VERSION 5.7 ;
  NOWIREEXTENSIONATPIN ON ;
  DIVIDERCHAR "/" ;
  BUSBITCHARS "[]" ;
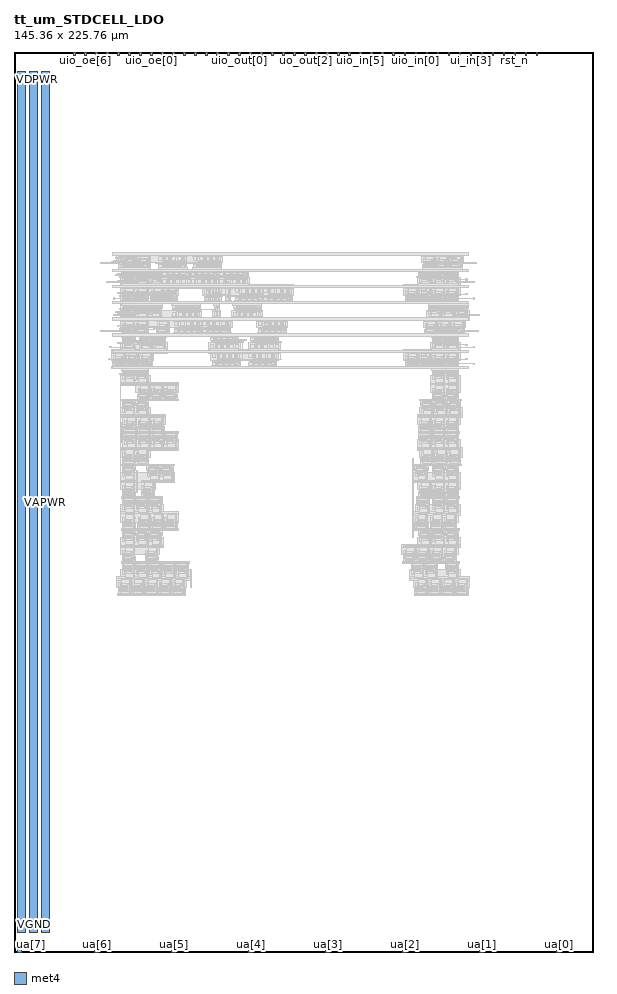
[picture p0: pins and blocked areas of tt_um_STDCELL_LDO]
MACRO tt_um_STDCELL_LDO
  CLASS BLOCK ;
  FOREIGN tt_um_STDCELL_LDO ;
  ORIGIN 0.000 0.000 ;
  SIZE 145.360 BY 225.760 ;
  PIN clk
    DIRECTION INPUT ;
    USE SIGNAL ;
    PORT
      LAYER met4 ;
        RECT 128.190 224.760 128.490 225.760 ;
    END
  END clk
  PIN ena
    DIRECTION INPUT ;
    USE SIGNAL ;
    PORT
      LAYER met4 ;
        RECT 130.950 224.760 131.250 225.760 ;
    END
  END ena
  PIN rst_n
    DIRECTION INPUT ;
    USE SIGNAL ;
    PORT
      LAYER met4 ;
        RECT 125.430 224.760 125.730 225.760 ;
    END
  END rst_n
  PIN ua[0]
    DIRECTION INOUT ;
    USE SIGNAL ;
    ANTENNAGATEAREA 9.000000 ;
    PORT
      LAYER met4 ;
        RECT 136.170 0.000 137.070 1.000 ;
    END
  END ua[0]
  PIN ua[1]
    DIRECTION INOUT ;
    USE SIGNAL ;
    ANTENNAGATEAREA 18.000000 ;
    ANTENNADIFFAREA 1.282500 ;
    PORT
      LAYER met4 ;
        RECT 116.850 0.000 117.750 1.000 ;
    END
  END ua[1]
  PIN ua[2]
    DIRECTION INOUT ;
    USE SIGNAL ;
    ANTENNAGATEAREA 1.125000 ;
    PORT
      LAYER met4 ;
        RECT 97.530 0.000 98.430 1.000 ;
    END
  END ua[2]
  PIN ua[3]
    DIRECTION INOUT ;
    USE SIGNAL ;
    ANTENNAGATEAREA 9.000000 ;
    ANTENNADIFFAREA 82.079994 ;
    PORT
      LAYER met4 ;
        RECT 78.210 0.000 79.110 1.000 ;
    END
  END ua[3]
  PIN ua[4]
    DIRECTION INOUT ;
    USE SIGNAL ;
    PORT
      LAYER met4 ;
        RECT 58.890 0.000 59.790 1.000 ;
    END
  END ua[4]
  PIN ua[5]
    DIRECTION INOUT ;
    USE SIGNAL ;
    PORT
      LAYER met4 ;
        RECT 39.570 0.000 40.470 1.000 ;
    END
  END ua[5]
  PIN ua[6]
    DIRECTION INOUT ;
    USE SIGNAL ;
    PORT
      LAYER met4 ;
        RECT 20.250 0.000 21.150 1.000 ;
    END
  END ua[6]
  PIN ua[7]
    DIRECTION INOUT ;
    USE SIGNAL ;
    PORT
      LAYER met4 ;
        RECT 0.930 0.000 1.830 1.000 ;
    END
  END ua[7]
  PIN ui_in[0]
    DIRECTION INPUT ;
    USE SIGNAL ;
    PORT
      LAYER met4 ;
        RECT 122.670 224.760 122.970 225.760 ;
    END
  END ui_in[0]
  PIN ui_in[1]
    DIRECTION INPUT ;
    USE SIGNAL ;
    PORT
      LAYER met4 ;
        RECT 119.910 224.760 120.210 225.760 ;
    END
  END ui_in[1]
  PIN ui_in[2]
    DIRECTION INPUT ;
    USE SIGNAL ;
    PORT
      LAYER met4 ;
        RECT 117.150 224.760 117.450 225.760 ;
    END
  END ui_in[2]
  PIN ui_in[3]
    DIRECTION INPUT ;
    USE SIGNAL ;
    PORT
      LAYER met4 ;
        RECT 114.390 224.760 114.690 225.760 ;
    END
  END ui_in[3]
  PIN ui_in[4]
    DIRECTION INPUT ;
    USE SIGNAL ;
    PORT
      LAYER met4 ;
        RECT 111.630 224.760 111.930 225.760 ;
    END
  END ui_in[4]
  PIN ui_in[5]
    DIRECTION INPUT ;
    USE SIGNAL ;
    PORT
      LAYER met4 ;
        RECT 108.870 224.760 109.170 225.760 ;
    END
  END ui_in[5]
  PIN ui_in[6]
    DIRECTION INPUT ;
    USE SIGNAL ;
    PORT
      LAYER met4 ;
        RECT 106.110 224.760 106.410 225.760 ;
    END
  END ui_in[6]
  PIN ui_in[7]
    DIRECTION INPUT ;
    USE SIGNAL ;
    PORT
      LAYER met4 ;
        RECT 103.350 224.760 103.650 225.760 ;
    END
  END ui_in[7]
  PIN uio_in[0]
    DIRECTION INPUT ;
    USE SIGNAL ;
    PORT
      LAYER met4 ;
        RECT 100.590 224.760 100.890 225.760 ;
    END
  END uio_in[0]
  PIN uio_in[1]
    DIRECTION INPUT ;
    USE SIGNAL ;
    PORT
      LAYER met4 ;
        RECT 97.830 224.760 98.130 225.760 ;
    END
  END uio_in[1]
  PIN uio_in[2]
    DIRECTION INPUT ;
    USE SIGNAL ;
    PORT
      LAYER met4 ;
        RECT 95.070 224.760 95.370 225.760 ;
    END
  END uio_in[2]
  PIN uio_in[3]
    DIRECTION INPUT ;
    USE SIGNAL ;
    PORT
      LAYER met4 ;
        RECT 92.310 224.760 92.610 225.760 ;
    END
  END uio_in[3]
  PIN uio_in[4]
    DIRECTION INPUT ;
    USE SIGNAL ;
    PORT
      LAYER met4 ;
        RECT 89.550 224.760 89.850 225.760 ;
    END
  END uio_in[4]
  PIN uio_in[5]
    DIRECTION INPUT ;
    USE SIGNAL ;
    PORT
      LAYER met4 ;
        RECT 86.790 224.760 87.090 225.760 ;
    END
  END uio_in[5]
  PIN uio_in[6]
    DIRECTION INPUT ;
    USE SIGNAL ;
    PORT
      LAYER met4 ;
        RECT 84.030 224.760 84.330 225.760 ;
    END
  END uio_in[6]
  PIN uio_in[7]
    DIRECTION INPUT ;
    USE SIGNAL ;
    PORT
      LAYER met4 ;
        RECT 81.270 224.760 81.570 225.760 ;
    END
  END uio_in[7]
  PIN uio_oe[0]
    DIRECTION OUTPUT ;
    USE SIGNAL ;
    PORT
      LAYER met4 ;
        RECT 34.350 224.760 34.650 225.760 ;
    END
  END uio_oe[0]
  PIN uio_oe[1]
    DIRECTION OUTPUT ;
    USE SIGNAL ;
    PORT
      LAYER met4 ;
        RECT 31.590 224.760 31.890 225.760 ;
    END
  END uio_oe[1]
  PIN uio_oe[2]
    DIRECTION OUTPUT ;
    USE SIGNAL ;
    PORT
      LAYER met4 ;
        RECT 28.830 224.760 29.130 225.760 ;
    END
  END uio_oe[2]
  PIN uio_oe[3]
    DIRECTION OUTPUT ;
    USE SIGNAL ;
    PORT
      LAYER met4 ;
        RECT 26.070 224.760 26.370 225.760 ;
    END
  END uio_oe[3]
  PIN uio_oe[4]
    DIRECTION OUTPUT ;
    USE SIGNAL ;
    PORT
      LAYER met4 ;
        RECT 23.310 224.760 23.610 225.760 ;
    END
  END uio_oe[4]
  PIN uio_oe[5]
    DIRECTION OUTPUT ;
    USE SIGNAL ;
    PORT
      LAYER met4 ;
        RECT 20.550 224.760 20.850 225.760 ;
    END
  END uio_oe[5]
  PIN uio_oe[6]
    DIRECTION OUTPUT ;
    USE SIGNAL ;
    PORT
      LAYER met4 ;
        RECT 17.790 224.760 18.090 225.760 ;
    END
  END uio_oe[6]
  PIN uio_oe[7]
    DIRECTION OUTPUT ;
    USE SIGNAL ;
    PORT
      LAYER met4 ;
        RECT 15.030 224.760 15.330 225.760 ;
    END
  END uio_oe[7]
  PIN uio_out[0]
    DIRECTION OUTPUT ;
    USE SIGNAL ;
    PORT
      LAYER met4 ;
        RECT 56.430 224.760 56.730 225.760 ;
    END
  END uio_out[0]
  PIN uio_out[1]
    DIRECTION OUTPUT ;
    USE SIGNAL ;
    PORT
      LAYER met4 ;
        RECT 53.670 224.760 53.970 225.760 ;
    END
  END uio_out[1]
  PIN uio_out[2]
    DIRECTION OUTPUT ;
    USE SIGNAL ;
    PORT
      LAYER met4 ;
        RECT 50.910 224.760 51.210 225.760 ;
    END
  END uio_out[2]
  PIN uio_out[3]
    DIRECTION OUTPUT ;
    USE SIGNAL ;
    PORT
      LAYER met4 ;
        RECT 48.150 224.760 48.450 225.760 ;
    END
  END uio_out[3]
  PIN uio_out[4]
    DIRECTION OUTPUT ;
    USE SIGNAL ;
    PORT
      LAYER met4 ;
        RECT 45.390 224.760 45.690 225.760 ;
    END
  END uio_out[4]
  PIN uio_out[5]
    DIRECTION OUTPUT ;
    USE SIGNAL ;
    PORT
      LAYER met4 ;
        RECT 42.630 224.760 42.930 225.760 ;
    END
  END uio_out[5]
  PIN uio_out[6]
    DIRECTION OUTPUT ;
    USE SIGNAL ;
    PORT
      LAYER met4 ;
        RECT 39.870 224.760 40.170 225.760 ;
    END
  END uio_out[6]
  PIN uio_out[7]
    DIRECTION OUTPUT ;
    USE SIGNAL ;
    PORT
      LAYER met4 ;
        RECT 37.110 224.760 37.410 225.760 ;
    END
  END uio_out[7]
  PIN uo_out[0]
    DIRECTION OUTPUT ;
    USE SIGNAL ;
    PORT
      LAYER met4 ;
        RECT 78.510 224.760 78.810 225.760 ;
    END
  END uo_out[0]
  PIN uo_out[1]
    DIRECTION OUTPUT ;
    USE SIGNAL ;
    PORT
      LAYER met4 ;
        RECT 75.750 224.760 76.050 225.760 ;
    END
  END uo_out[1]
  PIN uo_out[2]
    DIRECTION OUTPUT ;
    USE SIGNAL ;
    PORT
      LAYER met4 ;
        RECT 72.990 224.760 73.290 225.760 ;
    END
  END uo_out[2]
  PIN uo_out[3]
    DIRECTION OUTPUT ;
    USE SIGNAL ;
    PORT
      LAYER met4 ;
        RECT 70.230 224.760 70.530 225.760 ;
    END
  END uo_out[3]
  PIN uo_out[4]
    DIRECTION OUTPUT ;
    USE SIGNAL ;
    PORT
      LAYER met4 ;
        RECT 67.470 224.760 67.770 225.760 ;
    END
  END uo_out[4]
  PIN uo_out[5]
    DIRECTION OUTPUT ;
    USE SIGNAL ;
    PORT
      LAYER met4 ;
        RECT 64.710 224.760 65.010 225.760 ;
    END
  END uo_out[5]
  PIN uo_out[6]
    DIRECTION OUTPUT ;
    USE SIGNAL ;
    PORT
      LAYER met4 ;
        RECT 61.950 224.760 62.250 225.760 ;
    END
  END uo_out[6]
  PIN uo_out[7]
    DIRECTION OUTPUT ;
    USE SIGNAL ;
    PORT
      LAYER met4 ;
        RECT 59.190 224.760 59.490 225.760 ;
    END
  END uo_out[7]
  PIN VDPWR
    DIRECTION INOUT ;
    USE POWER ;
    PORT
      LAYER met4 ;
        RECT 1.000 5.000 3.000 220.760 ;
    END
  END VDPWR
  PIN VGND
    DIRECTION INOUT ;
    USE GROUND ;
    PORT
      LAYER met4 ;
        RECT 4.000 5.000 6.000 220.760 ;
    END
  END VGND
  PIN VAPWR
    DIRECTION INOUT ;
    USE POWER ;
    PORT
      LAYER met4 ;
        RECT 7.000 5.000 9.000 220.760 ;
    END
  END VAPWR
  OBS
      LAYER nwell ;
        RECT 25.800 172.905 52.380 175.505 ;
        RECT 102.120 172.905 112.860 175.505 ;
      LAYER pwell ;
        RECT 26.220 171.235 27.550 172.435 ;
        RECT 27.590 171.235 30.910 172.515 ;
        RECT 30.950 171.235 34.270 172.515 ;
        RECT 36.475 171.235 43.375 172.605 ;
        RECT 45.115 171.235 52.015 172.605 ;
        RECT 102.470 171.235 105.790 172.515 ;
        RECT 105.830 171.235 109.150 172.515 ;
        RECT 109.190 171.235 112.510 172.515 ;
        RECT 26.000 170.805 58.900 171.235 ;
        RECT 101.360 170.805 112.660 171.235 ;
        RECT 27.110 169.525 30.430 170.805 ;
        RECT 30.470 169.525 33.790 170.805 ;
        RECT 33.830 169.525 37.150 170.805 ;
        RECT 37.435 169.435 44.335 170.805 ;
        RECT 44.635 169.435 51.535 170.805 ;
        RECT 51.835 169.435 58.735 170.805 ;
        RECT 101.510 169.525 104.830 170.805 ;
        RECT 104.870 169.525 108.190 170.805 ;
        RECT 108.230 169.525 111.550 170.805 ;
      LAYER nwell ;
        RECT 26.760 167.365 59.100 169.135 ;
        RECT 101.160 167.365 111.900 169.135 ;
        RECT 26.760 166.535 70.140 167.365 ;
        RECT 26.760 164.765 41.340 166.535 ;
        RECT 47.400 164.765 70.140 166.535 ;
        RECT 97.800 164.765 111.900 167.365 ;
      LAYER pwell ;
        RECT 27.110 163.095 30.430 164.375 ;
        RECT 30.470 163.095 33.790 164.375 ;
        RECT 34.310 163.095 37.630 164.375 ;
        RECT 37.670 163.095 40.990 164.375 ;
        RECT 47.820 163.095 49.150 164.295 ;
        RECT 49.260 163.095 50.590 164.295 ;
        RECT 50.700 163.095 52.030 164.295 ;
        RECT 53.100 163.095 54.430 164.295 ;
        RECT 55.675 163.095 62.575 164.465 ;
        RECT 62.875 163.095 69.775 164.465 ;
        RECT 98.150 163.095 101.470 164.375 ;
        RECT 101.510 163.095 104.830 164.375 ;
        RECT 104.870 163.095 108.190 164.375 ;
        RECT 108.230 163.095 111.550 164.375 ;
        RECT 26.960 162.665 46.900 163.095 ;
        RECT 47.600 162.665 52.180 163.095 ;
        RECT 52.880 162.665 54.580 163.095 ;
        RECT 54.800 162.665 69.940 163.095 ;
        RECT 98.000 162.665 114.100 163.095 ;
        RECT 27.110 161.385 30.430 162.665 ;
        RECT 30.470 161.385 33.790 162.665 ;
        RECT 33.830 161.385 37.150 162.665 ;
        RECT 39.835 161.295 46.735 162.665 ;
        RECT 50.220 161.465 51.550 162.665 ;
        RECT 55.195 161.295 62.095 162.665 ;
        RECT 103.910 161.385 107.230 162.665 ;
        RECT 107.270 161.385 110.590 162.665 ;
        RECT 110.630 161.385 113.950 162.665 ;
      LAYER nwell ;
        RECT 26.760 159.225 47.100 160.995 ;
        RECT 49.800 159.225 51.900 160.995 ;
        RECT 54.600 159.225 62.460 160.995 ;
        RECT 103.560 159.225 114.300 160.995 ;
        RECT 26.760 158.395 68.700 159.225 ;
        RECT 26.760 156.625 54.780 158.395 ;
        RECT 60.840 156.625 68.700 158.395 ;
        RECT 102.600 158.395 114.300 159.225 ;
        RECT 102.600 156.625 113.340 158.395 ;
      LAYER pwell ;
        RECT 27.110 154.955 30.430 156.235 ;
        RECT 30.470 154.955 33.790 156.235 ;
        RECT 35.750 154.955 39.070 156.235 ;
        RECT 40.315 154.955 47.215 156.325 ;
        RECT 47.515 154.955 54.415 156.325 ;
        RECT 61.435 154.955 68.335 156.325 ;
        RECT 102.950 154.955 106.270 156.235 ;
        RECT 106.310 154.955 109.630 156.235 ;
        RECT 109.670 154.955 112.990 156.235 ;
        RECT 26.960 154.525 39.220 154.955 ;
        RECT 39.920 154.525 56.500 154.955 ;
        RECT 59.120 154.525 68.500 154.955 ;
        RECT 102.800 154.525 113.140 154.955 ;
        RECT 27.110 153.245 30.430 154.525 ;
        RECT 31.430 153.245 34.750 154.525 ;
        RECT 34.790 153.245 38.110 154.525 ;
        RECT 49.435 153.155 56.335 154.525 ;
        RECT 59.515 153.155 66.415 154.525 ;
        RECT 104.870 153.245 108.190 154.525 ;
        RECT 108.230 153.245 111.550 154.525 ;
      LAYER nwell ;
        RECT 26.760 151.085 38.460 152.855 ;
        RECT 24.360 150.255 38.460 151.085 ;
        RECT 48.840 151.085 56.700 152.855 ;
        RECT 58.920 151.085 66.780 152.855 ;
        RECT 104.520 151.085 111.900 152.855 ;
        RECT 48.840 150.255 66.780 151.085 ;
        RECT 24.360 148.485 35.100 150.255 ;
        RECT 49.320 148.485 66.300 150.255 ;
        RECT 97.800 148.485 111.900 151.085 ;
      LAYER pwell ;
        RECT 24.710 146.815 28.030 148.095 ;
        RECT 28.070 146.815 31.390 148.095 ;
        RECT 31.430 146.815 34.750 148.095 ;
        RECT 49.915 146.815 56.815 148.185 ;
        RECT 59.035 146.815 65.935 148.185 ;
        RECT 98.150 146.815 101.470 148.095 ;
        RECT 101.510 146.815 104.830 148.095 ;
        RECT 104.870 146.815 108.190 148.095 ;
        RECT 108.230 146.815 111.550 148.095 ;
        RECT 24.560 146.385 34.900 146.815 ;
        RECT 49.520 146.385 56.980 146.815 ;
        RECT 58.640 146.385 66.100 146.815 ;
        RECT 98.000 146.385 111.700 146.815 ;
        RECT 27.110 145.105 30.430 146.385 ;
        RECT 30.470 145.105 33.790 146.385 ;
        RECT 104.870 145.105 108.190 146.385 ;
        RECT 108.230 145.105 111.550 146.385 ;
      LAYER nwell ;
        RECT 26.760 142.945 34.140 144.715 ;
        RECT 26.760 142.115 41.340 142.945 ;
        RECT 30.600 140.345 41.340 142.115 ;
        RECT 104.520 140.345 111.900 144.715 ;
      LAYER pwell ;
        RECT 30.950 138.675 34.270 139.955 ;
        RECT 34.310 138.675 37.630 139.955 ;
        RECT 37.670 138.675 40.990 139.955 ;
        RECT 104.870 138.675 108.190 139.955 ;
        RECT 108.230 138.675 111.550 139.955 ;
        RECT 26.960 138.245 41.140 138.675 ;
        RECT 101.840 138.245 112.180 138.675 ;
        RECT 27.110 136.965 30.430 138.245 ;
        RECT 30.470 136.965 33.790 138.245 ;
        RECT 101.990 136.965 105.310 138.245 ;
        RECT 105.350 136.965 108.670 138.245 ;
        RECT 108.710 136.965 112.030 138.245 ;
      LAYER nwell ;
        RECT 26.760 134.805 34.140 136.575 ;
        RECT 101.640 134.805 112.380 136.575 ;
        RECT 26.760 133.975 37.980 134.805 ;
        RECT 27.240 132.205 37.980 133.975 ;
        RECT 101.160 133.975 112.380 134.805 ;
        RECT 101.160 132.205 111.900 133.975 ;
      LAYER pwell ;
        RECT 27.590 130.535 30.910 131.815 ;
        RECT 30.950 130.535 34.270 131.815 ;
        RECT 34.310 130.535 37.630 131.815 ;
        RECT 101.510 130.535 104.830 131.815 ;
        RECT 104.870 130.535 108.190 131.815 ;
        RECT 108.230 130.535 111.550 131.815 ;
        RECT 27.440 130.105 41.140 130.535 ;
        RECT 101.360 130.105 111.700 130.535 ;
        RECT 27.590 128.825 30.910 130.105 ;
        RECT 30.950 128.825 34.270 130.105 ;
        RECT 34.310 128.825 37.630 130.105 ;
        RECT 37.670 128.825 40.990 130.105 ;
        RECT 101.510 128.825 104.830 130.105 ;
        RECT 104.870 128.825 108.190 130.105 ;
        RECT 108.230 128.825 111.550 130.105 ;
      LAYER nwell ;
        RECT 27.240 126.665 41.340 128.435 ;
        RECT 26.760 125.835 41.340 126.665 ;
        RECT 101.160 126.665 111.900 128.435 ;
        RECT 101.160 125.835 112.380 126.665 ;
        RECT 26.760 124.065 34.140 125.835 ;
        RECT 101.640 124.065 112.380 125.835 ;
      LAYER pwell ;
        RECT 27.110 122.395 30.430 123.675 ;
        RECT 30.470 122.395 33.790 123.675 ;
        RECT 101.990 122.395 105.310 123.675 ;
        RECT 105.350 122.395 108.670 123.675 ;
        RECT 108.710 122.395 112.030 123.675 ;
        RECT 26.960 121.965 40.180 122.395 ;
        RECT 100.400 121.965 112.180 122.395 ;
        RECT 27.110 120.685 30.430 121.965 ;
        RECT 33.350 120.685 36.670 121.965 ;
        RECT 36.710 120.685 40.030 121.965 ;
        RECT 100.550 120.685 103.870 121.965 ;
        RECT 104.870 120.685 108.190 121.965 ;
        RECT 108.230 120.685 111.550 121.965 ;
      LAYER nwell ;
        RECT 26.760 117.695 40.380 120.295 ;
        RECT 100.200 117.695 111.900 120.295 ;
        RECT 26.760 115.925 35.580 117.695 ;
        RECT 101.160 115.925 111.900 117.695 ;
      LAYER pwell ;
        RECT 27.110 114.255 30.430 115.535 ;
        RECT 31.910 114.255 35.230 115.535 ;
        RECT 101.510 114.255 104.830 115.535 ;
        RECT 104.870 114.255 108.190 115.535 ;
        RECT 108.230 114.255 111.550 115.535 ;
        RECT 26.960 113.825 37.300 114.255 ;
        RECT 100.880 113.825 111.700 114.255 ;
        RECT 27.110 112.545 30.430 113.825 ;
        RECT 30.470 112.545 33.790 113.825 ;
        RECT 33.830 112.545 37.150 113.825 ;
        RECT 101.030 112.545 104.350 113.825 ;
        RECT 104.870 112.545 108.190 113.825 ;
        RECT 108.230 112.545 111.550 113.825 ;
      LAYER nwell ;
        RECT 26.760 110.385 37.500 112.155 ;
        RECT 100.680 110.385 111.900 112.155 ;
        RECT 26.760 107.785 41.340 110.385 ;
        RECT 100.200 109.555 111.900 110.385 ;
        RECT 100.200 107.785 111.420 109.555 ;
      LAYER pwell ;
        RECT 27.110 106.115 30.430 107.395 ;
        RECT 30.950 106.115 34.270 107.395 ;
        RECT 34.310 106.115 37.630 107.395 ;
        RECT 37.670 106.115 40.990 107.395 ;
        RECT 100.550 106.115 103.870 107.395 ;
        RECT 104.390 106.115 107.710 107.395 ;
        RECT 107.750 106.115 111.070 107.395 ;
        RECT 26.960 105.685 41.140 106.115 ;
        RECT 100.400 105.685 111.700 106.115 ;
        RECT 27.110 104.405 30.430 105.685 ;
        RECT 30.470 104.405 33.790 105.685 ;
        RECT 33.830 104.405 37.150 105.685 ;
        RECT 101.510 104.405 104.830 105.685 ;
        RECT 104.870 104.405 108.190 105.685 ;
        RECT 108.230 104.405 111.550 105.685 ;
      LAYER nwell ;
        RECT 26.760 101.415 37.500 104.015 ;
        RECT 101.160 102.245 111.900 104.015 ;
        RECT 97.320 101.415 111.900 102.245 ;
        RECT 26.760 99.645 36.540 101.415 ;
        RECT 97.320 99.645 111.420 101.415 ;
      LAYER pwell ;
        RECT 27.110 97.975 30.430 99.255 ;
        RECT 32.870 97.975 36.190 99.255 ;
        RECT 97.670 97.975 100.990 99.255 ;
        RECT 101.030 97.975 104.350 99.255 ;
        RECT 104.390 97.975 107.710 99.255 ;
        RECT 107.750 97.975 111.070 99.255 ;
        RECT 26.960 97.545 44.020 97.975 ;
        RECT 97.520 97.545 111.700 97.975 ;
        RECT 27.110 96.265 30.430 97.545 ;
        RECT 30.470 96.265 33.790 97.545 ;
        RECT 33.830 96.265 37.150 97.545 ;
        RECT 37.190 96.265 40.510 97.545 ;
        RECT 40.550 96.265 43.870 97.545 ;
        RECT 99.590 96.265 102.910 97.545 ;
        RECT 102.950 96.265 106.270 97.545 ;
        RECT 108.230 96.265 111.550 97.545 ;
      LAYER nwell ;
        RECT 26.760 94.105 44.220 95.875 ;
        RECT 25.800 93.275 44.220 94.105 ;
        RECT 99.240 94.105 111.900 95.875 ;
        RECT 99.240 93.275 114.300 94.105 ;
        RECT 25.800 91.505 43.260 93.275 ;
        RECT 100.200 91.505 114.300 93.275 ;
      LAYER pwell ;
        RECT 26.150 89.835 29.470 91.115 ;
        RECT 29.510 89.835 32.830 91.115 ;
        RECT 32.870 89.835 36.190 91.115 ;
        RECT 36.230 89.835 39.550 91.115 ;
        RECT 39.590 89.835 42.910 91.115 ;
        RECT 100.550 89.835 103.870 91.115 ;
        RECT 103.910 89.835 107.230 91.115 ;
        RECT 107.270 89.835 110.590 91.115 ;
        RECT 110.630 89.835 113.950 91.115 ;
        RECT 26.000 89.405 43.060 89.835 ;
        RECT 100.400 89.405 114.100 89.835 ;
      LAYER li1 ;
        RECT 26.130 175.005 34.290 175.175 ;
        RECT 36.210 175.005 43.410 175.175 ;
        RECT 44.850 175.005 52.050 175.175 ;
        RECT 102.450 175.005 112.530 175.175 ;
        RECT 26.220 173.195 26.810 174.775 ;
        RECT 27.090 174.215 27.475 174.775 ;
        RECT 27.090 174.045 27.485 174.215 ;
        RECT 27.090 173.195 27.475 174.045 ;
        RECT 26.255 172.570 26.965 172.955 ;
        RECT 26.220 171.385 26.810 172.345 ;
        RECT 27.145 171.515 27.475 173.195 ;
        RECT 27.745 173.120 28.220 174.025 ;
        RECT 28.400 173.730 30.370 174.775 ;
        RECT 30.550 174.215 30.805 174.775 ;
        RECT 30.550 174.045 30.885 174.215 ;
        RECT 28.400 173.300 29.845 173.730 ;
        RECT 27.745 172.950 29.635 173.120 ;
        RECT 30.015 172.975 30.380 173.560 ;
        RECT 30.550 173.145 30.805 174.045 ;
        RECT 27.745 172.355 27.915 172.950 ;
        RECT 28.085 172.525 28.875 172.770 ;
        RECT 29.045 172.745 29.635 172.950 ;
        RECT 29.845 172.645 30.435 172.975 ;
        RECT 27.745 171.925 27.950 172.355 ;
        RECT 28.120 172.010 29.845 172.355 ;
        RECT 30.015 172.180 30.380 172.645 ;
        RECT 30.605 172.475 30.805 173.145 ;
        RECT 28.120 171.755 30.370 172.010 ;
        RECT 28.040 171.385 30.370 171.755 ;
        RECT 30.550 171.595 30.805 172.475 ;
        RECT 31.105 173.120 31.580 174.025 ;
        RECT 31.760 173.730 33.730 174.775 ;
        RECT 31.760 173.300 33.205 173.730 ;
        RECT 31.105 172.950 32.995 173.120 ;
        RECT 33.375 172.975 33.740 173.560 ;
        RECT 33.910 173.145 34.165 174.775 ;
        RECT 36.305 174.645 43.235 174.815 ;
        RECT 36.305 173.465 37.195 174.645 ;
        RECT 31.105 172.355 31.275 172.950 ;
        RECT 31.445 172.525 32.235 172.770 ;
        RECT 32.405 172.745 32.995 172.950 ;
        RECT 33.205 172.645 33.795 172.975 ;
        RECT 31.105 171.925 31.310 172.355 ;
        RECT 31.480 172.010 33.205 172.355 ;
        RECT 33.375 172.180 33.740 172.645 ;
        RECT 33.965 172.475 34.165 173.145 ;
        RECT 37.485 173.225 37.815 174.465 ;
        RECT 37.985 173.405 38.875 174.645 ;
        RECT 39.045 173.225 39.375 174.465 ;
        RECT 39.545 173.405 40.435 174.645 ;
        RECT 40.605 173.225 40.935 174.465 ;
        RECT 41.105 173.405 41.995 174.645 ;
        RECT 42.165 173.225 42.495 174.465 ;
        RECT 42.665 173.405 43.235 174.645 ;
        RECT 44.945 174.645 51.875 174.815 ;
        RECT 44.945 173.465 45.835 174.645 ;
        RECT 46.125 173.225 46.455 174.465 ;
        RECT 46.625 173.405 47.515 174.645 ;
        RECT 47.685 173.225 48.015 174.465 ;
        RECT 48.185 173.405 49.075 174.645 ;
        RECT 49.245 173.225 49.575 174.465 ;
        RECT 49.745 173.405 50.635 174.645 ;
        RECT 50.805 173.225 51.135 174.465 ;
        RECT 51.305 173.405 51.875 174.645 ;
        RECT 37.485 173.055 43.320 173.225 ;
        RECT 46.125 173.055 51.960 173.225 ;
        RECT 38.875 173.025 39.045 173.055 ;
        RECT 36.495 172.835 36.665 172.855 ;
        RECT 36.495 172.685 42.970 172.835 ;
        RECT 36.520 172.600 42.970 172.685 ;
        RECT 31.480 171.755 33.730 172.010 ;
        RECT 31.400 171.385 33.730 171.755 ;
        RECT 33.910 171.595 34.165 172.475 ;
        RECT 37.405 172.415 42.435 172.420 ;
        RECT 43.150 172.415 43.320 173.055 ;
        RECT 45.335 172.835 45.505 172.855 ;
        RECT 45.160 172.600 51.610 172.835 ;
        RECT 36.305 171.570 37.195 172.405 ;
        RECT 37.405 172.250 43.320 172.415 ;
        RECT 46.045 172.415 51.075 172.420 ;
        RECT 51.790 172.415 51.960 173.055 ;
        RECT 37.405 171.750 37.615 172.250 ;
        RECT 37.785 171.570 38.795 172.065 ;
        RECT 38.965 171.750 39.175 172.250 ;
        RECT 39.345 171.570 40.355 172.065 ;
        RECT 40.525 171.750 40.735 172.250 ;
        RECT 42.125 172.245 43.320 172.250 ;
        RECT 40.905 171.570 41.955 172.065 ;
        RECT 42.125 171.750 42.775 172.245 ;
        RECT 42.945 171.570 43.315 172.065 ;
        RECT 36.305 171.400 43.315 171.570 ;
        RECT 44.945 171.570 45.835 172.405 ;
        RECT 46.045 172.250 51.960 172.415 ;
        RECT 46.045 171.750 46.255 172.250 ;
        RECT 46.425 171.570 47.435 172.065 ;
        RECT 47.605 171.750 47.815 172.250 ;
        RECT 47.985 171.570 48.995 172.065 ;
        RECT 49.165 171.750 49.375 172.250 ;
        RECT 50.765 172.245 51.960 172.250 ;
        RECT 102.625 173.120 103.100 174.025 ;
        RECT 103.280 173.730 105.250 174.775 ;
        RECT 103.280 173.300 104.725 173.730 ;
        RECT 102.625 172.950 104.515 173.120 ;
        RECT 104.895 172.975 105.260 173.560 ;
        RECT 105.430 173.145 105.685 174.775 ;
        RECT 102.625 172.355 102.795 172.950 ;
        RECT 102.965 172.525 103.755 172.770 ;
        RECT 103.925 172.745 104.515 172.950 ;
        RECT 104.725 172.645 105.315 172.975 ;
        RECT 49.545 171.570 50.595 172.065 ;
        RECT 50.765 171.750 51.415 172.245 ;
        RECT 51.585 171.570 51.955 172.065 ;
        RECT 102.625 171.925 102.830 172.355 ;
        RECT 103.000 172.010 104.725 172.355 ;
        RECT 104.895 172.180 105.260 172.645 ;
        RECT 105.485 172.475 105.685 173.145 ;
        RECT 103.000 171.755 105.250 172.010 ;
        RECT 44.945 171.400 51.955 171.570 ;
        RECT 102.920 171.385 105.250 171.755 ;
        RECT 105.430 171.595 105.685 172.475 ;
        RECT 105.985 173.120 106.460 174.025 ;
        RECT 106.640 173.730 108.610 174.775 ;
        RECT 108.790 174.215 109.045 174.775 ;
        RECT 108.790 174.045 109.085 174.215 ;
        RECT 106.640 173.300 108.085 173.730 ;
        RECT 105.985 172.950 107.875 173.120 ;
        RECT 108.255 172.975 108.620 173.560 ;
        RECT 108.790 173.145 109.045 174.045 ;
        RECT 105.985 172.355 106.155 172.950 ;
        RECT 106.325 172.525 107.115 172.770 ;
        RECT 107.285 172.745 107.875 172.950 ;
        RECT 108.085 172.645 108.675 172.975 ;
        RECT 105.985 171.925 106.190 172.355 ;
        RECT 106.360 172.010 108.085 172.355 ;
        RECT 108.255 172.180 108.620 172.645 ;
        RECT 108.845 172.475 109.045 173.145 ;
        RECT 106.360 171.755 108.610 172.010 ;
        RECT 106.280 171.385 108.610 171.755 ;
        RECT 108.790 171.595 109.045 172.475 ;
        RECT 109.345 173.120 109.820 174.025 ;
        RECT 110.000 173.730 111.970 174.775 ;
        RECT 110.000 173.300 111.445 173.730 ;
        RECT 109.345 172.950 111.235 173.120 ;
        RECT 111.615 172.975 111.980 173.560 ;
        RECT 112.150 173.145 112.405 174.775 ;
        RECT 109.345 172.355 109.515 172.950 ;
        RECT 109.685 172.525 110.475 172.770 ;
        RECT 110.645 172.745 111.235 172.950 ;
        RECT 111.445 172.645 112.035 172.975 ;
        RECT 112.205 172.855 112.405 173.145 ;
        RECT 112.205 172.685 112.485 172.855 ;
        RECT 109.345 171.925 109.550 172.355 ;
        RECT 109.720 172.010 111.445 172.355 ;
        RECT 111.615 172.180 111.980 172.645 ;
        RECT 112.205 172.475 112.405 172.685 ;
        RECT 109.720 171.755 111.970 172.010 ;
        RECT 109.640 171.385 111.970 171.755 ;
        RECT 112.150 171.595 112.405 172.475 ;
        RECT 26.130 170.935 58.770 171.105 ;
        RECT 101.490 170.935 112.530 171.105 ;
        RECT 27.560 170.285 29.890 170.655 ;
        RECT 27.265 169.685 27.470 170.115 ;
        RECT 27.640 170.030 29.890 170.285 ;
        RECT 27.640 169.685 29.365 170.030 ;
        RECT 26.635 156.280 26.805 169.455 ;
        RECT 27.265 169.090 27.435 169.685 ;
        RECT 27.605 169.270 28.395 169.515 ;
        RECT 29.535 169.395 29.900 169.860 ;
        RECT 30.070 169.565 30.325 170.445 ;
        RECT 30.920 170.285 33.250 170.655 ;
        RECT 28.565 169.090 29.155 169.295 ;
        RECT 27.265 168.920 29.155 169.090 ;
        RECT 29.365 169.065 29.955 169.395 ;
        RECT 27.265 168.015 27.740 168.920 ;
        RECT 27.920 168.310 29.365 168.740 ;
        RECT 29.535 168.480 29.900 169.065 ;
        RECT 30.125 168.895 30.325 169.565 ;
        RECT 27.920 167.265 29.890 168.310 ;
        RECT 30.070 168.095 30.325 168.895 ;
        RECT 30.625 169.685 30.830 170.115 ;
        RECT 31.000 170.030 33.250 170.285 ;
        RECT 31.000 169.685 32.725 170.030 ;
        RECT 30.625 169.090 30.795 169.685 ;
        RECT 30.965 169.270 31.755 169.515 ;
        RECT 32.895 169.395 33.260 169.860 ;
        RECT 33.430 169.565 33.685 170.445 ;
        RECT 34.280 170.285 36.610 170.655 ;
        RECT 37.265 170.470 44.275 170.640 ;
        RECT 31.925 169.090 32.515 169.295 ;
        RECT 30.625 168.920 32.515 169.090 ;
        RECT 32.725 169.065 33.315 169.395 ;
        RECT 32.895 168.945 33.265 169.065 ;
        RECT 30.070 167.925 30.375 168.095 ;
        RECT 30.625 168.015 31.100 168.920 ;
        RECT 31.280 168.310 32.725 168.740 ;
        RECT 32.895 168.480 33.260 168.945 ;
        RECT 33.485 168.895 33.685 169.565 ;
        RECT 30.070 167.265 30.325 167.925 ;
        RECT 31.280 167.265 33.250 168.310 ;
        RECT 33.430 167.265 33.685 168.895 ;
        RECT 33.985 169.685 34.190 170.115 ;
        RECT 34.360 170.030 36.610 170.285 ;
        RECT 34.360 169.685 36.085 170.030 ;
        RECT 33.985 169.090 34.155 169.685 ;
        RECT 34.325 169.270 35.115 169.515 ;
        RECT 36.255 169.455 36.620 169.860 ;
        RECT 36.790 169.565 37.045 170.445 ;
        RECT 37.265 169.635 38.155 170.470 ;
        RECT 38.365 169.790 38.575 170.290 ;
        RECT 38.745 169.975 39.755 170.470 ;
        RECT 38.875 169.790 39.045 169.795 ;
        RECT 39.925 169.790 40.135 170.290 ;
        RECT 40.305 169.975 41.315 170.470 ;
        RECT 41.485 169.790 41.695 170.290 ;
        RECT 41.865 169.975 42.915 170.470 ;
        RECT 43.085 169.795 43.735 170.290 ;
        RECT 43.905 169.975 44.275 170.470 ;
        RECT 44.465 170.470 51.475 170.640 ;
        RECT 43.085 169.790 44.280 169.795 ;
        RECT 38.365 169.625 44.280 169.790 ;
        RECT 44.465 169.635 45.355 170.470 ;
        RECT 45.565 169.790 45.775 170.290 ;
        RECT 45.945 169.975 46.955 170.470 ;
        RECT 47.125 169.790 47.335 170.290 ;
        RECT 47.505 169.975 48.515 170.470 ;
        RECT 48.685 169.790 48.895 170.290 ;
        RECT 49.065 169.975 50.115 170.470 ;
        RECT 50.285 169.795 50.935 170.290 ;
        RECT 51.105 169.975 51.475 170.470 ;
        RECT 51.665 170.470 58.675 170.640 ;
        RECT 50.285 169.790 51.480 169.795 ;
        RECT 38.365 169.620 43.395 169.625 ;
        RECT 36.155 169.395 36.620 169.455 ;
        RECT 35.285 169.090 35.875 169.295 ;
        RECT 33.985 168.920 35.875 169.090 ;
        RECT 36.085 169.065 36.675 169.395 ;
        RECT 33.985 168.015 34.460 168.920 ;
        RECT 34.640 168.310 36.085 168.740 ;
        RECT 36.255 168.480 36.620 169.065 ;
        RECT 36.845 168.895 37.045 169.565 ;
        RECT 37.515 169.440 37.685 169.455 ;
        RECT 37.480 169.205 43.930 169.440 ;
        RECT 44.110 168.985 44.280 169.625 ;
        RECT 45.565 169.625 51.480 169.790 ;
        RECT 51.665 169.635 52.555 170.470 ;
        RECT 52.765 169.790 52.975 170.290 ;
        RECT 53.145 169.975 54.155 170.470 ;
        RECT 54.325 169.790 54.535 170.290 ;
        RECT 54.705 169.975 55.715 170.470 ;
        RECT 55.885 169.790 56.095 170.290 ;
        RECT 56.265 169.975 57.315 170.470 ;
        RECT 57.485 169.795 58.135 170.290 ;
        RECT 58.305 169.975 58.675 170.470 ;
        RECT 101.960 170.285 104.290 170.655 ;
        RECT 57.485 169.790 58.680 169.795 ;
        RECT 45.565 169.620 50.595 169.625 ;
        RECT 44.655 169.440 44.825 169.455 ;
        RECT 44.655 169.285 51.130 169.440 ;
        RECT 44.680 169.205 51.130 169.285 ;
        RECT 51.310 168.985 51.480 169.625 ;
        RECT 52.765 169.625 58.680 169.790 ;
        RECT 52.765 169.620 57.795 169.625 ;
        RECT 51.795 169.440 51.965 169.455 ;
        RECT 51.795 169.285 58.330 169.440 ;
        RECT 51.880 169.205 58.330 169.285 ;
        RECT 58.510 168.985 58.680 169.625 ;
        RECT 34.640 167.265 36.610 168.310 ;
        RECT 36.790 167.265 37.045 168.895 ;
        RECT 38.445 168.815 44.280 168.985 ;
        RECT 45.645 168.815 51.480 168.985 ;
        RECT 52.845 168.815 58.680 168.985 ;
        RECT 101.665 169.685 101.870 170.115 ;
        RECT 102.040 170.030 104.290 170.285 ;
        RECT 102.040 169.685 103.765 170.030 ;
        RECT 101.665 169.090 101.835 169.685 ;
        RECT 102.005 169.270 102.795 169.515 ;
        RECT 103.935 169.455 104.300 169.860 ;
        RECT 104.470 169.565 104.725 170.445 ;
        RECT 105.320 170.285 107.650 170.655 ;
        RECT 103.815 169.395 104.300 169.455 ;
        RECT 102.965 169.090 103.555 169.295 ;
        RECT 101.665 168.920 103.555 169.090 ;
        RECT 103.765 169.065 104.355 169.395 ;
        RECT 37.265 167.395 38.155 168.575 ;
        RECT 38.445 167.575 38.775 168.815 ;
        RECT 38.945 167.395 39.835 168.635 ;
        RECT 40.005 167.575 40.335 168.815 ;
        RECT 40.505 167.395 41.395 168.635 ;
        RECT 41.565 167.575 41.895 168.815 ;
        RECT 42.065 167.395 42.955 168.635 ;
        RECT 43.125 167.575 43.455 168.815 ;
        RECT 43.625 167.395 44.195 168.635 ;
        RECT 37.265 167.225 44.195 167.395 ;
        RECT 44.465 167.395 45.355 168.575 ;
        RECT 45.645 167.575 45.975 168.815 ;
        RECT 46.145 167.395 47.035 168.635 ;
        RECT 47.205 167.575 47.535 168.815 ;
        RECT 47.705 167.395 48.595 168.635 ;
        RECT 48.765 167.575 49.095 168.815 ;
        RECT 49.265 167.395 50.155 168.635 ;
        RECT 50.325 167.575 50.655 168.815 ;
        RECT 50.825 167.395 51.395 168.635 ;
        RECT 44.465 167.225 51.395 167.395 ;
        RECT 51.665 167.395 52.555 168.575 ;
        RECT 52.845 168.095 53.175 168.815 ;
        RECT 52.815 167.925 53.175 168.095 ;
        RECT 52.845 167.575 53.175 167.925 ;
        RECT 53.345 167.395 54.235 168.635 ;
        RECT 54.405 167.575 54.735 168.815 ;
        RECT 54.905 167.395 55.795 168.635 ;
        RECT 55.965 167.575 56.295 168.815 ;
        RECT 56.465 167.395 57.355 168.635 ;
        RECT 57.525 167.575 57.855 168.815 ;
        RECT 58.025 167.395 58.595 168.635 ;
        RECT 101.665 168.015 102.140 168.920 ;
        RECT 102.320 168.310 103.765 168.740 ;
        RECT 103.935 168.480 104.300 169.065 ;
        RECT 104.525 168.895 104.725 169.565 ;
        RECT 51.665 167.225 58.595 167.395 ;
        RECT 102.320 167.265 104.290 168.310 ;
        RECT 104.470 167.265 104.725 168.895 ;
        RECT 105.025 169.685 105.230 170.115 ;
        RECT 105.400 170.030 107.650 170.285 ;
        RECT 105.400 169.685 107.125 170.030 ;
        RECT 105.025 169.090 105.195 169.685 ;
        RECT 105.365 169.270 106.155 169.515 ;
        RECT 107.295 169.395 107.660 169.860 ;
        RECT 107.830 169.565 108.085 170.445 ;
        RECT 108.680 170.285 111.010 170.655 ;
        RECT 106.325 169.090 106.915 169.295 ;
        RECT 105.025 168.920 106.915 169.090 ;
        RECT 107.125 169.065 107.715 169.395 ;
        RECT 107.215 168.945 107.660 169.065 ;
        RECT 105.025 168.015 105.500 168.920 ;
        RECT 105.680 168.310 107.125 168.740 ;
        RECT 107.295 168.480 107.660 168.945 ;
        RECT 107.885 168.895 108.085 169.565 ;
        RECT 105.680 167.265 107.650 168.310 ;
        RECT 107.830 167.265 108.085 168.895 ;
        RECT 108.385 169.685 108.590 170.115 ;
        RECT 108.760 170.030 111.010 170.285 ;
        RECT 108.760 169.685 110.485 170.030 ;
        RECT 108.385 169.090 108.555 169.685 ;
        RECT 108.725 169.270 109.515 169.515 ;
        RECT 110.655 169.395 111.020 169.860 ;
        RECT 111.190 169.565 111.445 170.445 ;
        RECT 109.685 169.090 110.275 169.295 ;
        RECT 108.385 168.920 110.275 169.090 ;
        RECT 110.485 169.065 111.075 169.395 ;
        RECT 110.615 168.945 111.020 169.065 ;
        RECT 108.385 168.015 108.860 168.920 ;
        RECT 109.040 168.310 110.485 168.740 ;
        RECT 110.655 168.480 111.020 168.945 ;
        RECT 111.245 168.895 111.445 169.565 ;
        RECT 109.040 167.265 111.010 168.310 ;
        RECT 111.190 168.095 111.445 168.895 ;
        RECT 111.190 167.925 111.465 168.095 ;
        RECT 111.190 167.265 111.445 167.925 ;
        RECT 27.090 166.865 69.810 167.035 ;
        RECT 98.130 166.865 111.570 167.035 ;
        RECT 27.265 164.980 27.740 165.885 ;
        RECT 27.920 165.590 29.890 166.635 ;
        RECT 27.920 165.160 29.365 165.590 ;
        RECT 27.265 164.810 29.155 164.980 ;
        RECT 29.535 164.835 29.900 165.420 ;
        RECT 30.070 165.005 30.325 166.635 ;
        RECT 27.265 164.215 27.435 164.810 ;
        RECT 27.605 164.385 28.395 164.630 ;
        RECT 28.565 164.605 29.155 164.810 ;
        RECT 29.365 164.505 29.955 164.835 ;
        RECT 27.265 163.785 27.470 164.215 ;
        RECT 27.640 163.870 29.365 164.215 ;
        RECT 29.535 164.040 29.900 164.505 ;
        RECT 30.125 164.335 30.325 165.005 ;
        RECT 30.070 164.015 30.325 164.335 ;
        RECT 30.625 164.980 31.100 165.885 ;
        RECT 31.280 165.590 33.250 166.635 ;
        RECT 31.280 165.160 32.725 165.590 ;
        RECT 30.625 164.810 32.515 164.980 ;
        RECT 32.895 164.835 33.260 165.420 ;
        RECT 33.430 165.005 33.685 166.635 ;
        RECT 30.625 164.215 30.795 164.810 ;
        RECT 30.965 164.385 31.755 164.630 ;
        RECT 31.925 164.605 32.515 164.810 ;
        RECT 32.725 164.505 33.315 164.835 ;
        RECT 27.640 163.615 29.890 163.870 ;
        RECT 27.560 163.245 29.890 163.615 ;
        RECT 30.070 163.845 30.375 164.015 ;
        RECT 30.070 163.455 30.325 163.845 ;
        RECT 30.625 163.785 30.830 164.215 ;
        RECT 31.000 163.870 32.725 164.215 ;
        RECT 32.895 164.040 33.260 164.505 ;
        RECT 33.485 164.335 33.685 165.005 ;
        RECT 31.000 163.615 33.250 163.870 ;
        RECT 30.920 163.245 33.250 163.615 ;
        RECT 33.430 163.455 33.685 164.335 ;
        RECT 34.465 164.980 34.940 165.885 ;
        RECT 35.120 165.590 37.090 166.635 ;
        RECT 35.120 165.160 36.565 165.590 ;
        RECT 34.465 164.810 36.355 164.980 ;
        RECT 36.735 164.835 37.100 165.420 ;
        RECT 37.270 165.005 37.525 166.635 ;
        RECT 34.465 164.215 34.635 164.810 ;
        RECT 34.805 164.385 35.595 164.630 ;
        RECT 35.765 164.605 36.355 164.810 ;
        RECT 36.565 164.505 37.155 164.835 ;
        RECT 34.465 163.785 34.670 164.215 ;
        RECT 34.840 163.870 36.565 164.215 ;
        RECT 36.735 164.040 37.100 164.505 ;
        RECT 37.325 164.335 37.525 165.005 ;
        RECT 34.840 163.615 37.090 163.870 ;
        RECT 34.760 163.245 37.090 163.615 ;
        RECT 37.270 163.455 37.525 164.335 ;
        RECT 37.825 164.980 38.300 165.885 ;
        RECT 38.480 165.590 40.450 166.635 ;
        RECT 40.630 166.055 40.885 166.635 ;
        RECT 40.630 165.885 40.915 166.055 ;
        RECT 38.480 165.160 39.925 165.590 ;
        RECT 37.825 164.810 39.715 164.980 ;
        RECT 40.095 164.835 40.460 165.420 ;
        RECT 40.630 165.005 40.885 165.885 ;
        RECT 47.820 165.055 48.410 166.635 ;
        RECT 48.690 165.055 49.075 166.635 ;
        RECT 49.260 165.055 49.850 166.635 ;
        RECT 50.130 165.375 50.515 166.635 ;
        RECT 50.095 165.205 50.515 165.375 ;
        RECT 50.130 165.055 50.515 165.205 ;
        RECT 50.700 165.055 51.290 166.635 ;
        RECT 51.570 165.375 51.955 166.635 ;
        RECT 51.570 165.205 51.965 165.375 ;
        RECT 51.570 165.055 51.955 165.205 ;
        RECT 53.100 165.055 53.690 166.635 ;
        RECT 53.970 165.055 54.355 166.635 ;
        RECT 55.505 166.505 62.435 166.675 ;
        RECT 55.505 165.325 56.395 166.505 ;
        RECT 37.825 164.215 37.995 164.810 ;
        RECT 38.165 164.385 38.955 164.630 ;
        RECT 39.125 164.605 39.715 164.810 ;
        RECT 39.925 164.505 40.515 164.835 ;
        RECT 37.825 163.785 38.030 164.215 ;
        RECT 38.200 163.870 39.925 164.215 ;
        RECT 40.095 164.040 40.460 164.505 ;
        RECT 40.685 164.335 40.885 165.005 ;
        RECT 47.855 164.430 48.565 164.815 ;
        RECT 38.200 163.615 40.450 163.870 ;
        RECT 38.120 163.245 40.450 163.615 ;
        RECT 40.630 163.455 40.885 164.335 ;
        RECT 47.820 163.245 48.410 164.205 ;
        RECT 48.745 163.375 49.075 165.055 ;
        RECT 49.295 164.430 50.005 164.815 ;
        RECT 49.260 163.245 49.850 164.205 ;
        RECT 50.185 163.375 50.515 165.055 ;
        RECT 50.735 164.430 51.445 164.815 ;
        RECT 50.700 163.245 51.290 164.205 ;
        RECT 51.625 163.375 51.955 165.055 ;
        RECT 53.135 164.430 53.845 164.815 ;
        RECT 53.100 163.245 53.690 164.205 ;
        RECT 54.025 163.375 54.355 165.055 ;
        RECT 56.685 165.085 57.015 166.325 ;
        RECT 57.185 165.265 58.075 166.505 ;
        RECT 58.245 165.085 58.575 166.325 ;
        RECT 58.745 165.265 59.635 166.505 ;
        RECT 59.805 165.085 60.135 166.325 ;
        RECT 60.305 165.265 61.195 166.505 ;
        RECT 61.365 165.085 61.695 166.325 ;
        RECT 61.865 165.265 62.435 166.505 ;
        RECT 62.705 166.505 69.635 166.675 ;
        RECT 62.705 165.325 63.595 166.505 ;
        RECT 63.885 165.085 64.215 166.325 ;
        RECT 64.385 165.265 65.275 166.505 ;
        RECT 65.445 165.085 65.775 166.325 ;
        RECT 65.945 165.265 66.835 166.505 ;
        RECT 67.005 165.085 67.335 166.325 ;
        RECT 67.505 165.265 68.395 166.505 ;
        RECT 68.565 165.085 68.895 166.325 ;
        RECT 69.065 165.265 69.635 166.505 ;
        RECT 56.685 164.915 62.520 165.085 ;
        RECT 63.885 164.915 69.720 165.085 ;
        RECT 55.720 164.460 62.170 164.695 ;
        RECT 62.350 164.355 62.520 164.915 ;
        RECT 62.920 164.460 69.370 164.695 ;
        RECT 56.605 164.275 61.635 164.280 ;
        RECT 62.335 164.275 62.520 164.355 ;
        RECT 55.505 163.430 56.395 164.265 ;
        RECT 56.605 164.110 62.520 164.275 ;
        RECT 63.805 164.275 68.835 164.280 ;
        RECT 69.550 164.275 69.720 164.915 ;
        RECT 56.605 163.610 56.815 164.110 ;
        RECT 56.985 163.430 57.995 163.925 ;
        RECT 58.165 163.610 58.375 164.110 ;
        RECT 58.545 163.430 59.555 163.925 ;
        RECT 59.725 163.610 59.935 164.110 ;
        RECT 61.325 164.105 62.520 164.110 ;
        RECT 60.105 163.430 61.155 163.925 ;
        RECT 61.325 163.610 61.975 164.105 ;
        RECT 62.145 163.430 62.515 163.925 ;
        RECT 55.505 163.260 62.515 163.430 ;
        RECT 62.705 163.430 63.595 164.265 ;
        RECT 63.805 164.110 69.720 164.275 ;
        RECT 63.805 163.610 64.015 164.110 ;
        RECT 64.185 163.430 65.195 163.925 ;
        RECT 65.365 163.610 65.575 164.110 ;
        RECT 65.745 163.430 66.755 163.925 ;
        RECT 66.925 163.610 67.135 164.110 ;
        RECT 68.525 164.105 69.720 164.110 ;
        RECT 98.305 164.980 98.780 165.885 ;
        RECT 98.960 165.590 100.930 166.635 ;
        RECT 101.110 166.055 101.365 166.635 ;
        RECT 101.110 165.885 101.435 166.055 ;
        RECT 98.960 165.160 100.405 165.590 ;
        RECT 98.305 164.810 100.195 164.980 ;
        RECT 100.575 164.835 100.940 165.420 ;
        RECT 101.110 165.005 101.365 165.885 ;
        RECT 98.305 164.215 98.475 164.810 ;
        RECT 98.645 164.385 99.435 164.630 ;
        RECT 99.605 164.605 100.195 164.810 ;
        RECT 100.405 164.505 100.995 164.835 ;
        RECT 67.305 163.430 68.355 163.925 ;
        RECT 68.525 163.610 69.175 164.105 ;
        RECT 69.345 163.430 69.715 163.925 ;
        RECT 98.305 163.785 98.510 164.215 ;
        RECT 98.680 163.870 100.405 164.215 ;
        RECT 100.575 164.040 100.940 164.505 ;
        RECT 101.165 164.335 101.365 165.005 ;
        RECT 98.680 163.615 100.930 163.870 ;
        RECT 62.705 163.260 69.715 163.430 ;
        RECT 98.600 163.245 100.930 163.615 ;
        RECT 101.110 163.455 101.365 164.335 ;
        RECT 101.665 164.980 102.140 165.885 ;
        RECT 102.320 165.590 104.290 166.635 ;
        RECT 102.320 165.160 103.765 165.590 ;
        RECT 101.665 164.810 103.555 164.980 ;
        RECT 103.935 164.835 104.300 165.420 ;
        RECT 104.470 165.005 104.725 166.635 ;
        RECT 101.665 164.215 101.835 164.810 ;
        RECT 102.005 164.385 102.795 164.630 ;
        RECT 102.965 164.605 103.555 164.810 ;
        RECT 103.765 164.505 104.355 164.835 ;
        RECT 101.665 163.785 101.870 164.215 ;
        RECT 102.040 163.870 103.765 164.215 ;
        RECT 103.935 164.040 104.300 164.505 ;
        RECT 104.525 164.335 104.725 165.005 ;
        RECT 102.040 163.615 104.290 163.870 ;
        RECT 101.960 163.245 104.290 163.615 ;
        RECT 104.470 163.455 104.725 164.335 ;
        RECT 105.025 164.980 105.500 165.885 ;
        RECT 105.680 165.590 107.650 166.635 ;
        RECT 105.680 165.160 107.125 165.590 ;
        RECT 105.025 164.810 106.915 164.980 ;
        RECT 107.295 164.835 107.660 165.420 ;
        RECT 107.830 165.005 108.085 166.635 ;
        RECT 105.025 164.215 105.195 164.810 ;
        RECT 105.365 164.385 106.155 164.630 ;
        RECT 106.325 164.605 106.915 164.810 ;
        RECT 107.125 164.505 107.715 164.835 ;
        RECT 105.025 163.785 105.230 164.215 ;
        RECT 105.400 163.870 107.125 164.215 ;
        RECT 107.295 164.040 107.660 164.505 ;
        RECT 107.885 164.335 108.085 165.005 ;
        RECT 105.400 163.615 107.650 163.870 ;
        RECT 105.320 163.245 107.650 163.615 ;
        RECT 107.830 163.455 108.085 164.335 ;
        RECT 108.385 164.980 108.860 165.885 ;
        RECT 109.040 165.590 111.010 166.635 ;
        RECT 109.040 165.160 110.485 165.590 ;
        RECT 108.385 164.810 110.275 164.980 ;
        RECT 110.655 164.835 111.020 165.420 ;
        RECT 111.190 165.005 111.445 166.635 ;
        RECT 108.385 164.215 108.555 164.810 ;
        RECT 108.725 164.385 109.515 164.630 ;
        RECT 109.685 164.605 110.275 164.810 ;
        RECT 110.485 164.505 111.075 164.835 ;
        RECT 108.385 163.785 108.590 164.215 ;
        RECT 108.760 163.870 110.485 164.215 ;
        RECT 110.655 164.040 111.020 164.505 ;
        RECT 111.245 164.335 111.445 165.005 ;
        RECT 111.190 164.015 111.445 164.335 ;
        RECT 108.760 163.615 111.010 163.870 ;
        RECT 108.680 163.245 111.010 163.615 ;
        RECT 111.190 163.845 111.465 164.015 ;
        RECT 111.190 163.455 111.445 163.845 ;
        RECT 27.090 162.795 46.770 162.965 ;
        RECT 47.730 162.795 52.050 162.965 ;
        RECT 53.010 162.795 54.450 162.965 ;
        RECT 54.930 162.795 69.810 162.965 ;
        RECT 98.130 162.795 113.970 162.965 ;
        RECT 27.560 162.145 29.890 162.515 ;
        RECT 27.265 161.545 27.470 161.975 ;
        RECT 27.640 161.890 29.890 162.145 ;
        RECT 27.640 161.545 29.365 161.890 ;
        RECT 27.265 160.950 27.435 161.545 ;
        RECT 27.605 161.130 28.395 161.375 ;
        RECT 29.535 161.255 29.900 161.720 ;
        RECT 30.070 161.425 30.325 162.305 ;
        RECT 30.920 162.145 33.250 162.515 ;
        RECT 27.655 161.125 27.825 161.130 ;
        RECT 28.565 160.950 29.155 161.155 ;
        RECT 27.265 160.780 29.155 160.950 ;
        RECT 29.365 160.925 29.955 161.255 ;
        RECT 27.265 159.875 27.740 160.780 ;
        RECT 27.920 160.170 29.365 160.600 ;
        RECT 29.535 160.340 29.900 160.925 ;
        RECT 30.125 160.755 30.325 161.425 ;
        RECT 27.920 159.125 29.890 160.170 ;
        RECT 30.070 159.935 30.325 160.755 ;
        RECT 30.625 161.545 30.830 161.975 ;
        RECT 31.000 161.890 33.250 162.145 ;
        RECT 31.000 161.545 32.725 161.890 ;
        RECT 30.625 160.950 30.795 161.545 ;
        RECT 30.965 161.130 31.755 161.375 ;
        RECT 32.895 161.295 33.260 161.720 ;
        RECT 33.430 161.425 33.685 162.305 ;
        RECT 34.280 162.145 36.610 162.515 ;
        RECT 39.665 162.330 46.675 162.500 ;
        RECT 32.895 161.255 33.265 161.295 ;
        RECT 31.055 161.125 31.225 161.130 ;
        RECT 31.925 160.950 32.515 161.155 ;
        RECT 30.625 160.780 32.515 160.950 ;
        RECT 32.725 160.925 33.315 161.255 ;
        RECT 30.070 159.765 30.375 159.935 ;
        RECT 30.625 159.875 31.100 160.780 ;
        RECT 31.280 160.170 32.725 160.600 ;
        RECT 32.895 160.340 33.260 160.925 ;
        RECT 33.485 160.755 33.685 161.425 ;
        RECT 30.070 159.125 30.325 159.765 ;
        RECT 31.280 159.125 33.250 160.170 ;
        RECT 33.430 159.125 33.685 160.755 ;
        RECT 33.985 161.545 34.190 161.975 ;
        RECT 34.360 161.890 36.610 162.145 ;
        RECT 34.360 161.545 36.085 161.890 ;
        RECT 33.985 160.950 34.155 161.545 ;
        RECT 34.325 161.130 35.115 161.375 ;
        RECT 36.255 161.295 36.620 161.720 ;
        RECT 36.790 161.425 37.045 162.305 ;
        RECT 39.665 161.495 40.555 162.330 ;
        RECT 40.765 161.650 40.975 162.150 ;
        RECT 41.145 161.835 42.155 162.330 ;
        RECT 42.325 161.650 42.535 162.150 ;
        RECT 42.705 161.835 43.715 162.330 ;
        RECT 43.885 161.650 44.095 162.150 ;
        RECT 44.265 161.835 45.315 162.330 ;
        RECT 45.485 161.655 46.135 162.150 ;
        RECT 46.305 161.835 46.675 162.330 ;
        RECT 45.485 161.650 46.680 161.655 ;
        RECT 40.765 161.485 46.680 161.650 ;
        RECT 50.220 161.555 50.810 162.515 ;
        RECT 51.145 161.975 51.475 162.385 ;
        RECT 51.115 161.805 51.475 161.975 ;
        RECT 40.765 161.480 45.795 161.485 ;
        RECT 36.155 161.255 36.620 161.295 ;
        RECT 34.455 161.125 34.625 161.130 ;
        RECT 35.285 160.950 35.875 161.155 ;
        RECT 33.985 160.780 35.875 160.950 ;
        RECT 36.085 160.925 36.675 161.255 ;
        RECT 33.985 159.875 34.460 160.780 ;
        RECT 34.640 160.170 36.085 160.600 ;
        RECT 36.255 160.340 36.620 160.925 ;
        RECT 36.845 160.755 37.045 161.425 ;
        RECT 39.880 161.065 46.330 161.300 ;
        RECT 46.510 160.845 46.680 161.485 ;
        RECT 50.255 160.945 50.965 161.330 ;
        RECT 34.640 159.125 36.610 160.170 ;
        RECT 36.790 159.125 37.045 160.755 ;
        RECT 40.845 160.675 46.680 160.845 ;
        RECT 51.145 160.705 51.475 161.805 ;
        RECT 55.025 162.330 62.035 162.500 ;
        RECT 55.025 161.495 55.915 162.330 ;
        RECT 56.125 161.650 56.335 162.150 ;
        RECT 56.505 161.835 57.515 162.330 ;
        RECT 57.685 161.650 57.895 162.150 ;
        RECT 58.065 161.835 59.075 162.330 ;
        RECT 59.245 161.650 59.455 162.150 ;
        RECT 59.625 161.835 60.675 162.330 ;
        RECT 60.845 161.655 61.495 162.150 ;
        RECT 61.665 161.835 62.035 162.330 ;
        RECT 104.360 162.145 106.690 162.515 ;
        RECT 60.845 161.650 62.040 161.655 ;
        RECT 56.125 161.485 62.040 161.650 ;
        RECT 56.125 161.480 61.155 161.485 ;
        RECT 55.240 161.065 61.690 161.300 ;
        RECT 61.870 160.845 62.040 161.485 ;
        RECT 39.665 159.255 40.555 160.435 ;
        RECT 40.845 159.435 41.175 160.675 ;
        RECT 41.345 159.255 42.235 160.495 ;
        RECT 42.405 159.435 42.735 160.675 ;
        RECT 42.905 159.255 43.795 160.495 ;
        RECT 43.965 159.435 44.295 160.675 ;
        RECT 44.465 159.255 45.355 160.495 ;
        RECT 45.525 159.435 45.855 160.675 ;
        RECT 46.025 159.255 46.595 160.495 ;
        RECT 39.665 159.085 46.595 159.255 ;
        RECT 50.220 159.125 50.810 160.705 ;
        RECT 51.090 159.125 51.475 160.705 ;
        RECT 56.205 160.675 62.040 160.845 ;
        RECT 104.065 161.545 104.270 161.975 ;
        RECT 104.440 161.890 106.690 162.145 ;
        RECT 104.440 161.545 106.165 161.890 ;
        RECT 104.065 160.950 104.235 161.545 ;
        RECT 104.405 161.130 105.195 161.375 ;
        RECT 106.335 161.295 106.700 161.720 ;
        RECT 106.870 161.425 107.125 162.305 ;
        RECT 107.720 162.145 110.050 162.515 ;
        RECT 106.335 161.255 106.705 161.295 ;
        RECT 104.835 161.125 105.005 161.130 ;
        RECT 105.365 160.950 105.955 161.155 ;
        RECT 104.065 160.780 105.955 160.950 ;
        RECT 106.165 160.925 106.755 161.255 ;
        RECT 55.025 159.255 55.915 160.435 ;
        RECT 56.205 159.435 56.535 160.675 ;
        RECT 56.705 159.255 57.595 160.495 ;
        RECT 57.765 159.435 58.095 160.675 ;
        RECT 58.265 159.255 59.155 160.495 ;
        RECT 59.325 159.435 59.655 160.675 ;
        RECT 59.825 159.255 60.715 160.495 ;
        RECT 60.885 159.435 61.215 160.675 ;
        RECT 61.385 159.255 61.955 160.495 ;
        RECT 104.065 159.875 104.540 160.780 ;
        RECT 104.720 160.170 106.165 160.600 ;
        RECT 106.335 160.340 106.700 160.925 ;
        RECT 106.925 160.755 107.125 161.425 ;
        RECT 55.025 159.085 61.955 159.255 ;
        RECT 104.720 159.125 106.690 160.170 ;
        RECT 106.870 159.125 107.125 160.755 ;
        RECT 107.425 161.545 107.630 161.975 ;
        RECT 107.800 161.890 110.050 162.145 ;
        RECT 107.800 161.545 109.525 161.890 ;
        RECT 107.425 160.950 107.595 161.545 ;
        RECT 107.765 161.130 108.555 161.375 ;
        RECT 109.695 161.295 110.060 161.720 ;
        RECT 110.230 161.425 110.485 162.305 ;
        RECT 111.080 162.145 113.410 162.515 ;
        RECT 109.595 161.255 110.060 161.295 ;
        RECT 107.895 161.125 108.065 161.130 ;
        RECT 108.725 160.950 109.315 161.155 ;
        RECT 107.425 160.780 109.315 160.950 ;
        RECT 109.525 160.925 110.115 161.255 ;
        RECT 107.425 159.875 107.900 160.780 ;
        RECT 108.080 160.170 109.525 160.600 ;
        RECT 109.695 160.340 110.060 160.925 ;
        RECT 110.285 160.755 110.485 161.425 ;
        RECT 108.080 159.125 110.050 160.170 ;
        RECT 110.230 159.125 110.485 160.755 ;
        RECT 110.785 161.545 110.990 161.975 ;
        RECT 111.160 161.890 113.410 162.145 ;
        RECT 111.160 161.545 112.885 161.890 ;
        RECT 110.785 160.950 110.955 161.545 ;
        RECT 111.125 161.130 111.915 161.375 ;
        RECT 113.055 161.255 113.420 161.720 ;
        RECT 113.590 161.425 113.845 162.305 ;
        RECT 111.295 161.125 111.465 161.130 ;
        RECT 112.085 160.950 112.675 161.155 ;
        RECT 110.785 160.780 112.675 160.950 ;
        RECT 112.885 160.925 113.475 161.255 ;
        RECT 112.995 160.785 113.420 160.925 ;
        RECT 110.785 159.875 111.260 160.780 ;
        RECT 111.440 160.170 112.885 160.600 ;
        RECT 113.055 160.340 113.420 160.785 ;
        RECT 113.645 160.755 113.845 161.425 ;
        RECT 111.440 159.125 113.410 160.170 ;
        RECT 113.590 159.125 113.845 160.755 ;
        RECT 27.090 158.725 39.090 158.895 ;
        RECT 39.570 158.725 54.450 158.895 ;
        RECT 54.930 158.725 68.370 158.895 ;
        RECT 102.930 158.725 113.970 158.895 ;
        RECT 27.265 156.840 27.740 157.745 ;
        RECT 27.920 157.450 29.890 158.495 ;
        RECT 27.920 157.020 29.365 157.450 ;
        RECT 27.265 156.670 29.155 156.840 ;
        RECT 29.535 156.695 29.900 157.280 ;
        RECT 30.070 156.865 30.325 158.495 ;
        RECT 27.265 156.075 27.435 156.670 ;
        RECT 27.605 156.245 28.395 156.490 ;
        RECT 28.565 156.465 29.155 156.670 ;
        RECT 29.365 156.365 29.955 156.695 ;
        RECT 27.265 155.645 27.470 156.075 ;
        RECT 27.640 155.730 29.365 156.075 ;
        RECT 29.535 155.900 29.900 156.365 ;
        RECT 30.125 156.195 30.325 156.865 ;
        RECT 30.070 155.855 30.325 156.195 ;
        RECT 30.625 156.840 31.100 157.745 ;
        RECT 31.280 157.450 33.250 158.495 ;
        RECT 31.280 157.020 32.725 157.450 ;
        RECT 30.625 156.670 32.515 156.840 ;
        RECT 32.895 156.695 33.260 157.280 ;
        RECT 33.430 156.865 33.685 158.495 ;
        RECT 30.625 156.075 30.795 156.670 ;
        RECT 30.965 156.245 31.755 156.490 ;
        RECT 31.925 156.465 32.515 156.670 ;
        RECT 32.725 156.365 33.315 156.695 ;
        RECT 27.640 155.475 29.890 155.730 ;
        RECT 27.560 155.105 29.890 155.475 ;
        RECT 30.070 155.685 30.375 155.855 ;
        RECT 30.070 155.315 30.325 155.685 ;
        RECT 30.625 155.645 30.830 156.075 ;
        RECT 31.000 155.730 32.725 156.075 ;
        RECT 32.895 155.900 33.260 156.365 ;
        RECT 33.485 156.195 33.685 156.865 ;
        RECT 31.000 155.475 33.250 155.730 ;
        RECT 30.920 155.105 33.250 155.475 ;
        RECT 33.430 155.315 33.685 156.195 ;
        RECT 35.905 156.840 36.380 157.745 ;
        RECT 36.560 157.450 38.530 158.495 ;
        RECT 36.560 157.020 38.005 157.450 ;
        RECT 35.905 156.670 37.795 156.840 ;
        RECT 38.175 156.695 38.540 157.280 ;
        RECT 38.710 156.865 38.965 158.495 ;
        RECT 40.145 158.365 47.075 158.535 ;
        RECT 40.145 157.185 41.035 158.365 ;
        RECT 35.905 156.075 36.075 156.670 ;
        RECT 36.245 156.245 37.035 156.490 ;
        RECT 37.205 156.465 37.795 156.670 ;
        RECT 38.005 156.365 38.595 156.695 ;
        RECT 38.765 156.535 38.965 156.865 ;
        RECT 41.325 156.945 41.655 158.185 ;
        RECT 41.825 157.125 42.715 158.365 ;
        RECT 42.885 156.945 43.215 158.185 ;
        RECT 43.385 157.125 44.275 158.365 ;
        RECT 44.445 156.945 44.775 158.185 ;
        RECT 44.945 157.125 45.835 158.365 ;
        RECT 46.005 156.945 46.335 158.185 ;
        RECT 46.505 157.125 47.075 158.365 ;
        RECT 47.345 158.365 54.275 158.535 ;
        RECT 47.345 157.185 48.235 158.365 ;
        RECT 48.525 156.945 48.855 158.185 ;
        RECT 49.025 157.125 49.915 158.365 ;
        RECT 50.085 156.945 50.415 158.185 ;
        RECT 50.585 157.125 51.475 158.365 ;
        RECT 51.645 156.945 51.975 158.185 ;
        RECT 52.145 157.125 53.035 158.365 ;
        RECT 53.205 156.945 53.535 158.185 ;
        RECT 53.705 157.125 54.275 158.365 ;
        RECT 61.265 158.365 68.195 158.535 ;
        RECT 61.265 157.185 62.155 158.365 ;
        RECT 62.445 156.945 62.775 158.185 ;
        RECT 62.945 157.125 63.835 158.365 ;
        RECT 64.005 156.945 64.335 158.185 ;
        RECT 64.505 157.125 65.395 158.365 ;
        RECT 65.565 156.945 65.895 158.185 ;
        RECT 66.065 157.125 66.955 158.365 ;
        RECT 67.125 156.945 67.455 158.185 ;
        RECT 67.625 157.125 68.195 158.365 ;
        RECT 41.325 156.775 47.160 156.945 ;
        RECT 48.525 156.775 54.360 156.945 ;
        RECT 62.445 156.775 68.280 156.945 ;
        RECT 38.765 156.365 39.045 156.535 ;
        RECT 35.905 155.645 36.110 156.075 ;
        RECT 36.280 155.730 38.005 156.075 ;
        RECT 38.175 155.900 38.540 156.365 ;
        RECT 38.765 156.195 38.965 156.365 ;
        RECT 40.360 156.320 46.810 156.555 ;
        RECT 46.990 156.535 47.160 156.775 ;
        RECT 46.990 156.365 47.205 156.535 ;
        RECT 36.280 155.475 38.530 155.730 ;
        RECT 36.200 155.105 38.530 155.475 ;
        RECT 38.710 155.315 38.965 156.195 ;
        RECT 41.245 156.135 46.275 156.140 ;
        RECT 46.990 156.135 47.160 156.365 ;
        RECT 47.560 156.320 54.010 156.555 ;
        RECT 40.145 155.290 41.035 156.125 ;
        RECT 41.245 155.970 47.160 156.135 ;
        RECT 48.445 156.135 53.475 156.140 ;
        RECT 54.190 156.135 54.360 156.775 ;
        RECT 61.480 156.320 67.930 156.555 ;
        RECT 41.245 155.470 41.455 155.970 ;
        RECT 41.625 155.290 42.635 155.785 ;
        RECT 42.805 155.470 43.015 155.970 ;
        RECT 43.185 155.290 44.195 155.785 ;
        RECT 44.365 155.470 44.575 155.970 ;
        RECT 45.965 155.965 47.160 155.970 ;
        RECT 44.745 155.290 45.795 155.785 ;
        RECT 45.965 155.470 46.615 155.965 ;
        RECT 46.785 155.290 47.155 155.785 ;
        RECT 40.145 155.120 47.155 155.290 ;
        RECT 47.345 155.290 48.235 156.125 ;
        RECT 48.445 155.970 54.360 156.135 ;
        RECT 62.365 156.135 67.395 156.140 ;
        RECT 68.110 156.135 68.280 156.775 ;
        RECT 48.445 155.470 48.655 155.970 ;
        RECT 48.825 155.290 49.835 155.785 ;
        RECT 50.005 155.470 50.215 155.970 ;
        RECT 50.385 155.290 51.395 155.785 ;
        RECT 51.565 155.470 51.775 155.970 ;
        RECT 53.165 155.965 54.360 155.970 ;
        RECT 51.945 155.290 52.995 155.785 ;
        RECT 53.165 155.470 53.815 155.965 ;
        RECT 53.985 155.290 54.355 155.785 ;
        RECT 47.345 155.120 54.355 155.290 ;
        RECT 61.265 155.290 62.155 156.125 ;
        RECT 62.365 155.970 68.280 156.135 ;
        RECT 62.365 155.470 62.575 155.970 ;
        RECT 62.745 155.290 63.755 155.785 ;
        RECT 63.925 155.470 64.135 155.970 ;
        RECT 64.305 155.290 65.315 155.785 ;
        RECT 65.485 155.470 65.695 155.970 ;
        RECT 67.085 155.965 68.280 155.970 ;
        RECT 103.105 156.840 103.580 157.745 ;
        RECT 103.760 157.450 105.730 158.495 ;
        RECT 103.760 157.020 105.205 157.450 ;
        RECT 103.105 156.670 104.995 156.840 ;
        RECT 105.375 156.695 105.740 157.280 ;
        RECT 105.910 156.875 106.165 158.495 ;
        RECT 105.910 156.865 106.195 156.875 ;
        RECT 105.965 156.705 106.195 156.865 ;
        RECT 106.465 156.840 106.940 157.745 ;
        RECT 107.120 157.450 109.090 158.495 ;
        RECT 107.120 157.020 108.565 157.450 ;
        RECT 103.105 156.075 103.275 156.670 ;
        RECT 103.445 156.245 104.235 156.490 ;
        RECT 104.405 156.465 104.995 156.670 ;
        RECT 105.205 156.365 105.795 156.695 ;
        RECT 65.865 155.290 66.915 155.785 ;
        RECT 67.085 155.470 67.735 155.965 ;
        RECT 67.905 155.290 68.275 155.785 ;
        RECT 103.105 155.645 103.310 156.075 ;
        RECT 103.480 155.730 105.205 156.075 ;
        RECT 105.375 155.900 105.740 156.365 ;
        RECT 105.965 156.195 106.165 156.705 ;
        RECT 103.480 155.475 105.730 155.730 ;
        RECT 61.265 155.120 68.275 155.290 ;
        RECT 103.400 155.105 105.730 155.475 ;
        RECT 105.910 155.315 106.165 156.195 ;
        RECT 106.465 156.670 108.355 156.840 ;
        RECT 108.735 156.695 109.100 157.280 ;
        RECT 109.270 156.865 109.525 158.495 ;
        RECT 106.465 156.075 106.635 156.670 ;
        RECT 106.805 156.245 107.595 156.490 ;
        RECT 107.765 156.465 108.355 156.670 ;
        RECT 108.565 156.365 109.155 156.695 ;
        RECT 106.465 155.645 106.670 156.075 ;
        RECT 106.840 155.730 108.565 156.075 ;
        RECT 108.735 155.900 109.100 156.365 ;
        RECT 109.325 156.195 109.525 156.865 ;
        RECT 109.270 155.855 109.525 156.195 ;
        RECT 109.825 156.840 110.300 157.745 ;
        RECT 110.480 157.450 112.450 158.495 ;
        RECT 110.480 157.020 111.925 157.450 ;
        RECT 109.825 156.670 111.715 156.840 ;
        RECT 112.095 156.695 112.460 157.280 ;
        RECT 112.630 156.865 112.885 158.495 ;
        RECT 109.825 156.075 109.995 156.670 ;
        RECT 110.165 156.245 110.955 156.490 ;
        RECT 111.125 156.465 111.715 156.670 ;
        RECT 111.925 156.365 112.515 156.695 ;
        RECT 106.840 155.475 109.090 155.730 ;
        RECT 106.760 155.105 109.090 155.475 ;
        RECT 109.270 155.685 109.595 155.855 ;
        RECT 109.270 155.315 109.525 155.685 ;
        RECT 109.825 155.645 110.030 156.075 ;
        RECT 110.200 155.730 111.925 156.075 ;
        RECT 112.095 155.900 112.460 156.365 ;
        RECT 112.685 156.195 112.885 156.865 ;
        RECT 110.200 155.475 112.450 155.730 ;
        RECT 110.120 155.105 112.450 155.475 ;
        RECT 112.630 155.315 112.885 156.195 ;
        RECT 27.090 154.655 39.090 154.825 ;
        RECT 40.050 154.655 56.370 154.825 ;
        RECT 59.250 154.655 68.370 154.825 ;
        RECT 102.930 154.655 113.010 154.825 ;
        RECT 27.560 154.005 29.890 154.375 ;
        RECT 27.265 153.405 27.470 153.835 ;
        RECT 27.640 153.750 29.890 154.005 ;
        RECT 27.640 153.405 29.365 153.750 ;
        RECT 27.265 152.810 27.435 153.405 ;
        RECT 27.605 152.990 28.395 153.235 ;
        RECT 29.535 153.115 29.900 153.580 ;
        RECT 30.070 153.285 30.325 154.165 ;
        RECT 31.880 154.005 34.210 154.375 ;
        RECT 28.565 152.810 29.155 153.015 ;
        RECT 27.265 152.640 29.155 152.810 ;
        RECT 29.365 152.785 29.955 153.115 ;
        RECT 27.265 151.735 27.740 152.640 ;
        RECT 27.920 152.030 29.365 152.460 ;
        RECT 29.535 152.200 29.900 152.785 ;
        RECT 30.125 152.615 30.325 153.285 ;
        RECT 31.055 152.625 31.225 153.475 ;
        RECT 31.585 153.405 31.790 153.835 ;
        RECT 31.960 153.750 34.210 154.005 ;
        RECT 31.960 153.405 33.685 153.750 ;
        RECT 31.585 152.810 31.755 153.405 ;
        RECT 31.925 152.990 32.715 153.235 ;
        RECT 33.855 153.115 34.220 153.580 ;
        RECT 34.390 153.285 34.645 154.165 ;
        RECT 35.240 154.005 37.570 154.375 ;
        RECT 49.265 154.190 56.275 154.360 ;
        RECT 32.885 152.810 33.475 153.015 ;
        RECT 31.585 152.640 33.475 152.810 ;
        RECT 33.685 152.785 34.275 153.115 ;
        RECT 27.920 150.985 29.890 152.030 ;
        RECT 30.070 151.775 30.325 152.615 ;
        RECT 30.070 151.605 30.375 151.775 ;
        RECT 31.585 151.735 32.060 152.640 ;
        RECT 33.775 152.625 34.220 152.785 ;
        RECT 32.240 152.030 33.685 152.460 ;
        RECT 33.855 152.200 34.220 152.625 ;
        RECT 34.445 152.615 34.645 153.285 ;
        RECT 30.070 150.985 30.325 151.605 ;
        RECT 32.240 150.985 34.210 152.030 ;
        RECT 34.390 150.985 34.645 152.615 ;
        RECT 34.945 153.405 35.150 153.835 ;
        RECT 35.320 153.750 37.570 154.005 ;
        RECT 35.320 153.405 37.045 153.750 ;
        RECT 34.945 152.810 35.115 153.405 ;
        RECT 35.285 152.990 36.075 153.235 ;
        RECT 37.215 153.115 37.580 153.580 ;
        RECT 37.750 153.285 38.005 154.165 ;
        RECT 49.265 153.355 50.155 154.190 ;
        RECT 50.365 153.510 50.575 154.010 ;
        RECT 50.745 153.695 51.755 154.190 ;
        RECT 51.925 153.510 52.135 154.010 ;
        RECT 52.305 153.695 53.315 154.190 ;
        RECT 53.485 153.510 53.695 154.010 ;
        RECT 53.865 153.695 54.915 154.190 ;
        RECT 55.085 153.515 55.735 154.010 ;
        RECT 55.905 153.695 56.275 154.190 ;
        RECT 59.345 154.190 66.355 154.360 ;
        RECT 55.085 153.510 56.280 153.515 ;
        RECT 50.365 153.345 56.280 153.510 ;
        RECT 59.345 153.355 60.235 154.190 ;
        RECT 60.445 153.510 60.655 154.010 ;
        RECT 60.825 153.695 61.835 154.190 ;
        RECT 62.005 153.510 62.215 154.010 ;
        RECT 62.385 153.695 63.395 154.190 ;
        RECT 63.565 153.510 63.775 154.010 ;
        RECT 63.945 153.695 64.995 154.190 ;
        RECT 65.165 153.515 65.815 154.010 ;
        RECT 65.985 153.695 66.355 154.190 ;
        RECT 105.320 154.005 107.650 154.375 ;
        RECT 65.165 153.510 66.360 153.515 ;
        RECT 50.365 153.340 55.395 153.345 ;
        RECT 36.245 152.810 36.835 153.015 ;
        RECT 34.945 152.640 36.835 152.810 ;
        RECT 37.045 152.785 37.635 153.115 ;
        RECT 34.945 151.735 35.420 152.640 ;
        RECT 37.175 152.625 37.580 152.785 ;
        RECT 35.600 152.030 37.045 152.460 ;
        RECT 37.215 152.200 37.580 152.625 ;
        RECT 37.805 152.615 38.005 153.285 ;
        RECT 49.480 152.925 55.930 153.160 ;
        RECT 56.110 152.705 56.280 153.345 ;
        RECT 60.445 153.345 66.360 153.510 ;
        RECT 60.445 153.340 65.475 153.345 ;
        RECT 37.750 152.455 38.005 152.615 ;
        RECT 50.445 152.535 56.280 152.705 ;
        RECT 37.750 152.285 38.025 152.455 ;
        RECT 35.600 150.985 37.570 152.030 ;
        RECT 37.750 150.985 38.005 152.285 ;
        RECT 49.265 151.115 50.155 152.295 ;
        RECT 50.445 151.295 50.775 152.535 ;
        RECT 50.945 151.115 51.835 152.355 ;
        RECT 52.005 151.295 52.335 152.535 ;
        RECT 52.505 151.115 53.395 152.355 ;
        RECT 53.565 151.295 53.895 152.535 ;
        RECT 54.065 151.115 54.955 152.355 ;
        RECT 55.125 151.295 55.455 152.535 ;
        RECT 55.625 151.115 56.195 152.355 ;
        RECT 49.265 150.945 56.195 151.115 ;
        RECT 24.690 150.585 38.130 150.755 ;
        RECT 49.170 150.585 56.850 150.755 ;
        RECT 24.865 148.700 25.340 149.605 ;
        RECT 25.520 149.310 27.490 150.355 ;
        RECT 25.520 148.880 26.965 149.310 ;
        RECT 24.865 148.530 26.755 148.700 ;
        RECT 27.135 148.555 27.500 149.140 ;
        RECT 27.670 148.725 27.925 150.355 ;
        RECT 27.725 148.715 27.925 148.725 ;
        RECT 24.865 147.935 25.035 148.530 ;
        RECT 25.205 148.105 25.995 148.350 ;
        RECT 26.165 148.325 26.755 148.530 ;
        RECT 26.965 148.225 27.555 148.555 ;
        RECT 27.725 148.545 27.995 148.715 ;
        RECT 28.225 148.700 28.700 149.605 ;
        RECT 28.880 149.310 30.850 150.355 ;
        RECT 28.880 148.880 30.325 149.310 ;
        RECT 24.865 147.505 25.070 147.935 ;
        RECT 25.240 147.590 26.965 147.935 ;
        RECT 27.135 147.760 27.500 148.225 ;
        RECT 27.725 148.055 27.925 148.545 ;
        RECT 25.240 147.335 27.490 147.590 ;
        RECT 25.160 146.965 27.490 147.335 ;
        RECT 27.670 147.175 27.925 148.055 ;
        RECT 28.225 148.530 30.115 148.700 ;
        RECT 30.495 148.555 30.860 149.140 ;
        RECT 31.030 148.725 31.285 150.355 ;
        RECT 28.225 147.935 28.395 148.530 ;
        RECT 28.565 148.105 29.355 148.350 ;
        RECT 29.525 148.325 30.115 148.530 ;
        RECT 30.325 148.225 30.915 148.555 ;
        RECT 30.375 148.205 30.860 148.225 ;
        RECT 28.225 147.505 28.430 147.935 ;
        RECT 28.600 147.590 30.325 147.935 ;
        RECT 30.495 147.760 30.860 148.205 ;
        RECT 31.085 148.055 31.285 148.725 ;
        RECT 28.600 147.335 30.850 147.590 ;
        RECT 28.520 146.965 30.850 147.335 ;
        RECT 31.030 147.175 31.285 148.055 ;
        RECT 31.585 148.700 32.060 149.605 ;
        RECT 32.240 149.310 34.210 150.355 ;
        RECT 32.240 148.880 33.685 149.310 ;
        RECT 33.855 148.715 34.220 149.140 ;
        RECT 34.390 148.725 34.645 150.355 ;
        RECT 49.745 150.225 56.675 150.395 ;
        RECT 49.745 149.045 50.635 150.225 ;
        RECT 31.585 148.530 33.475 148.700 ;
        RECT 33.775 148.555 34.220 148.715 ;
        RECT 31.585 147.935 31.755 148.530 ;
        RECT 31.925 148.105 32.715 148.350 ;
        RECT 32.885 148.325 33.475 148.530 ;
        RECT 33.685 148.225 34.275 148.555 ;
        RECT 31.585 147.505 31.790 147.935 ;
        RECT 31.960 147.590 33.685 147.935 ;
        RECT 33.855 147.760 34.220 148.225 ;
        RECT 34.445 148.055 34.645 148.725 ;
        RECT 50.925 148.805 51.255 150.045 ;
        RECT 51.425 148.985 52.315 150.225 ;
        RECT 52.485 148.805 52.815 150.045 ;
        RECT 52.985 148.985 53.875 150.225 ;
        RECT 54.045 148.805 54.375 150.045 ;
        RECT 54.545 148.985 55.435 150.225 ;
        RECT 55.605 148.805 55.935 150.045 ;
        RECT 56.105 148.985 56.675 150.225 ;
        RECT 50.925 148.635 56.760 148.805 ;
        RECT 56.555 148.545 56.760 148.635 ;
        RECT 57.235 148.545 57.405 153.135 ;
        RECT 59.560 152.925 66.010 153.160 ;
        RECT 66.190 152.705 66.360 153.345 ;
        RECT 105.025 153.405 105.230 153.835 ;
        RECT 105.400 153.750 107.650 154.005 ;
        RECT 105.400 153.405 107.125 153.750 ;
        RECT 60.525 152.535 66.360 152.705 ;
        RECT 59.345 151.115 60.235 152.295 ;
        RECT 60.525 151.295 60.855 152.535 ;
        RECT 61.025 151.115 61.915 152.355 ;
        RECT 62.085 151.295 62.415 152.535 ;
        RECT 62.585 151.115 63.475 152.355 ;
        RECT 63.645 151.295 63.975 152.535 ;
        RECT 64.145 151.115 65.035 152.355 ;
        RECT 65.205 151.295 65.535 152.535 ;
        RECT 65.705 151.115 66.275 152.355 ;
        RECT 59.345 150.945 66.275 151.115 ;
        RECT 58.770 150.585 66.450 150.755 ;
        RECT 58.865 150.225 65.795 150.395 ;
        RECT 58.865 149.045 59.755 150.225 ;
        RECT 60.045 148.805 60.375 150.045 ;
        RECT 60.545 148.985 61.435 150.225 ;
        RECT 61.605 148.805 61.935 150.045 ;
        RECT 62.105 148.985 62.995 150.225 ;
        RECT 63.165 148.805 63.495 150.045 ;
        RECT 63.665 148.985 64.555 150.225 ;
        RECT 64.725 148.805 65.055 150.045 ;
        RECT 65.225 148.985 65.795 150.225 ;
        RECT 60.045 148.715 65.880 148.805 ;
        RECT 60.045 148.635 65.905 148.715 ;
        RECT 65.710 148.545 65.905 148.635 ;
        RECT 66.755 148.545 66.925 153.135 ;
        RECT 105.025 152.810 105.195 153.405 ;
        RECT 105.365 152.990 106.155 153.235 ;
        RECT 107.295 153.115 107.660 153.580 ;
        RECT 107.830 153.285 108.085 154.165 ;
        RECT 108.680 154.005 111.010 154.375 ;
        RECT 106.325 152.810 106.915 153.015 ;
        RECT 105.025 152.640 106.915 152.810 ;
        RECT 107.125 152.785 107.715 153.115 ;
        RECT 105.025 151.735 105.500 152.640 ;
        RECT 107.215 152.625 107.660 152.785 ;
        RECT 105.680 152.030 107.125 152.460 ;
        RECT 107.295 152.200 107.660 152.625 ;
        RECT 107.885 152.615 108.085 153.285 ;
        RECT 105.680 150.985 107.650 152.030 ;
        RECT 107.830 150.985 108.085 152.615 ;
        RECT 108.385 153.405 108.590 153.835 ;
        RECT 108.760 153.750 111.010 154.005 ;
        RECT 108.760 153.405 110.485 153.750 ;
        RECT 108.385 152.810 108.555 153.405 ;
        RECT 108.725 152.990 109.515 153.235 ;
        RECT 110.655 153.115 111.020 153.580 ;
        RECT 111.190 153.285 111.445 154.165 ;
        RECT 109.685 152.810 110.275 153.015 ;
        RECT 108.385 152.640 110.275 152.810 ;
        RECT 110.485 152.785 111.075 153.115 ;
        RECT 108.385 151.735 108.860 152.640 ;
        RECT 110.615 152.625 111.020 152.785 ;
        RECT 109.040 152.030 110.485 152.460 ;
        RECT 110.655 152.200 111.020 152.625 ;
        RECT 111.245 152.615 111.445 153.285 ;
        RECT 109.040 150.985 111.010 152.030 ;
        RECT 111.190 151.775 111.445 152.615 ;
        RECT 111.190 151.605 111.465 151.775 ;
        RECT 111.190 150.985 111.445 151.605 ;
        RECT 98.130 150.585 111.570 150.755 ;
        RECT 98.305 148.700 98.780 149.605 ;
        RECT 98.960 149.310 100.930 150.355 ;
        RECT 101.110 149.735 101.365 150.355 ;
        RECT 101.110 149.565 101.435 149.735 ;
        RECT 98.960 148.880 100.405 149.310 ;
        RECT 49.960 148.180 56.410 148.415 ;
        RECT 31.960 147.335 34.210 147.590 ;
        RECT 31.880 146.965 34.210 147.335 ;
        RECT 34.390 147.175 34.645 148.055 ;
        RECT 50.845 147.995 55.875 148.000 ;
        RECT 56.590 147.995 56.760 148.545 ;
        RECT 59.080 148.180 65.530 148.415 ;
        RECT 49.745 147.150 50.635 147.985 ;
        RECT 50.845 147.830 56.760 147.995 ;
        RECT 59.965 147.995 64.995 148.000 ;
        RECT 65.710 147.995 65.880 148.545 ;
        RECT 50.845 147.330 51.055 147.830 ;
        RECT 51.225 147.150 52.235 147.645 ;
        RECT 52.405 147.330 52.615 147.830 ;
        RECT 52.785 147.150 53.795 147.645 ;
        RECT 53.965 147.330 54.175 147.830 ;
        RECT 55.565 147.825 56.760 147.830 ;
        RECT 54.345 147.150 55.395 147.645 ;
        RECT 55.565 147.330 56.215 147.825 ;
        RECT 56.385 147.150 56.755 147.645 ;
        RECT 49.745 146.980 56.755 147.150 ;
        RECT 58.865 147.150 59.755 147.985 ;
        RECT 59.965 147.830 65.880 147.995 ;
        RECT 59.965 147.330 60.175 147.830 ;
        RECT 60.345 147.150 61.355 147.645 ;
        RECT 61.525 147.330 61.735 147.830 ;
        RECT 61.905 147.150 62.915 147.645 ;
        RECT 63.085 147.330 63.295 147.830 ;
        RECT 64.685 147.825 65.880 147.830 ;
        RECT 98.305 148.530 100.195 148.700 ;
        RECT 100.575 148.555 100.940 149.140 ;
        RECT 101.110 148.725 101.365 149.565 ;
        RECT 98.305 147.935 98.475 148.530 ;
        RECT 98.645 148.105 99.435 148.350 ;
        RECT 99.605 148.325 100.195 148.530 ;
        RECT 100.405 148.225 100.995 148.555 ;
        RECT 63.465 147.150 64.515 147.645 ;
        RECT 64.685 147.330 65.335 147.825 ;
        RECT 65.505 147.150 65.875 147.645 ;
        RECT 98.305 147.505 98.510 147.935 ;
        RECT 98.680 147.590 100.405 147.935 ;
        RECT 100.575 147.760 100.940 148.225 ;
        RECT 101.165 148.055 101.365 148.725 ;
        RECT 98.680 147.335 100.930 147.590 ;
        RECT 58.865 146.980 65.875 147.150 ;
        RECT 98.600 146.965 100.930 147.335 ;
        RECT 101.110 147.175 101.365 148.055 ;
        RECT 101.665 148.700 102.140 149.605 ;
        RECT 102.320 149.310 104.290 150.355 ;
        RECT 102.320 148.880 103.765 149.310 ;
        RECT 101.665 148.530 103.555 148.700 ;
        RECT 103.935 148.555 104.300 149.140 ;
        RECT 104.470 148.725 104.725 150.355 ;
        RECT 101.665 147.935 101.835 148.530 ;
        RECT 102.005 148.105 102.795 148.350 ;
        RECT 102.965 148.325 103.555 148.530 ;
        RECT 103.765 148.225 104.355 148.555 ;
        RECT 103.815 148.205 104.300 148.225 ;
        RECT 101.665 147.505 101.870 147.935 ;
        RECT 102.040 147.590 103.765 147.935 ;
        RECT 103.935 147.760 104.300 148.205 ;
        RECT 104.525 148.055 104.725 148.725 ;
        RECT 102.040 147.335 104.290 147.590 ;
        RECT 101.960 146.965 104.290 147.335 ;
        RECT 104.470 147.175 104.725 148.055 ;
        RECT 105.025 148.700 105.500 149.605 ;
        RECT 105.680 149.310 107.650 150.355 ;
        RECT 105.680 148.880 107.125 149.310 ;
        RECT 107.295 148.715 107.660 149.140 ;
        RECT 107.830 148.725 108.085 150.355 ;
        RECT 105.025 148.530 106.915 148.700 ;
        RECT 107.215 148.555 107.660 148.715 ;
        RECT 105.025 147.935 105.195 148.530 ;
        RECT 105.365 148.105 106.155 148.350 ;
        RECT 106.325 148.325 106.915 148.530 ;
        RECT 107.125 148.225 107.715 148.555 ;
        RECT 105.025 147.505 105.230 147.935 ;
        RECT 105.400 147.590 107.125 147.935 ;
        RECT 107.295 147.760 107.660 148.225 ;
        RECT 107.885 148.055 108.085 148.725 ;
        RECT 105.400 147.335 107.650 147.590 ;
        RECT 105.320 146.965 107.650 147.335 ;
        RECT 107.830 147.175 108.085 148.055 ;
        RECT 108.385 148.700 108.860 149.605 ;
        RECT 109.040 149.310 111.010 150.355 ;
        RECT 109.040 148.880 110.485 149.310 ;
        RECT 108.385 148.530 110.275 148.700 ;
        RECT 110.655 148.555 111.020 149.140 ;
        RECT 111.190 148.725 111.445 150.355 ;
        RECT 108.385 147.935 108.555 148.530 ;
        RECT 108.725 148.105 109.515 148.350 ;
        RECT 109.685 148.325 110.275 148.530 ;
        RECT 110.485 148.225 111.075 148.555 ;
        RECT 110.615 148.205 111.020 148.225 ;
        RECT 108.385 147.505 108.590 147.935 ;
        RECT 108.760 147.590 110.485 147.935 ;
        RECT 110.655 147.760 111.020 148.205 ;
        RECT 111.245 148.055 111.445 148.725 ;
        RECT 111.190 147.695 111.445 148.055 ;
        RECT 108.760 147.335 111.010 147.590 ;
        RECT 108.680 146.965 111.010 147.335 ;
        RECT 111.190 147.525 111.465 147.695 ;
        RECT 111.190 147.175 111.445 147.525 ;
        RECT 24.690 146.515 34.770 146.685 ;
        RECT 49.650 146.515 56.850 146.685 ;
        RECT 58.770 146.515 65.970 146.685 ;
        RECT 98.130 146.515 111.570 146.685 ;
        RECT 27.560 145.865 29.890 146.235 ;
        RECT 27.265 145.265 27.470 145.695 ;
        RECT 27.640 145.610 29.890 145.865 ;
        RECT 27.640 145.265 29.365 145.610 ;
        RECT 26.635 120.495 26.805 145.055 ;
        RECT 27.265 144.670 27.435 145.265 ;
        RECT 27.605 144.850 28.395 145.095 ;
        RECT 29.535 144.975 29.900 145.440 ;
        RECT 30.070 145.145 30.325 146.025 ;
        RECT 30.920 145.865 33.250 146.235 ;
        RECT 28.565 144.670 29.155 144.875 ;
        RECT 27.265 144.500 29.155 144.670 ;
        RECT 29.365 144.645 29.955 144.975 ;
        RECT 27.265 143.595 27.740 144.500 ;
        RECT 27.920 143.890 29.365 144.320 ;
        RECT 29.535 144.060 29.900 144.645 ;
        RECT 30.125 144.475 30.325 145.145 ;
        RECT 27.920 142.845 29.890 143.890 ;
        RECT 30.070 143.615 30.325 144.475 ;
        RECT 30.625 145.265 30.830 145.695 ;
        RECT 31.000 145.610 33.250 145.865 ;
        RECT 31.000 145.265 32.725 145.610 ;
        RECT 30.625 144.670 30.795 145.265 ;
        RECT 30.965 144.850 31.755 145.095 ;
        RECT 32.895 144.975 33.260 145.440 ;
        RECT 33.430 145.145 33.685 146.025 ;
        RECT 105.320 145.865 107.650 146.235 ;
        RECT 31.925 144.670 32.515 144.875 ;
        RECT 30.625 144.500 32.515 144.670 ;
        RECT 32.725 144.645 33.315 144.975 ;
        RECT 30.070 143.445 30.375 143.615 ;
        RECT 30.625 143.595 31.100 144.500 ;
        RECT 31.280 143.890 32.725 144.320 ;
        RECT 32.895 144.060 33.260 144.645 ;
        RECT 33.485 144.475 33.685 145.145 ;
        RECT 30.070 142.845 30.325 143.445 ;
        RECT 31.280 142.845 33.250 143.890 ;
        RECT 33.430 142.845 33.685 144.475 ;
        RECT 105.025 145.265 105.230 145.695 ;
        RECT 105.400 145.610 107.650 145.865 ;
        RECT 105.400 145.265 107.125 145.610 ;
        RECT 105.025 144.670 105.195 145.265 ;
        RECT 105.365 144.850 106.155 145.095 ;
        RECT 107.295 144.975 107.660 145.440 ;
        RECT 107.830 145.145 108.085 146.025 ;
        RECT 108.680 145.865 111.010 146.235 ;
        RECT 106.325 144.670 106.915 144.875 ;
        RECT 105.025 144.500 106.915 144.670 ;
        RECT 107.125 144.645 107.715 144.975 ;
        RECT 105.025 143.595 105.500 144.500 ;
        RECT 105.680 143.890 107.125 144.320 ;
        RECT 107.295 144.060 107.660 144.645 ;
        RECT 107.885 144.475 108.085 145.145 ;
        RECT 105.680 142.845 107.650 143.890 ;
        RECT 107.830 142.845 108.085 144.475 ;
        RECT 108.385 145.265 108.590 145.695 ;
        RECT 108.760 145.610 111.010 145.865 ;
        RECT 108.760 145.265 110.485 145.610 ;
        RECT 108.385 144.670 108.555 145.265 ;
        RECT 108.725 144.850 109.515 145.095 ;
        RECT 110.655 144.975 111.020 145.440 ;
        RECT 111.190 145.145 111.445 146.025 ;
        RECT 109.685 144.670 110.275 144.875 ;
        RECT 108.385 144.500 110.275 144.670 ;
        RECT 110.485 144.645 111.075 144.975 ;
        RECT 108.385 143.595 108.860 144.500 ;
        RECT 109.040 143.890 110.485 144.320 ;
        RECT 110.655 144.060 111.020 144.645 ;
        RECT 111.245 144.475 111.445 145.145 ;
        RECT 109.040 142.845 111.010 143.890 ;
        RECT 111.190 143.615 111.445 144.475 ;
        RECT 111.190 143.445 111.465 143.615 ;
        RECT 111.190 142.845 111.445 143.445 ;
        RECT 27.090 142.445 41.010 142.615 ;
        RECT 104.850 142.445 111.570 142.615 ;
        RECT 31.105 140.560 31.580 141.465 ;
        RECT 31.760 141.170 33.730 142.215 ;
        RECT 31.760 140.740 33.205 141.170 ;
        RECT 31.105 140.390 32.995 140.560 ;
        RECT 33.375 140.415 33.740 141.000 ;
        RECT 33.910 140.585 34.165 142.215 ;
        RECT 31.105 139.795 31.275 140.390 ;
        RECT 31.735 140.210 31.905 140.215 ;
        RECT 31.445 139.965 32.235 140.210 ;
        RECT 32.405 140.185 32.995 140.390 ;
        RECT 33.205 140.085 33.795 140.415 ;
        RECT 31.105 139.365 31.310 139.795 ;
        RECT 31.480 139.450 33.205 139.795 ;
        RECT 33.375 139.620 33.740 140.085 ;
        RECT 33.965 139.915 34.165 140.585 ;
        RECT 31.480 139.195 33.730 139.450 ;
        RECT 31.400 138.825 33.730 139.195 ;
        RECT 33.910 139.035 34.165 139.915 ;
        RECT 34.465 140.560 34.940 141.465 ;
        RECT 35.120 141.170 37.090 142.215 ;
        RECT 35.120 140.740 36.565 141.170 ;
        RECT 34.465 140.390 36.355 140.560 ;
        RECT 36.735 140.415 37.100 141.000 ;
        RECT 37.270 140.585 37.525 142.215 ;
        RECT 34.465 139.795 34.635 140.390 ;
        RECT 35.135 140.210 35.305 140.215 ;
        RECT 34.805 139.965 35.595 140.210 ;
        RECT 35.765 140.185 36.355 140.390 ;
        RECT 36.565 140.085 37.155 140.415 ;
        RECT 34.465 139.365 34.670 139.795 ;
        RECT 34.840 139.450 36.565 139.795 ;
        RECT 36.735 139.620 37.100 140.085 ;
        RECT 37.325 139.915 37.525 140.585 ;
        RECT 34.840 139.195 37.090 139.450 ;
        RECT 34.760 138.825 37.090 139.195 ;
        RECT 37.270 139.035 37.525 139.915 ;
        RECT 37.825 140.560 38.300 141.465 ;
        RECT 38.480 141.170 40.450 142.215 ;
        RECT 38.480 140.740 39.925 141.170 ;
        RECT 37.825 140.390 39.715 140.560 ;
        RECT 40.095 140.415 40.460 141.000 ;
        RECT 40.630 140.585 40.885 142.215 ;
        RECT 40.685 140.555 40.885 140.585 ;
        RECT 105.025 140.560 105.500 141.465 ;
        RECT 105.680 141.170 107.650 142.215 ;
        RECT 105.680 140.740 107.125 141.170 ;
        RECT 37.825 139.795 37.995 140.390 ;
        RECT 38.195 140.210 38.365 140.215 ;
        RECT 38.165 139.965 38.955 140.210 ;
        RECT 39.125 140.185 39.715 140.390 ;
        RECT 39.925 140.085 40.515 140.415 ;
        RECT 40.685 140.385 40.915 140.555 ;
        RECT 105.025 140.390 106.915 140.560 ;
        RECT 107.295 140.415 107.660 141.000 ;
        RECT 107.830 140.585 108.085 142.215 ;
        RECT 37.825 139.365 38.030 139.795 ;
        RECT 38.200 139.450 39.925 139.795 ;
        RECT 40.095 139.620 40.460 140.085 ;
        RECT 40.685 139.915 40.885 140.385 ;
        RECT 38.200 139.195 40.450 139.450 ;
        RECT 38.120 138.825 40.450 139.195 ;
        RECT 40.630 139.035 40.885 139.915 ;
        RECT 105.025 139.795 105.195 140.390 ;
        RECT 105.515 140.210 105.685 140.215 ;
        RECT 105.365 139.965 106.155 140.210 ;
        RECT 106.325 140.185 106.915 140.390 ;
        RECT 107.125 140.085 107.715 140.415 ;
        RECT 107.215 140.045 107.660 140.085 ;
        RECT 105.025 139.365 105.230 139.795 ;
        RECT 105.400 139.450 107.125 139.795 ;
        RECT 107.295 139.620 107.660 140.045 ;
        RECT 107.885 139.915 108.085 140.585 ;
        RECT 105.400 139.195 107.650 139.450 ;
        RECT 105.320 138.825 107.650 139.195 ;
        RECT 107.830 139.035 108.085 139.915 ;
        RECT 108.385 140.560 108.860 141.465 ;
        RECT 109.040 141.170 111.010 142.215 ;
        RECT 111.190 141.575 111.445 142.215 ;
        RECT 111.190 141.405 111.465 141.575 ;
        RECT 109.040 140.740 110.485 141.170 ;
        RECT 108.385 140.390 110.275 140.560 ;
        RECT 110.655 140.415 111.020 141.000 ;
        RECT 111.190 140.585 111.445 141.405 ;
        RECT 108.385 139.795 108.555 140.390 ;
        RECT 108.915 140.210 109.085 140.215 ;
        RECT 108.725 139.965 109.515 140.210 ;
        RECT 109.685 140.185 110.275 140.390 ;
        RECT 110.485 140.085 111.075 140.415 ;
        RECT 110.615 140.045 111.020 140.085 ;
        RECT 108.385 139.365 108.590 139.795 ;
        RECT 108.760 139.450 110.485 139.795 ;
        RECT 110.655 139.620 111.020 140.045 ;
        RECT 111.245 139.915 111.445 140.585 ;
        RECT 108.760 139.195 111.010 139.450 ;
        RECT 108.680 138.825 111.010 139.195 ;
        RECT 111.190 139.035 111.445 139.915 ;
        RECT 27.090 138.375 41.010 138.545 ;
        RECT 101.970 138.375 112.050 138.545 ;
        RECT 27.560 137.725 29.890 138.095 ;
        RECT 27.265 137.125 27.470 137.555 ;
        RECT 27.640 137.470 29.890 137.725 ;
        RECT 30.070 137.495 30.325 137.885 ;
        RECT 30.920 137.725 33.250 138.095 ;
        RECT 27.640 137.125 29.365 137.470 ;
        RECT 30.070 137.325 30.375 137.495 ;
        RECT 27.265 136.530 27.435 137.125 ;
        RECT 27.605 136.710 28.395 136.955 ;
        RECT 29.535 136.835 29.900 137.300 ;
        RECT 30.070 137.005 30.325 137.325 ;
        RECT 28.565 136.530 29.155 136.735 ;
        RECT 27.265 136.360 29.155 136.530 ;
        RECT 29.365 136.505 29.955 136.835 ;
        RECT 27.265 135.455 27.740 136.360 ;
        RECT 27.920 135.750 29.365 136.180 ;
        RECT 29.535 135.920 29.900 136.505 ;
        RECT 30.125 136.335 30.325 137.005 ;
        RECT 27.920 134.705 29.890 135.750 ;
        RECT 30.070 134.705 30.325 136.335 ;
        RECT 30.625 137.125 30.830 137.555 ;
        RECT 31.000 137.470 33.250 137.725 ;
        RECT 31.000 137.125 32.725 137.470 ;
        RECT 30.625 136.530 30.795 137.125 ;
        RECT 30.965 136.710 31.755 136.955 ;
        RECT 32.895 136.835 33.260 137.300 ;
        RECT 33.430 137.005 33.685 137.885 ;
        RECT 102.440 137.725 104.770 138.095 ;
        RECT 31.925 136.530 32.515 136.735 ;
        RECT 30.625 136.360 32.515 136.530 ;
        RECT 32.725 136.505 33.315 136.835 ;
        RECT 30.625 135.455 31.100 136.360 ;
        RECT 31.280 135.750 32.725 136.180 ;
        RECT 32.895 135.920 33.260 136.505 ;
        RECT 33.485 136.335 33.685 137.005 ;
        RECT 31.280 134.705 33.250 135.750 ;
        RECT 33.430 134.705 33.685 136.335 ;
        RECT 102.145 137.125 102.350 137.555 ;
        RECT 102.520 137.470 104.770 137.725 ;
        RECT 102.520 137.125 104.245 137.470 ;
        RECT 102.145 136.530 102.315 137.125 ;
        RECT 102.485 136.710 103.275 136.955 ;
        RECT 104.415 136.835 104.780 137.300 ;
        RECT 104.950 137.005 105.205 137.885 ;
        RECT 105.800 137.725 108.130 138.095 ;
        RECT 103.445 136.530 104.035 136.735 ;
        RECT 102.145 136.360 104.035 136.530 ;
        RECT 104.245 136.505 104.835 136.835 ;
        RECT 102.145 135.455 102.620 136.360 ;
        RECT 102.800 135.750 104.245 136.180 ;
        RECT 104.415 135.920 104.780 136.505 ;
        RECT 105.005 136.335 105.205 137.005 ;
        RECT 102.800 134.705 104.770 135.750 ;
        RECT 104.950 134.705 105.205 136.335 ;
        RECT 105.505 137.125 105.710 137.555 ;
        RECT 105.880 137.470 108.130 137.725 ;
        RECT 105.880 137.125 107.605 137.470 ;
        RECT 105.505 136.530 105.675 137.125 ;
        RECT 105.845 136.710 106.635 136.955 ;
        RECT 107.775 136.835 108.140 137.300 ;
        RECT 108.310 137.005 108.565 137.885 ;
        RECT 109.160 137.725 111.490 138.095 ;
        RECT 106.805 136.530 107.395 136.735 ;
        RECT 105.505 136.360 107.395 136.530 ;
        RECT 107.605 136.505 108.195 136.835 ;
        RECT 105.505 135.455 105.980 136.360 ;
        RECT 106.160 135.750 107.605 136.180 ;
        RECT 107.775 135.920 108.140 136.505 ;
        RECT 108.365 136.335 108.565 137.005 ;
        RECT 106.160 134.705 108.130 135.750 ;
        RECT 108.310 135.455 108.565 136.335 ;
        RECT 108.865 137.125 109.070 137.555 ;
        RECT 109.240 137.470 111.490 137.725 ;
        RECT 111.670 137.495 111.925 137.885 ;
        RECT 109.240 137.125 110.965 137.470 ;
        RECT 111.670 137.325 111.975 137.495 ;
        RECT 108.865 136.530 109.035 137.125 ;
        RECT 109.205 136.710 109.995 136.955 ;
        RECT 111.135 136.835 111.500 137.300 ;
        RECT 111.670 137.005 111.925 137.325 ;
        RECT 110.165 136.530 110.755 136.735 ;
        RECT 108.865 136.360 110.755 136.530 ;
        RECT 110.965 136.505 111.555 136.835 ;
        RECT 108.865 135.455 109.340 136.360 ;
        RECT 109.520 135.750 110.965 136.180 ;
        RECT 111.135 135.920 111.500 136.505 ;
        RECT 111.725 136.335 111.925 137.005 ;
        RECT 108.310 135.285 108.575 135.455 ;
        RECT 108.310 134.705 108.565 135.285 ;
        RECT 109.520 134.705 111.490 135.750 ;
        RECT 111.670 134.705 111.925 136.335 ;
        RECT 27.090 134.305 37.650 134.475 ;
        RECT 101.490 134.305 112.050 134.475 ;
        RECT 26.975 127.805 27.145 132.735 ;
        RECT 27.745 132.420 28.220 133.325 ;
        RECT 28.400 133.030 30.370 134.075 ;
        RECT 28.400 132.600 29.845 133.030 ;
        RECT 27.745 132.250 29.635 132.420 ;
        RECT 30.015 132.275 30.380 132.860 ;
        RECT 30.550 132.445 30.805 134.075 ;
        RECT 27.745 131.655 27.915 132.250 ;
        RECT 28.085 131.825 28.875 132.070 ;
        RECT 29.045 132.045 29.635 132.250 ;
        RECT 29.845 131.945 30.435 132.275 ;
        RECT 27.745 131.225 27.950 131.655 ;
        RECT 28.120 131.310 29.845 131.655 ;
        RECT 30.015 131.480 30.380 131.945 ;
        RECT 30.605 131.775 30.805 132.445 ;
        RECT 30.550 131.375 30.805 131.775 ;
        RECT 31.105 132.420 31.580 133.325 ;
        RECT 31.760 133.030 33.730 134.075 ;
        RECT 31.760 132.600 33.205 133.030 ;
        RECT 31.105 132.250 32.995 132.420 ;
        RECT 33.375 132.275 33.740 132.860 ;
        RECT 33.910 132.445 34.165 134.075 ;
        RECT 31.105 131.655 31.275 132.250 ;
        RECT 31.445 131.825 32.235 132.070 ;
        RECT 32.405 132.045 32.995 132.250 ;
        RECT 33.205 131.945 33.795 132.275 ;
        RECT 28.120 131.055 30.370 131.310 ;
        RECT 28.040 130.685 30.370 131.055 ;
        RECT 30.550 131.205 30.885 131.375 ;
        RECT 31.105 131.225 31.310 131.655 ;
        RECT 31.480 131.310 33.205 131.655 ;
        RECT 33.375 131.480 33.740 131.945 ;
        RECT 33.965 131.775 34.165 132.445 ;
        RECT 30.550 130.895 30.805 131.205 ;
        RECT 31.480 131.055 33.730 131.310 ;
        RECT 31.400 130.685 33.730 131.055 ;
        RECT 33.910 130.895 34.165 131.775 ;
        RECT 34.465 132.420 34.940 133.325 ;
        RECT 35.120 133.030 37.090 134.075 ;
        RECT 35.120 132.600 36.565 133.030 ;
        RECT 34.465 132.250 36.355 132.420 ;
        RECT 36.735 132.275 37.100 132.860 ;
        RECT 37.270 132.445 37.525 134.075 ;
        RECT 34.465 131.655 34.635 132.250 ;
        RECT 34.805 131.825 35.595 132.070 ;
        RECT 35.765 132.045 36.355 132.250 ;
        RECT 36.565 131.945 37.155 132.275 ;
        RECT 34.465 131.225 34.670 131.655 ;
        RECT 34.840 131.310 36.565 131.655 ;
        RECT 36.735 131.480 37.100 131.945 ;
        RECT 37.325 131.775 37.525 132.445 ;
        RECT 34.840 131.055 37.090 131.310 ;
        RECT 34.760 130.685 37.090 131.055 ;
        RECT 37.270 130.895 37.525 131.775 ;
        RECT 101.665 132.420 102.140 133.325 ;
        RECT 102.320 133.030 104.290 134.075 ;
        RECT 102.320 132.600 103.765 133.030 ;
        RECT 101.665 132.250 103.555 132.420 ;
        RECT 103.935 132.275 104.300 132.860 ;
        RECT 104.470 132.445 104.725 134.075 ;
        RECT 101.665 131.655 101.835 132.250 ;
        RECT 102.005 131.825 102.795 132.070 ;
        RECT 102.965 132.045 103.555 132.250 ;
        RECT 103.765 131.945 104.355 132.275 ;
        RECT 103.815 131.885 104.300 131.945 ;
        RECT 101.665 131.225 101.870 131.655 ;
        RECT 102.040 131.310 103.765 131.655 ;
        RECT 103.935 131.480 104.300 131.885 ;
        RECT 104.525 131.775 104.725 132.445 ;
        RECT 102.040 131.055 104.290 131.310 ;
        RECT 101.960 130.685 104.290 131.055 ;
        RECT 104.470 130.895 104.725 131.775 ;
        RECT 105.025 132.420 105.500 133.325 ;
        RECT 105.680 133.030 107.650 134.075 ;
        RECT 105.680 132.600 107.125 133.030 ;
        RECT 105.025 132.250 106.915 132.420 ;
        RECT 107.295 132.275 107.660 132.860 ;
        RECT 107.830 132.445 108.085 134.075 ;
        RECT 105.025 131.655 105.195 132.250 ;
        RECT 105.365 131.825 106.155 132.070 ;
        RECT 106.325 132.045 106.915 132.250 ;
        RECT 107.125 131.945 107.715 132.275 ;
        RECT 105.025 131.225 105.230 131.655 ;
        RECT 105.400 131.310 107.125 131.655 ;
        RECT 107.295 131.480 107.660 131.945 ;
        RECT 107.885 131.775 108.085 132.445 ;
        RECT 105.400 131.055 107.650 131.310 ;
        RECT 105.320 130.685 107.650 131.055 ;
        RECT 107.830 130.895 108.085 131.775 ;
        RECT 108.385 132.420 108.860 133.325 ;
        RECT 109.040 133.030 111.010 134.075 ;
        RECT 109.040 132.600 110.485 133.030 ;
        RECT 108.385 132.250 110.275 132.420 ;
        RECT 110.655 132.275 111.020 132.860 ;
        RECT 111.190 132.445 111.445 134.075 ;
        RECT 108.385 131.655 108.555 132.250 ;
        RECT 108.725 131.825 109.515 132.070 ;
        RECT 109.685 132.045 110.275 132.250 ;
        RECT 110.485 131.945 111.075 132.275 ;
        RECT 110.615 131.885 111.020 131.945 ;
        RECT 108.385 131.225 108.590 131.655 ;
        RECT 108.760 131.310 110.485 131.655 ;
        RECT 110.655 131.480 111.020 131.885 ;
        RECT 111.245 131.775 111.445 132.445 ;
        RECT 111.190 131.375 111.445 131.775 ;
        RECT 108.760 131.055 111.010 131.310 ;
        RECT 108.680 130.685 111.010 131.055 ;
        RECT 111.190 131.205 111.465 131.375 ;
        RECT 111.190 130.895 111.445 131.205 ;
        RECT 27.570 130.235 41.010 130.405 ;
        RECT 101.490 130.235 111.570 130.405 ;
        RECT 28.040 129.585 30.370 129.955 ;
        RECT 27.745 128.985 27.950 129.415 ;
        RECT 28.120 129.330 30.370 129.585 ;
        RECT 30.550 129.335 30.805 129.745 ;
        RECT 31.400 129.585 33.730 129.955 ;
        RECT 28.120 128.985 29.845 129.330 ;
        RECT 30.550 129.165 30.885 129.335 ;
        RECT 27.745 128.390 27.915 128.985 ;
        RECT 28.085 128.570 28.875 128.815 ;
        RECT 30.015 128.695 30.380 129.160 ;
        RECT 30.550 128.865 30.805 129.165 ;
        RECT 29.045 128.390 29.635 128.595 ;
        RECT 27.745 128.220 29.635 128.390 ;
        RECT 29.845 128.365 30.435 128.695 ;
        RECT 27.745 127.315 28.220 128.220 ;
        RECT 28.400 127.610 29.845 128.040 ;
        RECT 30.015 127.780 30.380 128.365 ;
        RECT 30.605 128.195 30.805 128.865 ;
        RECT 28.400 126.565 30.370 127.610 ;
        RECT 30.550 126.565 30.805 128.195 ;
        RECT 31.105 128.985 31.310 129.415 ;
        RECT 31.480 129.330 33.730 129.585 ;
        RECT 31.480 128.985 33.205 129.330 ;
        RECT 31.105 128.390 31.275 128.985 ;
        RECT 31.445 128.570 32.235 128.815 ;
        RECT 33.375 128.695 33.740 129.160 ;
        RECT 33.910 128.865 34.165 129.745 ;
        RECT 34.760 129.585 37.090 129.955 ;
        RECT 32.405 128.390 32.995 128.595 ;
        RECT 31.105 128.220 32.995 128.390 ;
        RECT 33.205 128.365 33.795 128.695 ;
        RECT 31.105 127.315 31.580 128.220 ;
        RECT 31.760 127.610 33.205 128.040 ;
        RECT 33.375 127.780 33.740 128.365 ;
        RECT 33.965 128.195 34.165 128.865 ;
        RECT 31.760 126.565 33.730 127.610 ;
        RECT 33.910 126.565 34.165 128.195 ;
        RECT 34.465 128.985 34.670 129.415 ;
        RECT 34.840 129.330 37.090 129.585 ;
        RECT 34.840 128.985 36.565 129.330 ;
        RECT 34.465 128.390 34.635 128.985 ;
        RECT 34.805 128.570 35.595 128.815 ;
        RECT 36.735 128.695 37.100 129.160 ;
        RECT 37.270 128.865 37.525 129.745 ;
        RECT 38.120 129.585 40.450 129.955 ;
        RECT 35.765 128.390 36.355 128.595 ;
        RECT 34.465 128.220 36.355 128.390 ;
        RECT 36.565 128.365 37.155 128.695 ;
        RECT 34.465 127.315 34.940 128.220 ;
        RECT 35.120 127.610 36.565 128.040 ;
        RECT 36.735 127.780 37.100 128.365 ;
        RECT 37.325 128.195 37.525 128.865 ;
        RECT 35.120 126.565 37.090 127.610 ;
        RECT 37.270 126.565 37.525 128.195 ;
        RECT 37.825 128.985 38.030 129.415 ;
        RECT 38.200 129.330 40.450 129.585 ;
        RECT 38.200 128.985 39.925 129.330 ;
        RECT 37.825 128.390 37.995 128.985 ;
        RECT 38.165 128.570 38.955 128.815 ;
        RECT 40.095 128.695 40.460 129.160 ;
        RECT 40.630 128.865 40.885 129.745 ;
        RECT 101.960 129.585 104.290 129.955 ;
        RECT 39.125 128.390 39.715 128.595 ;
        RECT 37.825 128.220 39.715 128.390 ;
        RECT 39.925 128.365 40.515 128.695 ;
        RECT 37.825 127.315 38.300 128.220 ;
        RECT 38.480 127.610 39.925 128.040 ;
        RECT 40.095 127.780 40.460 128.365 ;
        RECT 40.685 128.315 40.885 128.865 ;
        RECT 101.665 128.985 101.870 129.415 ;
        RECT 102.040 129.330 104.290 129.585 ;
        RECT 102.040 128.985 103.765 129.330 ;
        RECT 101.665 128.390 101.835 128.985 ;
        RECT 102.005 128.570 102.795 128.815 ;
        RECT 103.935 128.695 104.300 129.160 ;
        RECT 104.470 128.865 104.725 129.745 ;
        RECT 105.320 129.585 107.650 129.955 ;
        RECT 102.965 128.390 103.555 128.595 ;
        RECT 40.685 128.195 40.915 128.315 ;
        RECT 40.630 128.145 40.915 128.195 ;
        RECT 101.665 128.220 103.555 128.390 ;
        RECT 103.765 128.365 104.355 128.695 ;
        RECT 38.480 126.565 40.450 127.610 ;
        RECT 40.630 126.565 40.885 128.145 ;
        RECT 101.665 127.315 102.140 128.220 ;
        RECT 102.320 127.610 103.765 128.040 ;
        RECT 103.935 127.780 104.300 128.365 ;
        RECT 104.525 128.195 104.725 128.865 ;
        RECT 102.320 126.565 104.290 127.610 ;
        RECT 104.470 126.565 104.725 128.195 ;
        RECT 105.025 128.985 105.230 129.415 ;
        RECT 105.400 129.330 107.650 129.585 ;
        RECT 105.400 128.985 107.125 129.330 ;
        RECT 105.025 128.390 105.195 128.985 ;
        RECT 105.365 128.570 106.155 128.815 ;
        RECT 107.295 128.695 107.660 129.160 ;
        RECT 107.830 128.865 108.085 129.745 ;
        RECT 108.680 129.585 111.010 129.955 ;
        RECT 106.325 128.390 106.915 128.595 ;
        RECT 105.025 128.220 106.915 128.390 ;
        RECT 107.125 128.365 107.715 128.695 ;
        RECT 105.025 127.315 105.500 128.220 ;
        RECT 105.680 127.610 107.125 128.040 ;
        RECT 107.295 127.780 107.660 128.365 ;
        RECT 107.885 128.195 108.085 128.865 ;
        RECT 105.680 126.565 107.650 127.610 ;
        RECT 107.830 126.565 108.085 128.195 ;
        RECT 108.385 128.985 108.590 129.415 ;
        RECT 108.760 129.330 111.010 129.585 ;
        RECT 111.190 129.335 111.445 129.745 ;
        RECT 108.760 128.985 110.485 129.330 ;
        RECT 111.190 129.165 111.465 129.335 ;
        RECT 108.385 128.390 108.555 128.985 ;
        RECT 108.725 128.570 109.515 128.815 ;
        RECT 110.655 128.695 111.020 129.160 ;
        RECT 111.190 128.865 111.445 129.165 ;
        RECT 109.685 128.390 110.275 128.595 ;
        RECT 108.385 128.220 110.275 128.390 ;
        RECT 110.485 128.365 111.075 128.695 ;
        RECT 108.385 127.315 108.860 128.220 ;
        RECT 109.040 127.610 110.485 128.040 ;
        RECT 110.655 127.780 111.020 128.365 ;
        RECT 111.245 128.195 111.445 128.865 ;
        RECT 109.040 126.565 111.010 127.610 ;
        RECT 111.190 126.565 111.445 128.195 ;
        RECT 27.090 126.165 41.010 126.335 ;
        RECT 101.490 126.165 112.050 126.335 ;
        RECT 27.265 124.280 27.740 125.185 ;
        RECT 27.920 124.890 29.890 125.935 ;
        RECT 27.920 124.460 29.365 124.890 ;
        RECT 27.265 124.110 29.155 124.280 ;
        RECT 29.535 124.135 29.900 124.720 ;
        RECT 30.070 124.575 30.325 125.935 ;
        RECT 30.070 124.405 30.375 124.575 ;
        RECT 30.070 124.305 30.325 124.405 ;
        RECT 27.265 123.515 27.435 124.110 ;
        RECT 27.605 123.685 28.395 123.930 ;
        RECT 28.565 123.905 29.155 124.110 ;
        RECT 29.365 123.805 29.955 124.135 ;
        RECT 27.265 123.085 27.470 123.515 ;
        RECT 27.640 123.170 29.365 123.515 ;
        RECT 29.535 123.340 29.900 123.805 ;
        RECT 30.125 123.635 30.325 124.305 ;
        RECT 27.640 122.915 29.890 123.170 ;
        RECT 27.560 122.545 29.890 122.915 ;
        RECT 30.070 122.755 30.325 123.635 ;
        RECT 30.625 124.280 31.100 125.185 ;
        RECT 31.280 124.890 33.250 125.935 ;
        RECT 31.280 124.460 32.725 124.890 ;
        RECT 30.625 124.110 32.515 124.280 ;
        RECT 32.895 124.235 33.260 124.720 ;
        RECT 33.430 124.305 33.685 125.935 ;
        RECT 32.895 124.135 33.265 124.235 ;
        RECT 30.625 123.515 30.795 124.110 ;
        RECT 30.965 123.685 31.755 123.930 ;
        RECT 31.925 123.905 32.515 124.110 ;
        RECT 32.725 123.805 33.315 124.135 ;
        RECT 30.625 123.085 30.830 123.515 ;
        RECT 31.000 123.170 32.725 123.515 ;
        RECT 32.895 123.340 33.260 123.805 ;
        RECT 33.485 123.635 33.685 124.305 ;
        RECT 102.145 124.280 102.620 125.185 ;
        RECT 102.800 124.890 104.770 125.935 ;
        RECT 102.800 124.460 104.245 124.890 ;
        RECT 102.145 124.110 104.035 124.280 ;
        RECT 104.415 124.135 104.780 124.720 ;
        RECT 104.950 124.305 105.205 125.935 ;
        RECT 31.000 122.915 33.250 123.170 ;
        RECT 30.920 122.545 33.250 122.915 ;
        RECT 33.430 122.755 33.685 123.635 ;
        RECT 27.090 122.095 40.050 122.265 ;
        RECT 27.560 121.445 29.890 121.815 ;
        RECT 27.265 120.845 27.470 121.275 ;
        RECT 27.640 121.190 29.890 121.445 ;
        RECT 27.640 120.845 29.365 121.190 ;
        RECT 30.070 121.175 30.325 121.605 ;
        RECT 33.800 121.445 36.130 121.815 ;
        RECT 27.265 120.250 27.435 120.845 ;
        RECT 27.605 120.430 28.395 120.675 ;
        RECT 29.535 120.555 29.900 121.020 ;
        RECT 30.070 121.005 30.375 121.175 ;
        RECT 30.070 120.725 30.325 121.005 ;
        RECT 33.505 120.845 33.710 121.275 ;
        RECT 33.880 121.190 36.130 121.445 ;
        RECT 33.880 120.845 35.605 121.190 ;
        RECT 28.565 120.250 29.155 120.455 ;
        RECT 27.265 120.080 29.155 120.250 ;
        RECT 29.365 120.225 29.955 120.555 ;
        RECT 27.265 119.175 27.740 120.080 ;
        RECT 27.920 119.470 29.365 119.900 ;
        RECT 29.535 119.640 29.900 120.225 ;
        RECT 30.125 120.055 30.325 120.725 ;
        RECT 27.920 118.425 29.890 119.470 ;
        RECT 30.070 118.425 30.325 120.055 ;
        RECT 27.090 118.025 30.450 118.195 ;
        RECT 27.265 116.140 27.740 117.045 ;
        RECT 27.920 116.750 29.890 117.795 ;
        RECT 30.070 117.095 30.325 117.795 ;
        RECT 30.070 116.925 30.375 117.095 ;
        RECT 27.920 116.320 29.365 116.750 ;
        RECT 27.265 115.970 29.155 116.140 ;
        RECT 29.535 115.995 29.900 116.580 ;
        RECT 30.070 116.165 30.325 116.925 ;
        RECT 27.265 115.375 27.435 115.970 ;
        RECT 27.605 115.545 28.395 115.790 ;
        RECT 28.565 115.765 29.155 115.970 ;
        RECT 29.365 115.665 29.955 115.995 ;
        RECT 27.265 114.945 27.470 115.375 ;
        RECT 27.640 115.030 29.365 115.375 ;
        RECT 29.535 115.200 29.900 115.665 ;
        RECT 30.125 115.495 30.325 116.165 ;
        RECT 27.640 114.775 29.890 115.030 ;
        RECT 27.560 114.405 29.890 114.775 ;
        RECT 30.070 114.615 30.325 115.495 ;
        RECT 30.715 115.225 30.885 120.835 ;
        RECT 33.505 120.250 33.675 120.845 ;
        RECT 33.845 120.430 34.635 120.675 ;
        RECT 35.775 120.555 36.140 121.020 ;
        RECT 36.310 120.725 36.565 121.605 ;
        RECT 37.160 121.445 39.490 121.815 ;
        RECT 34.805 120.250 35.395 120.455 ;
        RECT 33.505 120.080 35.395 120.250 ;
        RECT 35.605 120.225 36.195 120.555 ;
        RECT 33.505 119.175 33.980 120.080 ;
        RECT 34.160 119.470 35.605 119.900 ;
        RECT 35.775 119.640 36.140 120.225 ;
        RECT 36.365 120.055 36.565 120.725 ;
        RECT 34.160 118.425 36.130 119.470 ;
        RECT 36.310 118.425 36.565 120.055 ;
        RECT 36.865 120.845 37.070 121.275 ;
        RECT 37.240 121.190 39.490 121.445 ;
        RECT 37.240 120.845 38.965 121.190 ;
        RECT 36.865 120.250 37.035 120.845 ;
        RECT 37.205 120.430 37.995 120.675 ;
        RECT 39.135 120.555 39.500 121.020 ;
        RECT 39.670 120.725 39.925 121.605 ;
        RECT 38.165 120.250 38.755 120.455 ;
        RECT 36.865 120.080 38.755 120.250 ;
        RECT 38.965 120.225 39.555 120.555 ;
        RECT 36.865 119.175 37.340 120.080 ;
        RECT 37.520 119.470 38.965 119.900 ;
        RECT 39.135 119.640 39.500 120.225 ;
        RECT 39.725 120.055 39.925 120.725 ;
        RECT 37.520 118.425 39.490 119.470 ;
        RECT 39.670 118.425 39.925 120.055 ;
        RECT 31.890 118.025 40.050 118.195 ;
        RECT 32.065 116.140 32.540 117.045 ;
        RECT 32.720 116.750 34.690 117.795 ;
        RECT 32.720 116.320 34.165 116.750 ;
        RECT 32.065 115.970 33.955 116.140 ;
        RECT 34.335 115.995 34.700 116.580 ;
        RECT 34.870 116.165 35.125 117.795 ;
        RECT 34.925 116.075 35.125 116.165 ;
        RECT 32.065 115.375 32.235 115.970 ;
        RECT 32.405 115.545 33.195 115.790 ;
        RECT 33.365 115.765 33.955 115.970 ;
        RECT 34.165 115.665 34.755 115.995 ;
        RECT 34.925 115.905 35.135 116.075 ;
        RECT 32.065 114.945 32.270 115.375 ;
        RECT 32.440 115.030 34.165 115.375 ;
        RECT 34.335 115.200 34.700 115.665 ;
        RECT 34.925 115.495 35.125 115.905 ;
        RECT 32.440 114.775 34.690 115.030 ;
        RECT 32.360 114.405 34.690 114.775 ;
        RECT 34.870 114.615 35.125 115.495 ;
        RECT 27.090 113.955 37.170 114.125 ;
        RECT 27.560 113.305 29.890 113.675 ;
        RECT 27.265 112.705 27.470 113.135 ;
        RECT 27.640 113.050 29.890 113.305 ;
        RECT 27.640 112.705 29.365 113.050 ;
        RECT 30.070 113.015 30.325 113.465 ;
        RECT 30.920 113.305 33.250 113.675 ;
        RECT 27.265 112.110 27.435 112.705 ;
        RECT 27.605 112.290 28.395 112.535 ;
        RECT 29.535 112.415 29.900 112.880 ;
        RECT 30.070 112.845 30.375 113.015 ;
        RECT 30.070 112.585 30.325 112.845 ;
        RECT 28.565 112.110 29.155 112.315 ;
        RECT 27.265 111.940 29.155 112.110 ;
        RECT 29.365 112.085 29.955 112.415 ;
        RECT 27.265 111.035 27.740 111.940 ;
        RECT 27.920 111.330 29.365 111.760 ;
        RECT 29.535 111.500 29.900 112.085 ;
        RECT 30.125 111.915 30.325 112.585 ;
        RECT 27.920 110.285 29.890 111.330 ;
        RECT 30.070 110.285 30.325 111.915 ;
        RECT 30.625 112.705 30.830 113.135 ;
        RECT 31.000 113.050 33.250 113.305 ;
        RECT 31.000 112.705 32.725 113.050 ;
        RECT 30.625 112.110 30.795 112.705 ;
        RECT 30.965 112.290 31.755 112.535 ;
        RECT 32.895 112.415 33.260 112.880 ;
        RECT 33.430 112.585 33.685 113.465 ;
        RECT 34.280 113.305 36.610 113.675 ;
        RECT 31.925 112.110 32.515 112.315 ;
        RECT 30.625 111.940 32.515 112.110 ;
        RECT 32.725 112.085 33.315 112.415 ;
        RECT 30.625 111.035 31.100 111.940 ;
        RECT 31.280 111.330 32.725 111.760 ;
        RECT 32.895 111.500 33.260 112.085 ;
        RECT 33.485 111.915 33.685 112.585 ;
        RECT 31.280 110.285 33.250 111.330 ;
        RECT 33.430 110.285 33.685 111.915 ;
        RECT 33.985 112.705 34.190 113.135 ;
        RECT 34.360 113.050 36.610 113.305 ;
        RECT 34.360 112.705 36.085 113.050 ;
        RECT 33.985 112.110 34.155 112.705 ;
        RECT 34.325 112.290 35.115 112.535 ;
        RECT 36.255 112.415 36.620 112.880 ;
        RECT 36.790 112.585 37.045 113.465 ;
        RECT 35.285 112.110 35.875 112.315 ;
        RECT 33.985 111.940 35.875 112.110 ;
        RECT 36.085 112.085 36.675 112.415 ;
        RECT 33.985 111.035 34.460 111.940 ;
        RECT 34.640 111.330 36.085 111.760 ;
        RECT 36.255 111.500 36.620 112.085 ;
        RECT 36.845 111.915 37.045 112.585 ;
        RECT 34.640 110.285 36.610 111.330 ;
        RECT 36.790 110.285 37.045 111.915 ;
        RECT 27.090 109.885 41.010 110.055 ;
        RECT 27.265 108.000 27.740 108.905 ;
        RECT 27.920 108.610 29.890 109.655 ;
        RECT 30.070 108.935 30.325 109.655 ;
        RECT 30.070 108.765 30.375 108.935 ;
        RECT 27.920 108.180 29.365 108.610 ;
        RECT 27.265 107.830 29.155 108.000 ;
        RECT 29.535 107.855 29.900 108.440 ;
        RECT 30.070 108.025 30.325 108.765 ;
        RECT 27.265 107.235 27.435 107.830 ;
        RECT 27.605 107.405 28.395 107.650 ;
        RECT 28.565 107.625 29.155 107.830 ;
        RECT 29.365 107.525 29.955 107.855 ;
        RECT 27.265 106.805 27.470 107.235 ;
        RECT 27.640 106.890 29.365 107.235 ;
        RECT 29.535 107.060 29.900 107.525 ;
        RECT 30.125 107.355 30.325 108.025 ;
        RECT 27.640 106.635 29.890 106.890 ;
        RECT 27.560 106.265 29.890 106.635 ;
        RECT 30.070 106.475 30.325 107.355 ;
        RECT 31.105 108.000 31.580 108.905 ;
        RECT 31.760 108.610 33.730 109.655 ;
        RECT 31.760 108.180 33.205 108.610 ;
        RECT 31.105 107.830 32.995 108.000 ;
        RECT 33.375 107.855 33.740 108.440 ;
        RECT 33.910 108.025 34.165 109.655 ;
        RECT 31.105 107.235 31.275 107.830 ;
        RECT 31.445 107.405 32.235 107.650 ;
        RECT 32.405 107.625 32.995 107.830 ;
        RECT 33.205 107.525 33.795 107.855 ;
        RECT 31.105 106.805 31.310 107.235 ;
        RECT 31.480 106.890 33.205 107.235 ;
        RECT 33.375 107.060 33.740 107.525 ;
        RECT 33.965 107.355 34.165 108.025 ;
        RECT 31.480 106.635 33.730 106.890 ;
        RECT 31.400 106.265 33.730 106.635 ;
        RECT 33.910 106.475 34.165 107.355 ;
        RECT 34.465 108.000 34.940 108.905 ;
        RECT 35.120 108.610 37.090 109.655 ;
        RECT 35.120 108.180 36.565 108.610 ;
        RECT 34.465 107.830 36.355 108.000 ;
        RECT 36.735 107.855 37.100 108.440 ;
        RECT 37.270 108.025 37.525 109.655 ;
        RECT 34.465 107.235 34.635 107.830 ;
        RECT 34.805 107.405 35.595 107.650 ;
        RECT 35.765 107.625 36.355 107.830 ;
        RECT 36.565 107.525 37.155 107.855 ;
        RECT 34.465 106.805 34.670 107.235 ;
        RECT 34.840 106.890 36.565 107.235 ;
        RECT 36.735 107.060 37.100 107.525 ;
        RECT 37.325 107.355 37.525 108.025 ;
        RECT 34.840 106.635 37.090 106.890 ;
        RECT 34.760 106.265 37.090 106.635 ;
        RECT 37.270 106.475 37.525 107.355 ;
        RECT 37.825 108.000 38.300 108.905 ;
        RECT 38.480 108.610 40.450 109.655 ;
        RECT 38.480 108.180 39.925 108.610 ;
        RECT 37.825 107.830 39.715 108.000 ;
        RECT 40.095 107.855 40.460 108.440 ;
        RECT 40.630 108.025 40.885 109.655 ;
        RECT 40.685 107.915 40.885 108.025 ;
        RECT 37.825 107.235 37.995 107.830 ;
        RECT 38.165 107.405 38.955 107.650 ;
        RECT 39.125 107.625 39.715 107.830 ;
        RECT 39.925 107.525 40.515 107.855 ;
        RECT 40.685 107.745 40.915 107.915 ;
        RECT 37.825 106.805 38.030 107.235 ;
        RECT 38.200 106.890 39.925 107.235 ;
        RECT 40.095 107.060 40.460 107.525 ;
        RECT 40.685 107.355 40.885 107.745 ;
        RECT 38.200 106.635 40.450 106.890 ;
        RECT 38.120 106.265 40.450 106.635 ;
        RECT 40.630 106.475 40.885 107.355 ;
        RECT 27.090 105.815 41.010 105.985 ;
        RECT 27.560 105.165 29.890 105.535 ;
        RECT 27.265 104.565 27.470 104.995 ;
        RECT 27.640 104.910 29.890 105.165 ;
        RECT 27.640 104.565 29.365 104.910 ;
        RECT 27.265 103.970 27.435 104.565 ;
        RECT 27.605 104.150 28.395 104.395 ;
        RECT 29.535 104.275 29.900 104.740 ;
        RECT 30.070 104.445 30.325 105.325 ;
        RECT 30.920 105.165 33.250 105.535 ;
        RECT 28.565 103.970 29.155 104.175 ;
        RECT 27.265 103.800 29.155 103.970 ;
        RECT 29.365 103.945 29.955 104.275 ;
        RECT 27.265 102.895 27.740 103.800 ;
        RECT 27.920 103.190 29.365 103.620 ;
        RECT 29.535 103.360 29.900 103.945 ;
        RECT 30.125 103.775 30.325 104.445 ;
        RECT 27.920 102.145 29.890 103.190 ;
        RECT 30.070 102.815 30.325 103.775 ;
        RECT 30.625 104.565 30.830 104.995 ;
        RECT 31.000 104.910 33.250 105.165 ;
        RECT 31.000 104.565 32.725 104.910 ;
        RECT 30.625 103.970 30.795 104.565 ;
        RECT 30.965 104.150 31.755 104.395 ;
        RECT 32.895 104.275 33.260 104.740 ;
        RECT 33.430 104.445 33.685 105.325 ;
        RECT 34.280 105.165 36.610 105.535 ;
        RECT 31.925 103.970 32.515 104.175 ;
        RECT 30.625 103.800 32.515 103.970 ;
        RECT 32.725 103.945 33.315 104.275 ;
        RECT 30.625 102.895 31.100 103.800 ;
        RECT 31.280 103.190 32.725 103.620 ;
        RECT 32.895 103.360 33.260 103.945 ;
        RECT 33.485 103.775 33.685 104.445 ;
        RECT 30.070 102.645 30.375 102.815 ;
        RECT 30.070 102.145 30.325 102.645 ;
        RECT 31.280 102.145 33.250 103.190 ;
        RECT 33.430 102.145 33.685 103.775 ;
        RECT 33.985 104.565 34.190 104.995 ;
        RECT 34.360 104.910 36.610 105.165 ;
        RECT 34.360 104.565 36.085 104.910 ;
        RECT 33.985 103.970 34.155 104.565 ;
        RECT 34.325 104.150 35.115 104.395 ;
        RECT 36.255 104.275 36.620 104.740 ;
        RECT 36.790 104.445 37.045 105.325 ;
        RECT 35.285 103.970 35.875 104.175 ;
        RECT 33.985 103.800 35.875 103.970 ;
        RECT 36.085 103.945 36.675 104.275 ;
        RECT 33.985 102.895 34.460 103.800 ;
        RECT 34.640 103.190 36.085 103.620 ;
        RECT 36.255 103.360 36.620 103.945 ;
        RECT 36.845 103.775 37.045 104.445 ;
        RECT 100.075 104.005 100.245 123.895 ;
        RECT 102.145 123.515 102.315 124.110 ;
        RECT 102.485 123.685 103.275 123.930 ;
        RECT 103.445 123.905 104.035 124.110 ;
        RECT 104.245 123.805 104.835 124.135 ;
        RECT 102.145 123.085 102.350 123.515 ;
        RECT 102.520 123.170 104.245 123.515 ;
        RECT 104.415 123.340 104.780 123.805 ;
        RECT 105.005 123.635 105.205 124.305 ;
        RECT 102.520 122.915 104.770 123.170 ;
        RECT 102.440 122.545 104.770 122.915 ;
        RECT 104.950 122.755 105.205 123.635 ;
        RECT 105.505 124.280 105.980 125.185 ;
        RECT 106.160 124.890 108.130 125.935 ;
        RECT 106.160 124.460 107.605 124.890 ;
        RECT 105.505 124.110 107.395 124.280 ;
        RECT 107.775 124.135 108.140 124.720 ;
        RECT 108.310 124.305 108.565 125.935 ;
        RECT 105.505 123.515 105.675 124.110 ;
        RECT 105.845 123.685 106.635 123.930 ;
        RECT 106.805 123.905 107.395 124.110 ;
        RECT 107.605 123.805 108.195 124.135 ;
        RECT 105.505 123.085 105.710 123.515 ;
        RECT 105.880 123.170 107.605 123.515 ;
        RECT 107.775 123.340 108.140 123.805 ;
        RECT 108.365 123.635 108.565 124.305 ;
        RECT 108.310 123.215 108.565 123.635 ;
        RECT 108.865 124.280 109.340 125.185 ;
        RECT 109.520 124.890 111.490 125.935 ;
        RECT 109.520 124.460 110.965 124.890 ;
        RECT 108.865 124.110 110.755 124.280 ;
        RECT 111.135 124.135 111.500 124.720 ;
        RECT 111.670 124.575 111.925 125.935 ;
        RECT 111.670 124.405 111.975 124.575 ;
        RECT 111.670 124.305 111.925 124.405 ;
        RECT 108.865 123.515 109.035 124.110 ;
        RECT 109.205 123.685 109.995 123.930 ;
        RECT 110.165 123.905 110.755 124.110 ;
        RECT 110.965 123.805 111.555 124.135 ;
        RECT 105.880 122.915 108.130 123.170 ;
        RECT 105.800 122.545 108.130 122.915 ;
        RECT 108.310 123.045 108.575 123.215 ;
        RECT 108.865 123.085 109.070 123.515 ;
        RECT 109.240 123.170 110.965 123.515 ;
        RECT 111.135 123.340 111.500 123.805 ;
        RECT 111.725 123.635 111.925 124.305 ;
        RECT 108.310 122.755 108.565 123.045 ;
        RECT 109.240 122.915 111.490 123.170 ;
        RECT 109.160 122.545 111.490 122.915 ;
        RECT 111.670 122.755 111.925 123.635 ;
        RECT 100.530 122.095 112.050 122.265 ;
        RECT 101.000 121.445 103.330 121.815 ;
        RECT 100.705 120.845 100.910 121.275 ;
        RECT 101.080 121.190 103.330 121.445 ;
        RECT 101.080 120.845 102.805 121.190 ;
        RECT 103.510 121.175 103.765 121.605 ;
        RECT 105.320 121.445 107.650 121.815 ;
        RECT 100.705 120.250 100.875 120.845 ;
        RECT 101.045 120.430 101.835 120.675 ;
        RECT 102.975 120.555 103.340 121.020 ;
        RECT 103.510 121.005 103.815 121.175 ;
        RECT 103.510 120.725 103.765 121.005 ;
        RECT 102.005 120.250 102.595 120.455 ;
        RECT 100.705 120.080 102.595 120.250 ;
        RECT 102.805 120.225 103.395 120.555 ;
        RECT 100.705 119.175 101.180 120.080 ;
        RECT 101.360 119.470 102.805 119.900 ;
        RECT 102.975 119.640 103.340 120.225 ;
        RECT 103.565 120.055 103.765 120.725 ;
        RECT 101.360 118.425 103.330 119.470 ;
        RECT 103.510 118.425 103.765 120.055 ;
        RECT 105.025 120.845 105.230 121.275 ;
        RECT 105.400 121.190 107.650 121.445 ;
        RECT 105.400 120.845 107.125 121.190 ;
        RECT 105.025 120.250 105.195 120.845 ;
        RECT 105.365 120.430 106.155 120.675 ;
        RECT 107.295 120.555 107.660 121.020 ;
        RECT 107.830 120.725 108.085 121.605 ;
        RECT 108.680 121.445 111.010 121.815 ;
        RECT 106.325 120.250 106.915 120.455 ;
        RECT 105.025 120.080 106.915 120.250 ;
        RECT 107.125 120.225 107.715 120.555 ;
        RECT 105.025 119.175 105.500 120.080 ;
        RECT 105.680 119.470 107.125 119.900 ;
        RECT 107.295 119.640 107.660 120.225 ;
        RECT 107.885 120.055 108.085 120.725 ;
        RECT 105.680 118.425 107.650 119.470 ;
        RECT 107.830 118.425 108.085 120.055 ;
        RECT 108.385 120.845 108.590 121.275 ;
        RECT 108.760 121.190 111.010 121.445 ;
        RECT 108.760 120.845 110.485 121.190 ;
        RECT 111.190 121.175 111.445 121.605 ;
        RECT 108.385 120.250 108.555 120.845 ;
        RECT 108.725 120.430 109.515 120.675 ;
        RECT 110.655 120.555 111.020 121.020 ;
        RECT 111.190 121.005 111.465 121.175 ;
        RECT 111.190 120.725 111.445 121.005 ;
        RECT 109.685 120.250 110.275 120.455 ;
        RECT 108.385 120.080 110.275 120.250 ;
        RECT 110.485 120.225 111.075 120.555 ;
        RECT 108.385 119.175 108.860 120.080 ;
        RECT 109.040 119.470 110.485 119.900 ;
        RECT 110.655 119.640 111.020 120.225 ;
        RECT 111.245 120.055 111.445 120.725 ;
        RECT 109.040 118.425 111.010 119.470 ;
        RECT 111.190 118.425 111.445 120.055 ;
        RECT 100.530 118.025 111.570 118.195 ;
        RECT 101.665 116.140 102.140 117.045 ;
        RECT 102.320 116.750 104.290 117.795 ;
        RECT 102.320 116.320 103.765 116.750 ;
        RECT 101.665 115.970 103.555 116.140 ;
        RECT 103.935 116.075 104.300 116.580 ;
        RECT 104.470 116.165 104.725 117.795 ;
        RECT 103.815 115.995 104.300 116.075 ;
        RECT 101.665 115.375 101.835 115.970 ;
        RECT 102.005 115.545 102.795 115.790 ;
        RECT 102.965 115.765 103.555 115.970 ;
        RECT 103.765 115.665 104.355 115.995 ;
        RECT 101.665 114.945 101.870 115.375 ;
        RECT 102.040 115.030 103.765 115.375 ;
        RECT 103.935 115.200 104.300 115.665 ;
        RECT 104.525 115.495 104.725 116.165 ;
        RECT 102.040 114.775 104.290 115.030 ;
        RECT 101.960 114.405 104.290 114.775 ;
        RECT 104.470 114.615 104.725 115.495 ;
        RECT 105.025 116.140 105.500 117.045 ;
        RECT 105.680 116.750 107.650 117.795 ;
        RECT 105.680 116.320 107.125 116.750 ;
        RECT 105.025 115.970 106.915 116.140 ;
        RECT 107.295 116.075 107.660 116.580 ;
        RECT 107.830 116.165 108.085 117.795 ;
        RECT 107.215 115.995 107.660 116.075 ;
        RECT 105.025 115.375 105.195 115.970 ;
        RECT 105.365 115.545 106.155 115.790 ;
        RECT 106.325 115.765 106.915 115.970 ;
        RECT 107.125 115.665 107.715 115.995 ;
        RECT 105.025 114.945 105.230 115.375 ;
        RECT 105.400 115.030 107.125 115.375 ;
        RECT 107.295 115.200 107.660 115.665 ;
        RECT 107.885 115.495 108.085 116.165 ;
        RECT 105.400 114.775 107.650 115.030 ;
        RECT 105.320 114.405 107.650 114.775 ;
        RECT 107.830 114.615 108.085 115.495 ;
        RECT 108.385 116.140 108.860 117.045 ;
        RECT 109.040 116.750 111.010 117.795 ;
        RECT 111.190 117.095 111.445 117.795 ;
        RECT 111.190 116.925 111.465 117.095 ;
        RECT 109.040 116.320 110.485 116.750 ;
        RECT 108.385 115.970 110.275 116.140 ;
        RECT 110.655 116.075 111.020 116.580 ;
        RECT 111.190 116.165 111.445 116.925 ;
        RECT 110.615 115.995 111.020 116.075 ;
        RECT 108.385 115.375 108.555 115.970 ;
        RECT 108.725 115.545 109.515 115.790 ;
        RECT 109.685 115.765 110.275 115.970 ;
        RECT 110.485 115.665 111.075 115.995 ;
        RECT 108.385 114.945 108.590 115.375 ;
        RECT 108.760 115.030 110.485 115.375 ;
        RECT 110.655 115.200 111.020 115.665 ;
        RECT 111.245 115.495 111.445 116.165 ;
        RECT 108.760 114.775 111.010 115.030 ;
        RECT 108.680 114.405 111.010 114.775 ;
        RECT 111.190 114.615 111.445 115.495 ;
        RECT 101.010 113.955 111.570 114.125 ;
        RECT 101.480 113.305 103.810 113.675 ;
        RECT 101.185 112.705 101.390 113.135 ;
        RECT 101.560 113.050 103.810 113.305 ;
        RECT 101.560 112.705 103.285 113.050 ;
        RECT 101.185 112.110 101.355 112.705 ;
        RECT 101.525 112.290 102.315 112.535 ;
        RECT 103.455 112.415 103.820 112.880 ;
        RECT 103.990 112.585 104.245 113.465 ;
        RECT 105.320 113.305 107.650 113.675 ;
        RECT 102.485 112.110 103.075 112.315 ;
        RECT 101.185 111.940 103.075 112.110 ;
        RECT 103.285 112.085 103.875 112.415 ;
        RECT 101.185 111.035 101.660 111.940 ;
        RECT 101.840 111.330 103.285 111.760 ;
        RECT 103.455 111.500 103.820 112.085 ;
        RECT 104.045 111.915 104.245 112.585 ;
        RECT 101.840 110.285 103.810 111.330 ;
        RECT 103.990 110.975 104.245 111.915 ;
        RECT 105.025 112.705 105.230 113.135 ;
        RECT 105.400 113.050 107.650 113.305 ;
        RECT 105.400 112.705 107.125 113.050 ;
        RECT 105.025 112.110 105.195 112.705 ;
        RECT 105.365 112.290 106.155 112.535 ;
        RECT 107.295 112.415 107.660 112.880 ;
        RECT 107.830 112.585 108.085 113.465 ;
        RECT 108.680 113.305 111.010 113.675 ;
        RECT 106.325 112.110 106.915 112.315 ;
        RECT 105.025 111.940 106.915 112.110 ;
        RECT 107.125 112.085 107.715 112.415 ;
        RECT 105.025 111.035 105.500 111.940 ;
        RECT 105.680 111.330 107.125 111.760 ;
        RECT 107.295 111.500 107.660 112.085 ;
        RECT 107.885 111.915 108.085 112.585 ;
        RECT 103.990 110.805 104.325 110.975 ;
        RECT 103.990 110.285 104.245 110.805 ;
        RECT 105.680 110.285 107.650 111.330 ;
        RECT 107.830 110.285 108.085 111.915 ;
        RECT 108.385 112.705 108.590 113.135 ;
        RECT 108.760 113.050 111.010 113.305 ;
        RECT 108.760 112.705 110.485 113.050 ;
        RECT 111.190 113.015 111.445 113.465 ;
        RECT 108.385 112.110 108.555 112.705 ;
        RECT 108.725 112.290 109.515 112.535 ;
        RECT 110.655 112.415 111.020 112.880 ;
        RECT 111.190 112.845 111.465 113.015 ;
        RECT 111.190 112.585 111.445 112.845 ;
        RECT 109.685 112.110 110.275 112.315 ;
        RECT 108.385 111.940 110.275 112.110 ;
        RECT 110.485 112.085 111.075 112.415 ;
        RECT 108.385 111.035 108.860 111.940 ;
        RECT 109.040 111.330 110.485 111.760 ;
        RECT 110.655 111.500 111.020 112.085 ;
        RECT 111.245 111.915 111.445 112.585 ;
        RECT 109.040 110.285 111.010 111.330 ;
        RECT 111.190 110.285 111.445 111.915 ;
        RECT 100.530 109.885 111.570 110.055 ;
        RECT 100.705 108.000 101.180 108.905 ;
        RECT 101.360 108.610 103.330 109.655 ;
        RECT 103.510 108.935 103.765 109.655 ;
        RECT 103.510 108.765 103.815 108.935 ;
        RECT 101.360 108.180 102.805 108.610 ;
        RECT 100.705 107.830 102.595 108.000 ;
        RECT 102.975 107.855 103.340 108.440 ;
        RECT 103.510 108.025 103.765 108.765 ;
        RECT 100.705 107.235 100.875 107.830 ;
        RECT 101.045 107.405 101.835 107.650 ;
        RECT 102.005 107.625 102.595 107.830 ;
        RECT 102.805 107.525 103.395 107.855 ;
        RECT 100.705 106.805 100.910 107.235 ;
        RECT 101.080 106.890 102.805 107.235 ;
        RECT 102.975 107.060 103.340 107.525 ;
        RECT 103.565 107.355 103.765 108.025 ;
        RECT 101.080 106.635 103.330 106.890 ;
        RECT 101.000 106.265 103.330 106.635 ;
        RECT 103.510 106.475 103.765 107.355 ;
        RECT 104.545 108.000 105.020 108.905 ;
        RECT 105.200 108.610 107.170 109.655 ;
        RECT 105.200 108.180 106.645 108.610 ;
        RECT 104.545 107.830 106.435 108.000 ;
        RECT 106.815 107.855 107.180 108.440 ;
        RECT 107.350 108.025 107.605 109.655 ;
        RECT 104.545 107.235 104.715 107.830 ;
        RECT 104.885 107.405 105.675 107.650 ;
        RECT 105.845 107.625 106.435 107.830 ;
        RECT 106.645 107.525 107.235 107.855 ;
        RECT 104.545 106.805 104.750 107.235 ;
        RECT 104.920 106.890 106.645 107.235 ;
        RECT 106.815 107.060 107.180 107.525 ;
        RECT 107.405 107.355 107.605 108.025 ;
        RECT 104.920 106.635 107.170 106.890 ;
        RECT 104.840 106.265 107.170 106.635 ;
        RECT 107.350 106.475 107.605 107.355 ;
        RECT 107.905 108.000 108.380 108.905 ;
        RECT 108.560 108.610 110.530 109.655 ;
        RECT 108.560 108.180 110.005 108.610 ;
        RECT 107.905 107.830 109.795 108.000 ;
        RECT 110.175 107.855 110.540 108.440 ;
        RECT 110.710 108.025 110.965 109.655 ;
        RECT 107.905 107.235 108.075 107.830 ;
        RECT 108.245 107.405 109.035 107.650 ;
        RECT 109.205 107.625 109.795 107.830 ;
        RECT 110.005 107.525 110.595 107.855 ;
        RECT 107.905 106.805 108.110 107.235 ;
        RECT 108.280 106.890 110.005 107.235 ;
        RECT 110.175 107.060 110.540 107.525 ;
        RECT 110.765 107.355 110.965 108.025 ;
        RECT 108.280 106.635 110.530 106.890 ;
        RECT 108.200 106.265 110.530 106.635 ;
        RECT 110.710 106.475 110.965 107.355 ;
        RECT 100.530 105.815 111.570 105.985 ;
        RECT 101.960 105.165 104.290 105.535 ;
        RECT 101.665 104.565 101.870 104.995 ;
        RECT 102.040 104.910 104.290 105.165 ;
        RECT 102.040 104.565 103.765 104.910 ;
        RECT 34.640 102.145 36.610 103.190 ;
        RECT 36.790 102.145 37.045 103.775 ;
        RECT 101.665 103.970 101.835 104.565 ;
        RECT 102.005 104.150 102.795 104.395 ;
        RECT 103.935 104.275 104.300 104.740 ;
        RECT 104.470 104.445 104.725 105.325 ;
        RECT 105.320 105.165 107.650 105.535 ;
        RECT 102.965 103.970 103.555 104.175 ;
        RECT 101.665 103.800 103.555 103.970 ;
        RECT 103.765 103.945 104.355 104.275 ;
        RECT 101.665 102.895 102.140 103.800 ;
        RECT 102.320 103.190 103.765 103.620 ;
        RECT 103.935 103.360 104.300 103.945 ;
        RECT 104.525 103.775 104.725 104.445 ;
        RECT 102.320 102.145 104.290 103.190 ;
        RECT 104.470 102.145 104.725 103.775 ;
        RECT 105.025 104.565 105.230 104.995 ;
        RECT 105.400 104.910 107.650 105.165 ;
        RECT 105.400 104.565 107.125 104.910 ;
        RECT 105.025 103.970 105.195 104.565 ;
        RECT 105.365 104.150 106.155 104.395 ;
        RECT 107.295 104.275 107.660 104.740 ;
        RECT 107.830 104.445 108.085 105.325 ;
        RECT 108.680 105.165 111.010 105.535 ;
        RECT 106.325 103.970 106.915 104.175 ;
        RECT 105.025 103.800 106.915 103.970 ;
        RECT 107.125 103.945 107.715 104.275 ;
        RECT 105.025 102.895 105.500 103.800 ;
        RECT 105.680 103.190 107.125 103.620 ;
        RECT 107.295 103.360 107.660 103.945 ;
        RECT 107.885 103.775 108.085 104.445 ;
        RECT 105.680 102.145 107.650 103.190 ;
        RECT 107.830 102.145 108.085 103.775 ;
        RECT 108.385 104.565 108.590 104.995 ;
        RECT 108.760 104.910 111.010 105.165 ;
        RECT 108.760 104.565 110.485 104.910 ;
        RECT 108.385 103.970 108.555 104.565 ;
        RECT 108.725 104.150 109.515 104.395 ;
        RECT 110.655 104.275 111.020 104.740 ;
        RECT 111.190 104.445 111.445 105.325 ;
        RECT 109.685 103.970 110.275 104.175 ;
        RECT 108.385 103.800 110.275 103.970 ;
        RECT 110.485 103.945 111.075 104.275 ;
        RECT 108.385 102.895 108.860 103.800 ;
        RECT 109.040 103.190 110.485 103.620 ;
        RECT 110.655 103.360 111.020 103.945 ;
        RECT 111.245 103.775 111.445 104.445 ;
        RECT 109.040 102.145 111.010 103.190 ;
        RECT 111.190 103.155 111.445 103.775 ;
        RECT 111.190 102.985 111.465 103.155 ;
        RECT 111.190 102.145 111.445 102.985 ;
        RECT 27.090 101.745 37.170 101.915 ;
        RECT 97.650 101.745 111.570 101.915 ;
        RECT 27.265 99.860 27.740 100.765 ;
        RECT 27.920 100.470 29.890 101.515 ;
        RECT 30.070 100.775 30.325 101.515 ;
        RECT 30.070 100.605 30.375 100.775 ;
        RECT 27.920 100.040 29.365 100.470 ;
        RECT 27.265 99.690 29.155 99.860 ;
        RECT 29.535 99.715 29.900 100.300 ;
        RECT 30.070 99.885 30.325 100.605 ;
        RECT 27.265 99.095 27.435 99.690 ;
        RECT 27.605 99.265 28.395 99.510 ;
        RECT 28.565 99.485 29.155 99.690 ;
        RECT 29.365 99.385 29.955 99.715 ;
        RECT 27.265 98.665 27.470 99.095 ;
        RECT 27.640 98.750 29.365 99.095 ;
        RECT 29.535 98.920 29.900 99.385 ;
        RECT 30.125 99.215 30.325 99.885 ;
        RECT 27.640 98.495 29.890 98.750 ;
        RECT 27.560 98.125 29.890 98.495 ;
        RECT 30.070 98.335 30.325 99.215 ;
        RECT 33.025 99.860 33.500 100.765 ;
        RECT 33.680 100.470 35.650 101.515 ;
        RECT 35.830 100.775 36.085 101.515 ;
        RECT 35.830 100.605 36.155 100.775 ;
        RECT 33.680 100.040 35.125 100.470 ;
        RECT 33.025 99.690 34.915 99.860 ;
        RECT 35.295 99.715 35.660 100.300 ;
        RECT 35.830 99.885 36.085 100.605 ;
        RECT 33.025 99.095 33.195 99.690 ;
        RECT 33.365 99.265 34.155 99.510 ;
        RECT 34.325 99.485 34.915 99.690 ;
        RECT 35.125 99.385 35.715 99.715 ;
        RECT 33.025 98.665 33.230 99.095 ;
        RECT 33.400 98.750 35.125 99.095 ;
        RECT 35.295 98.920 35.660 99.385 ;
        RECT 35.885 99.215 36.085 99.885 ;
        RECT 33.400 98.495 35.650 98.750 ;
        RECT 33.320 98.125 35.650 98.495 ;
        RECT 35.830 98.335 36.085 99.215 ;
        RECT 97.825 99.860 98.300 100.765 ;
        RECT 98.480 100.470 100.450 101.515 ;
        RECT 98.480 100.040 99.925 100.470 ;
        RECT 97.825 99.690 99.715 99.860 ;
        RECT 100.095 99.715 100.460 100.300 ;
        RECT 100.630 99.885 100.885 101.515 ;
        RECT 97.825 99.095 97.995 99.690 ;
        RECT 98.165 99.265 98.955 99.510 ;
        RECT 99.125 99.485 99.715 99.690 ;
        RECT 99.925 99.385 100.515 99.715 ;
        RECT 97.825 98.665 98.030 99.095 ;
        RECT 98.200 98.750 99.925 99.095 ;
        RECT 100.095 98.920 100.460 99.385 ;
        RECT 100.685 99.215 100.885 99.885 ;
        RECT 100.630 99.075 100.885 99.215 ;
        RECT 101.185 99.860 101.660 100.765 ;
        RECT 101.840 100.470 103.810 101.515 ;
        RECT 101.840 100.040 103.285 100.470 ;
        RECT 101.185 99.690 103.075 99.860 ;
        RECT 103.455 99.715 103.820 100.300 ;
        RECT 103.990 99.885 104.245 101.515 ;
        RECT 101.185 99.095 101.355 99.690 ;
        RECT 101.525 99.265 102.315 99.510 ;
        RECT 102.485 99.485 103.075 99.690 ;
        RECT 103.285 99.385 103.875 99.715 ;
        RECT 100.630 98.905 100.925 99.075 ;
        RECT 98.200 98.495 100.450 98.750 ;
        RECT 98.120 98.125 100.450 98.495 ;
        RECT 100.630 98.335 100.885 98.905 ;
        RECT 101.185 98.665 101.390 99.095 ;
        RECT 101.560 98.750 103.285 99.095 ;
        RECT 103.455 98.920 103.820 99.385 ;
        RECT 104.045 99.215 104.245 99.885 ;
        RECT 103.990 99.075 104.245 99.215 ;
        RECT 104.545 99.860 105.020 100.765 ;
        RECT 105.200 100.470 107.170 101.515 ;
        RECT 105.200 100.040 106.645 100.470 ;
        RECT 104.545 99.690 106.435 99.860 ;
        RECT 106.815 99.715 107.180 100.300 ;
        RECT 107.350 99.885 107.605 101.515 ;
        RECT 104.545 99.095 104.715 99.690 ;
        RECT 104.885 99.265 105.675 99.510 ;
        RECT 105.845 99.485 106.435 99.690 ;
        RECT 106.645 99.385 107.235 99.715 ;
        RECT 103.990 98.905 104.325 99.075 ;
        RECT 101.560 98.495 103.810 98.750 ;
        RECT 101.480 98.125 103.810 98.495 ;
        RECT 103.990 98.335 104.245 98.905 ;
        RECT 104.545 98.665 104.750 99.095 ;
        RECT 104.920 98.750 106.645 99.095 ;
        RECT 106.815 98.920 107.180 99.385 ;
        RECT 107.405 99.215 107.605 99.885 ;
        RECT 104.920 98.495 107.170 98.750 ;
        RECT 104.840 98.125 107.170 98.495 ;
        RECT 107.350 98.335 107.605 99.215 ;
        RECT 107.905 99.860 108.380 100.765 ;
        RECT 108.560 100.470 110.530 101.515 ;
        RECT 108.560 100.040 110.005 100.470 ;
        RECT 107.905 99.690 109.795 99.860 ;
        RECT 110.175 99.715 110.540 100.300 ;
        RECT 110.710 99.885 110.965 101.515 ;
        RECT 107.905 99.095 108.075 99.690 ;
        RECT 108.245 99.265 109.035 99.510 ;
        RECT 109.205 99.485 109.795 99.690 ;
        RECT 110.005 99.385 110.595 99.715 ;
        RECT 107.905 98.665 108.110 99.095 ;
        RECT 108.280 98.750 110.005 99.095 ;
        RECT 110.175 98.920 110.540 99.385 ;
        RECT 110.765 99.215 110.965 99.885 ;
        RECT 108.280 98.495 110.530 98.750 ;
        RECT 108.200 98.125 110.530 98.495 ;
        RECT 110.710 98.335 110.965 99.215 ;
        RECT 27.090 97.675 43.890 97.845 ;
        RECT 97.650 97.675 111.570 97.845 ;
        RECT 27.560 97.025 29.890 97.395 ;
        RECT 27.265 96.425 27.470 96.855 ;
        RECT 27.640 96.770 29.890 97.025 ;
        RECT 27.640 96.425 29.365 96.770 ;
        RECT 27.265 95.830 27.435 96.425 ;
        RECT 27.605 96.010 28.395 96.255 ;
        RECT 29.535 96.135 29.900 96.600 ;
        RECT 30.070 96.305 30.325 97.185 ;
        RECT 30.920 97.025 33.250 97.395 ;
        RECT 28.565 95.830 29.155 96.035 ;
        RECT 27.265 95.660 29.155 95.830 ;
        RECT 29.365 95.805 29.955 96.135 ;
        RECT 27.265 94.755 27.740 95.660 ;
        RECT 27.920 95.050 29.365 95.480 ;
        RECT 29.535 95.220 29.900 95.805 ;
        RECT 30.125 95.635 30.325 96.305 ;
        RECT 27.920 94.005 29.890 95.050 ;
        RECT 30.070 94.995 30.325 95.635 ;
        RECT 30.625 96.425 30.830 96.855 ;
        RECT 31.000 96.770 33.250 97.025 ;
        RECT 31.000 96.425 32.725 96.770 ;
        RECT 30.625 95.830 30.795 96.425 ;
        RECT 30.965 96.010 31.755 96.255 ;
        RECT 32.895 96.135 33.260 96.600 ;
        RECT 33.430 96.305 33.685 97.185 ;
        RECT 34.280 97.025 36.610 97.395 ;
        RECT 31.925 95.830 32.515 96.035 ;
        RECT 30.625 95.660 32.515 95.830 ;
        RECT 32.725 95.805 33.315 96.135 ;
        RECT 30.070 94.825 30.375 94.995 ;
        RECT 30.070 94.005 30.325 94.825 ;
        RECT 30.625 94.755 31.100 95.660 ;
        RECT 31.280 95.050 32.725 95.480 ;
        RECT 32.895 95.220 33.260 95.805 ;
        RECT 33.485 95.635 33.685 96.305 ;
        RECT 31.280 94.005 33.250 95.050 ;
        RECT 33.430 94.005 33.685 95.635 ;
        RECT 33.985 96.425 34.190 96.855 ;
        RECT 34.360 96.770 36.610 97.025 ;
        RECT 34.360 96.425 36.085 96.770 ;
        RECT 33.985 95.830 34.155 96.425 ;
        RECT 34.325 96.010 35.115 96.255 ;
        RECT 36.255 96.135 36.620 96.600 ;
        RECT 36.790 96.305 37.045 97.185 ;
        RECT 37.640 97.025 39.970 97.395 ;
        RECT 35.285 95.830 35.875 96.035 ;
        RECT 33.985 95.660 35.875 95.830 ;
        RECT 36.085 95.805 36.675 96.135 ;
        RECT 33.985 94.755 34.460 95.660 ;
        RECT 34.640 95.050 36.085 95.480 ;
        RECT 36.255 95.220 36.620 95.805 ;
        RECT 36.845 95.635 37.045 96.305 ;
        RECT 34.640 94.005 36.610 95.050 ;
        RECT 36.790 94.005 37.045 95.635 ;
        RECT 37.345 96.425 37.550 96.855 ;
        RECT 37.720 96.770 39.970 97.025 ;
        RECT 37.720 96.425 39.445 96.770 ;
        RECT 37.345 95.830 37.515 96.425 ;
        RECT 37.685 96.010 38.475 96.255 ;
        RECT 39.615 96.135 39.980 96.600 ;
        RECT 40.150 96.305 40.405 97.185 ;
        RECT 41.000 97.025 43.330 97.395 ;
        RECT 38.645 95.830 39.235 96.035 ;
        RECT 37.345 95.660 39.235 95.830 ;
        RECT 39.445 95.805 40.035 96.135 ;
        RECT 37.345 94.755 37.820 95.660 ;
        RECT 38.000 95.050 39.445 95.480 ;
        RECT 39.615 95.220 39.980 95.805 ;
        RECT 40.205 95.635 40.405 96.305 ;
        RECT 38.000 94.005 39.970 95.050 ;
        RECT 40.150 94.005 40.405 95.635 ;
        RECT 40.705 96.425 40.910 96.855 ;
        RECT 41.080 96.770 43.330 97.025 ;
        RECT 41.080 96.425 42.805 96.770 ;
        RECT 40.705 95.830 40.875 96.425 ;
        RECT 41.045 96.010 41.835 96.255 ;
        RECT 42.975 96.135 43.340 96.600 ;
        RECT 43.510 96.305 43.765 97.185 ;
        RECT 100.040 97.025 102.370 97.395 ;
        RECT 42.005 95.830 42.595 96.035 ;
        RECT 40.705 95.660 42.595 95.830 ;
        RECT 42.805 95.805 43.395 96.135 ;
        RECT 40.705 94.755 41.180 95.660 ;
        RECT 41.360 95.050 42.805 95.480 ;
        RECT 42.975 95.220 43.340 95.805 ;
        RECT 43.565 95.635 43.765 96.305 ;
        RECT 99.745 96.425 99.950 96.855 ;
        RECT 100.120 96.770 102.370 97.025 ;
        RECT 100.120 96.425 101.845 96.770 ;
        RECT 43.510 95.335 43.765 95.635 ;
        RECT 43.510 95.165 43.805 95.335 ;
        RECT 41.360 94.005 43.330 95.050 ;
        RECT 43.510 94.005 43.765 95.165 ;
        RECT 26.130 93.605 43.890 93.775 ;
        RECT 26.305 91.720 26.780 92.625 ;
        RECT 26.960 92.330 28.930 93.375 ;
        RECT 26.960 91.900 28.405 92.330 ;
        RECT 26.305 91.550 28.195 91.720 ;
        RECT 28.575 91.575 28.940 92.160 ;
        RECT 29.110 91.745 29.365 93.375 ;
        RECT 26.305 90.955 26.475 91.550 ;
        RECT 26.645 91.125 27.435 91.370 ;
        RECT 27.605 91.345 28.195 91.550 ;
        RECT 28.405 91.245 28.995 91.575 ;
        RECT 26.305 90.525 26.510 90.955 ;
        RECT 26.680 90.610 28.405 90.955 ;
        RECT 28.575 90.780 28.940 91.245 ;
        RECT 29.165 91.075 29.365 91.745 ;
        RECT 26.680 90.355 28.930 90.610 ;
        RECT 26.600 89.985 28.930 90.355 ;
        RECT 29.110 90.195 29.365 91.075 ;
        RECT 29.665 91.720 30.140 92.625 ;
        RECT 30.320 92.330 32.290 93.375 ;
        RECT 32.470 92.615 32.725 93.375 ;
        RECT 32.470 92.445 32.755 92.615 ;
        RECT 30.320 91.900 31.765 92.330 ;
        RECT 29.665 91.550 31.555 91.720 ;
        RECT 31.935 91.575 32.300 92.160 ;
        RECT 32.470 91.745 32.725 92.445 ;
        RECT 29.665 90.955 29.835 91.550 ;
        RECT 30.005 91.125 30.795 91.370 ;
        RECT 30.965 91.345 31.555 91.550 ;
        RECT 31.765 91.245 32.355 91.575 ;
        RECT 29.665 90.525 29.870 90.955 ;
        RECT 30.040 90.610 31.765 90.955 ;
        RECT 31.935 90.780 32.300 91.245 ;
        RECT 32.525 91.075 32.725 91.745 ;
        RECT 30.040 90.355 32.290 90.610 ;
        RECT 29.960 89.985 32.290 90.355 ;
        RECT 32.470 90.195 32.725 91.075 ;
        RECT 33.025 91.720 33.500 92.625 ;
        RECT 33.680 92.330 35.650 93.375 ;
        RECT 33.680 91.900 35.125 92.330 ;
        RECT 33.025 91.550 34.915 91.720 ;
        RECT 35.295 91.575 35.660 92.160 ;
        RECT 35.830 91.745 36.085 93.375 ;
        RECT 33.025 90.955 33.195 91.550 ;
        RECT 33.365 91.125 34.155 91.370 ;
        RECT 34.325 91.345 34.915 91.550 ;
        RECT 35.125 91.245 35.715 91.575 ;
        RECT 33.025 90.525 33.230 90.955 ;
        RECT 33.400 90.610 35.125 90.955 ;
        RECT 35.295 90.780 35.660 91.245 ;
        RECT 35.885 91.075 36.085 91.745 ;
        RECT 35.830 90.915 36.085 91.075 ;
        RECT 36.385 91.720 36.860 92.625 ;
        RECT 37.040 92.330 39.010 93.375 ;
        RECT 37.040 91.900 38.485 92.330 ;
        RECT 36.385 91.550 38.275 91.720 ;
        RECT 38.655 91.595 39.020 92.160 ;
        RECT 39.190 91.745 39.445 93.375 ;
        RECT 38.655 91.575 39.045 91.595 ;
        RECT 36.385 90.955 36.555 91.550 ;
        RECT 36.725 91.125 37.515 91.370 ;
        RECT 37.685 91.345 38.275 91.550 ;
        RECT 38.485 91.245 39.075 91.575 ;
        RECT 35.830 90.745 36.155 90.915 ;
        RECT 33.400 90.355 35.650 90.610 ;
        RECT 33.320 89.985 35.650 90.355 ;
        RECT 35.830 90.195 36.085 90.745 ;
        RECT 36.385 90.525 36.590 90.955 ;
        RECT 36.760 90.610 38.485 90.955 ;
        RECT 38.655 90.780 39.020 91.245 ;
        RECT 39.245 91.075 39.445 91.745 ;
        RECT 36.760 90.355 39.010 90.610 ;
        RECT 36.680 89.985 39.010 90.355 ;
        RECT 39.190 90.195 39.445 91.075 ;
        RECT 39.745 91.720 40.220 92.625 ;
        RECT 40.400 92.330 42.370 93.375 ;
        RECT 40.400 91.900 41.845 92.330 ;
        RECT 39.745 91.550 41.635 91.720 ;
        RECT 42.015 91.595 42.380 92.160 ;
        RECT 42.550 91.745 42.805 93.375 ;
        RECT 41.935 91.575 42.380 91.595 ;
        RECT 39.745 90.955 39.915 91.550 ;
        RECT 40.085 91.125 40.875 91.370 ;
        RECT 41.045 91.345 41.635 91.550 ;
        RECT 41.845 91.245 42.435 91.575 ;
        RECT 39.745 90.525 39.950 90.955 ;
        RECT 40.120 90.610 41.845 90.955 ;
        RECT 42.015 90.780 42.380 91.245 ;
        RECT 42.605 91.075 42.805 91.745 ;
        RECT 44.315 91.425 44.485 96.015 ;
        RECT 99.745 95.830 99.915 96.425 ;
        RECT 100.085 96.010 100.875 96.255 ;
        RECT 102.015 96.135 102.380 96.600 ;
        RECT 102.550 96.305 102.805 97.185 ;
        RECT 103.400 97.025 105.730 97.395 ;
        RECT 101.045 95.830 101.635 96.035 ;
        RECT 99.745 95.660 101.635 95.830 ;
        RECT 101.845 95.805 102.435 96.135 ;
        RECT 99.745 94.755 100.220 95.660 ;
        RECT 100.400 95.050 101.845 95.480 ;
        RECT 102.015 95.220 102.380 95.805 ;
        RECT 102.605 95.635 102.805 96.305 ;
        RECT 100.400 94.005 102.370 95.050 ;
        RECT 102.550 94.005 102.805 95.635 ;
        RECT 103.105 96.425 103.310 96.855 ;
        RECT 103.480 96.770 105.730 97.025 ;
        RECT 103.480 96.425 105.205 96.770 ;
        RECT 103.105 95.830 103.275 96.425 ;
        RECT 103.445 96.010 104.235 96.255 ;
        RECT 105.375 96.135 105.740 96.600 ;
        RECT 105.910 96.305 106.165 97.185 ;
        RECT 108.680 97.025 111.010 97.395 ;
        RECT 104.405 95.830 104.995 96.035 ;
        RECT 103.105 95.660 104.995 95.830 ;
        RECT 105.205 95.805 105.795 96.135 ;
        RECT 103.105 94.755 103.580 95.660 ;
        RECT 103.760 95.050 105.205 95.480 ;
        RECT 105.375 95.220 105.740 95.805 ;
        RECT 105.965 95.635 106.165 96.305 ;
        RECT 105.910 95.335 106.165 95.635 ;
        RECT 108.385 96.425 108.590 96.855 ;
        RECT 108.760 96.770 111.010 97.025 ;
        RECT 108.760 96.425 110.485 96.770 ;
        RECT 108.385 95.830 108.555 96.425 ;
        RECT 108.725 96.010 109.515 96.255 ;
        RECT 110.655 96.135 111.020 96.600 ;
        RECT 111.190 96.305 111.445 97.185 ;
        RECT 109.685 95.830 110.275 96.035 ;
        RECT 108.385 95.660 110.275 95.830 ;
        RECT 110.485 95.805 111.075 96.135 ;
        RECT 105.910 95.165 106.195 95.335 ;
        RECT 103.760 94.005 105.730 95.050 ;
        RECT 105.910 94.005 106.165 95.165 ;
        RECT 108.385 94.755 108.860 95.660 ;
        RECT 109.040 95.050 110.485 95.480 ;
        RECT 110.655 95.220 111.020 95.805 ;
        RECT 111.245 95.635 111.445 96.305 ;
        RECT 109.040 94.005 111.010 95.050 ;
        RECT 111.190 94.655 111.445 95.635 ;
        RECT 111.190 94.485 111.465 94.655 ;
        RECT 111.190 94.005 111.445 94.485 ;
        RECT 99.570 93.605 113.970 93.775 ;
        RECT 100.705 91.720 101.180 92.625 ;
        RECT 101.360 92.330 103.330 93.375 ;
        RECT 103.510 92.615 103.765 93.375 ;
        RECT 103.510 92.445 103.815 92.615 ;
        RECT 101.360 91.900 102.805 92.330 ;
        RECT 100.705 91.550 102.595 91.720 ;
        RECT 102.975 91.575 103.340 92.160 ;
        RECT 103.510 91.745 103.765 92.445 ;
        RECT 40.120 90.355 42.370 90.610 ;
        RECT 40.040 89.985 42.370 90.355 ;
        RECT 42.550 90.195 42.805 91.075 ;
        RECT 100.705 90.955 100.875 91.550 ;
        RECT 101.045 91.125 101.835 91.370 ;
        RECT 102.005 91.345 102.595 91.550 ;
        RECT 102.805 91.245 103.395 91.575 ;
        RECT 100.705 90.525 100.910 90.955 ;
        RECT 101.080 90.610 102.805 90.955 ;
        RECT 102.975 90.780 103.340 91.245 ;
        RECT 103.565 91.075 103.765 91.745 ;
        RECT 101.080 90.355 103.330 90.610 ;
        RECT 101.000 89.985 103.330 90.355 ;
        RECT 103.510 90.195 103.765 91.075 ;
        RECT 104.065 91.720 104.540 92.625 ;
        RECT 104.720 92.330 106.690 93.375 ;
        RECT 104.720 91.900 106.165 92.330 ;
        RECT 104.065 91.550 105.955 91.720 ;
        RECT 106.335 91.595 106.700 92.160 ;
        RECT 106.870 91.745 107.125 93.375 ;
        RECT 106.195 91.575 106.700 91.595 ;
        RECT 104.065 90.955 104.235 91.550 ;
        RECT 104.405 91.125 105.195 91.370 ;
        RECT 105.365 91.345 105.955 91.550 ;
        RECT 106.165 91.245 106.755 91.575 ;
        RECT 104.065 90.525 104.270 90.955 ;
        RECT 104.440 90.610 106.165 90.955 ;
        RECT 106.335 90.780 106.700 91.245 ;
        RECT 106.925 91.075 107.125 91.745 ;
        RECT 104.440 90.355 106.690 90.610 ;
        RECT 104.360 89.985 106.690 90.355 ;
        RECT 106.870 90.195 107.125 91.075 ;
        RECT 107.425 91.720 107.900 92.625 ;
        RECT 108.080 92.330 110.050 93.375 ;
        RECT 108.080 91.900 109.525 92.330 ;
        RECT 107.425 91.550 109.315 91.720 ;
        RECT 109.695 91.595 110.060 92.160 ;
        RECT 110.230 91.745 110.485 93.375 ;
        RECT 109.595 91.575 110.060 91.595 ;
        RECT 107.425 90.955 107.595 91.550 ;
        RECT 107.765 91.125 108.555 91.370 ;
        RECT 108.725 91.345 109.315 91.550 ;
        RECT 109.525 91.245 110.115 91.575 ;
        RECT 107.425 90.525 107.630 90.955 ;
        RECT 107.800 90.610 109.525 90.955 ;
        RECT 109.695 90.780 110.060 91.245 ;
        RECT 110.285 91.075 110.485 91.745 ;
        RECT 107.800 90.355 110.050 90.610 ;
        RECT 107.720 89.985 110.050 90.355 ;
        RECT 110.230 90.195 110.485 91.075 ;
        RECT 110.785 91.720 111.260 92.625 ;
        RECT 111.440 92.330 113.410 93.375 ;
        RECT 111.440 91.900 112.885 92.330 ;
        RECT 110.785 91.550 112.675 91.720 ;
        RECT 113.055 91.595 113.420 92.160 ;
        RECT 113.590 91.745 113.845 93.375 ;
        RECT 112.995 91.575 113.420 91.595 ;
        RECT 110.785 90.955 110.955 91.550 ;
        RECT 111.125 91.125 111.915 91.370 ;
        RECT 112.085 91.345 112.675 91.550 ;
        RECT 112.885 91.245 113.475 91.575 ;
        RECT 110.785 90.525 110.990 90.955 ;
        RECT 111.160 90.610 112.885 90.955 ;
        RECT 113.055 90.780 113.420 91.245 ;
        RECT 113.645 91.075 113.845 91.745 ;
        RECT 111.160 90.355 113.410 90.610 ;
        RECT 111.080 89.985 113.410 90.355 ;
        RECT 113.590 90.195 113.845 91.075 ;
        RECT 26.130 89.535 42.930 89.705 ;
        RECT 100.530 89.535 113.970 89.705 ;
      LAYER met1 ;
        RECT 24.690 174.790 113.970 175.390 ;
        RECT 26.130 174.465 34.290 174.790 ;
        RECT 36.210 174.465 43.410 174.790 ;
        RECT 44.850 174.465 52.050 174.790 ;
        RECT 102.450 174.465 112.530 174.790 ;
        RECT 25.460 174.200 25.780 174.260 ;
        RECT 27.255 174.200 27.545 174.245 ;
        RECT 30.685 174.200 30.915 174.275 ;
        RECT 25.460 174.060 27.545 174.200 ;
        RECT 25.460 174.000 25.780 174.060 ;
        RECT 27.255 174.015 27.545 174.060 ;
        RECT 27.850 174.060 30.915 174.200 ;
        RECT 25.000 173.520 25.320 173.580 ;
        RECT 27.850 173.520 27.990 174.060 ;
        RECT 30.685 173.985 30.915 174.060 ;
        RECT 108.855 174.200 109.145 174.245 ;
        RECT 110.560 174.200 110.880 174.260 ;
        RECT 108.855 174.060 110.880 174.200 ;
        RECT 108.855 174.015 109.145 174.060 ;
        RECT 110.560 174.000 110.880 174.060 ;
        RECT 33.885 173.860 34.175 173.905 ;
        RECT 25.000 173.380 27.990 173.520 ;
        RECT 31.070 173.720 34.175 173.860 ;
        RECT 25.000 173.320 25.320 173.380 ;
        RECT 24.540 173.180 24.860 173.240 ;
        RECT 31.070 173.180 31.210 173.720 ;
        RECT 33.885 173.675 34.175 173.720 ;
        RECT 104.945 173.520 105.235 173.565 ;
        RECT 104.945 173.335 105.270 173.520 ;
        RECT 24.540 173.040 31.210 173.180 ;
        RECT 24.540 172.980 24.860 173.040 ;
        RECT 38.800 172.980 39.120 173.240 ;
        RECT 103.660 173.180 103.980 173.240 ;
        RECT 105.130 173.180 105.270 173.335 ;
        RECT 111.575 173.180 111.865 173.225 ;
        RECT 103.660 173.040 111.865 173.180 ;
        RECT 103.660 172.980 103.980 173.040 ;
        RECT 21.780 172.840 22.100 172.900 ;
        RECT 26.235 172.840 26.525 172.885 ;
        RECT 35.580 172.840 35.900 172.900 ;
        RECT 36.435 172.840 36.725 172.885 ;
        RECT 21.780 172.700 26.525 172.840 ;
        RECT 28.770 172.775 30.750 172.840 ;
        RECT 28.680 172.760 30.750 172.775 ;
        RECT 21.780 172.640 22.100 172.700 ;
        RECT 26.235 172.655 26.525 172.700 ;
        RECT 28.615 172.715 30.750 172.760 ;
        RECT 31.505 172.715 31.795 172.760 ;
        RECT 28.615 172.700 31.795 172.715 ;
        RECT 28.615 172.530 29.000 172.700 ;
        RECT 30.610 172.575 31.795 172.700 ;
        RECT 35.580 172.700 36.725 172.840 ;
        RECT 35.580 172.640 35.900 172.700 ;
        RECT 36.435 172.655 36.725 172.700 ;
        RECT 41.100 172.840 41.420 172.900 ;
        RECT 108.350 172.885 108.490 173.040 ;
        RECT 111.575 172.995 111.865 173.040 ;
        RECT 45.275 172.840 45.565 172.885 ;
        RECT 41.100 172.700 45.565 172.840 ;
        RECT 106.510 172.760 108.030 172.840 ;
        RECT 41.100 172.640 41.420 172.700 ;
        RECT 45.275 172.655 45.565 172.700 ;
        RECT 103.245 172.715 103.535 172.760 ;
        RECT 106.305 172.715 108.030 172.760 ;
        RECT 28.680 172.515 29.000 172.530 ;
        RECT 29.975 172.500 30.265 172.545 ;
        RECT 31.505 172.530 31.795 172.575 ;
        RECT 103.245 172.575 103.890 172.715 ;
        RECT 33.375 172.500 33.665 172.545 ;
        RECT 103.245 172.530 103.535 172.575 ;
        RECT 29.690 172.360 30.265 172.500 ;
        RECT 28.220 172.160 28.540 172.220 ;
        RECT 29.690 172.160 29.830 172.360 ;
        RECT 29.975 172.315 30.265 172.360 ;
        RECT 32.450 172.360 33.665 172.500 ;
        RECT 32.450 172.160 32.590 172.360 ;
        RECT 33.375 172.315 33.665 172.360 ;
        RECT 50.760 172.205 51.080 172.220 ;
        RECT 28.220 172.020 32.590 172.160 ;
        RECT 28.220 171.960 28.540 172.020 ;
        RECT 50.715 171.975 51.080 172.205 ;
        RECT 50.760 171.960 51.080 171.975 ;
        RECT 103.200 172.160 103.520 172.220 ;
        RECT 103.750 172.160 103.890 172.575 ;
        RECT 105.735 172.700 108.030 172.715 ;
        RECT 105.735 172.575 106.650 172.700 ;
        RECT 105.735 172.500 105.875 172.575 ;
        RECT 106.305 172.530 106.595 172.575 ;
        RECT 105.130 172.360 105.875 172.500 ;
        RECT 107.890 172.500 108.030 172.700 ;
        RECT 108.175 172.700 108.490 172.885 ;
        RECT 112.285 172.840 112.515 172.915 ;
        RECT 115.620 172.840 115.940 172.900 ;
        RECT 109.705 172.715 109.995 172.760 ;
        RECT 108.175 172.655 108.465 172.700 ;
        RECT 108.810 172.575 109.995 172.715 ;
        RECT 112.285 172.700 115.940 172.840 ;
        RECT 112.285 172.625 112.515 172.700 ;
        RECT 115.620 172.640 115.940 172.700 ;
        RECT 108.810 172.500 108.950 172.575 ;
        RECT 109.705 172.530 109.995 172.575 ;
        RECT 107.890 172.360 108.950 172.500 ;
        RECT 105.130 172.160 105.270 172.360 ;
        RECT 105.500 172.205 105.820 172.220 ;
        RECT 103.200 172.020 105.270 172.160 ;
        RECT 103.200 171.960 103.520 172.020 ;
        RECT 105.455 171.975 105.820 172.205 ;
        RECT 105.500 171.960 105.820 171.975 ;
        RECT 26.130 171.320 34.290 171.645 ;
        RECT 36.210 171.320 43.410 171.645 ;
        RECT 44.850 171.320 52.050 171.645 ;
        RECT 102.450 171.320 112.530 171.645 ;
        RECT 24.690 170.720 113.970 171.320 ;
        RECT 27.090 170.395 58.770 170.720 ;
        RECT 101.490 170.395 111.570 170.720 ;
        RECT 25.920 170.120 26.240 170.180 ;
        RECT 36.775 170.120 37.065 170.165 ;
        RECT 25.920 169.980 37.065 170.120 ;
        RECT 25.920 169.920 26.240 169.980 ;
        RECT 36.775 169.935 37.065 169.980 ;
        RECT 104.435 170.120 104.725 170.165 ;
        RECT 105.500 170.120 105.820 170.180 ;
        RECT 104.435 169.980 105.820 170.120 ;
        RECT 104.435 169.935 104.725 169.980 ;
        RECT 105.500 169.920 105.820 169.980 ;
        RECT 25.460 169.780 25.780 169.840 ;
        RECT 38.800 169.780 39.120 169.840 ;
        RECT 40.640 169.780 40.960 169.840 ;
        RECT 50.760 169.825 51.080 169.840 ;
        RECT 25.460 169.640 36.730 169.780 ;
        RECT 25.460 169.580 25.780 169.640 ;
        RECT 26.575 169.440 26.865 169.485 ;
        RECT 27.595 169.440 27.885 169.485 ;
        RECT 28.680 169.440 29.000 169.500 ;
        RECT 30.995 169.440 31.285 169.485 ;
        RECT 34.395 169.440 34.685 169.485 ;
        RECT 36.095 169.440 36.385 169.485 ;
        RECT 26.575 169.300 34.685 169.440 ;
        RECT 26.575 169.255 26.865 169.300 ;
        RECT 27.595 169.255 27.885 169.300 ;
        RECT 28.680 169.240 29.000 169.300 ;
        RECT 30.995 169.255 31.285 169.300 ;
        RECT 34.395 169.255 34.685 169.300 ;
        RECT 35.210 169.300 36.385 169.440 ;
        RECT 36.590 169.440 36.730 169.640 ;
        RECT 38.800 169.640 40.960 169.780 ;
        RECT 38.800 169.580 39.120 169.640 ;
        RECT 40.640 169.580 40.960 169.640 ;
        RECT 50.715 169.595 51.080 169.825 ;
        RECT 50.760 169.580 51.080 169.595 ;
        RECT 103.200 169.780 103.520 169.840 ;
        RECT 103.200 169.640 105.270 169.780 ;
        RECT 103.200 169.580 103.520 169.640 ;
        RECT 37.455 169.440 37.745 169.485 ;
        RECT 44.595 169.440 44.885 169.485 ;
        RECT 48.460 169.440 48.780 169.500 ;
        RECT 36.590 169.300 48.780 169.440 ;
        RECT 50.850 169.440 50.990 169.580 ;
        RECT 51.735 169.440 52.025 169.485 ;
        RECT 50.850 169.300 52.025 169.440 ;
        RECT 33.035 169.100 33.325 169.145 ;
        RECT 35.210 169.100 35.350 169.300 ;
        RECT 36.095 169.255 36.385 169.300 ;
        RECT 37.455 169.255 37.745 169.300 ;
        RECT 44.595 169.255 44.885 169.300 ;
        RECT 48.460 169.240 48.780 169.300 ;
        RECT 51.735 169.255 52.025 169.300 ;
        RECT 100.900 169.440 101.220 169.500 ;
        RECT 102.055 169.440 102.345 169.485 ;
        RECT 103.290 169.440 103.430 169.580 ;
        RECT 100.900 169.300 103.430 169.440 ;
        RECT 103.660 169.485 103.980 169.500 ;
        RECT 103.660 169.440 104.045 169.485 ;
        RECT 105.130 169.440 105.270 169.640 ;
        RECT 105.455 169.440 105.745 169.485 ;
        RECT 108.855 169.440 109.145 169.485 ;
        RECT 103.660 169.300 104.810 169.440 ;
        RECT 105.130 169.300 109.145 169.440 ;
        RECT 100.900 169.240 101.220 169.300 ;
        RECT 102.055 169.255 102.345 169.300 ;
        RECT 103.660 169.255 104.045 169.300 ;
        RECT 103.660 169.240 103.980 169.255 ;
        RECT 32.910 168.960 35.350 169.100 ;
        RECT 104.670 169.100 104.810 169.300 ;
        RECT 105.455 169.255 105.745 169.300 ;
        RECT 108.855 169.255 109.145 169.300 ;
        RECT 107.155 169.100 107.445 169.145 ;
        RECT 110.555 169.100 110.845 169.145 ;
        RECT 104.670 168.960 110.845 169.100 ;
        RECT 32.910 168.915 33.325 168.960 ;
        RECT 107.155 168.915 107.445 168.960 ;
        RECT 110.555 168.915 110.845 168.960 ;
        RECT 28.220 168.760 28.540 168.820 ;
        RECT 29.635 168.760 29.925 168.805 ;
        RECT 32.910 168.760 33.050 168.915 ;
        RECT 28.220 168.620 33.050 168.760 ;
        RECT 107.835 168.760 108.125 168.805 ;
        RECT 113.320 168.760 113.640 168.820 ;
        RECT 107.835 168.620 113.640 168.760 ;
        RECT 28.220 168.560 28.540 168.620 ;
        RECT 29.635 168.575 29.925 168.620 ;
        RECT 107.835 168.575 108.125 168.620 ;
        RECT 113.320 168.560 113.640 168.620 ;
        RECT 25.920 168.420 26.240 168.480 ;
        RECT 33.375 168.420 33.665 168.465 ;
        RECT 25.920 168.280 33.665 168.420 ;
        RECT 25.920 168.220 26.240 168.280 ;
        RECT 33.375 168.235 33.665 168.280 ;
        RECT 23.160 168.080 23.480 168.140 ;
        RECT 30.145 168.080 30.435 168.125 ;
        RECT 23.160 167.940 30.435 168.080 ;
        RECT 23.160 167.880 23.480 167.940 ;
        RECT 30.145 167.895 30.435 167.940 ;
        RECT 52.755 168.080 53.045 168.125 ;
        RECT 53.520 168.080 53.840 168.140 ;
        RECT 52.755 167.940 53.840 168.080 ;
        RECT 52.755 167.895 53.045 167.940 ;
        RECT 53.520 167.880 53.840 167.940 ;
        RECT 111.235 168.080 111.525 168.125 ;
        RECT 115.160 168.080 115.480 168.140 ;
        RECT 111.235 167.940 115.480 168.080 ;
        RECT 111.235 167.895 111.525 167.940 ;
        RECT 115.160 167.880 115.480 167.940 ;
        RECT 27.090 167.250 58.770 167.575 ;
        RECT 101.490 167.250 111.570 167.575 ;
        RECT 24.690 166.650 113.970 167.250 ;
        RECT 27.090 166.325 33.810 166.650 ;
        RECT 34.290 166.325 41.010 166.650 ;
        RECT 47.730 166.325 52.050 166.650 ;
        RECT 53.010 166.325 54.450 166.650 ;
        RECT 55.410 166.325 69.810 166.650 ;
        RECT 98.130 166.325 111.570 166.650 ;
        RECT 38.800 166.040 39.120 166.100 ;
        RECT 48.460 166.085 48.780 166.100 ;
        RECT 40.685 166.040 40.975 166.085 ;
        RECT 38.800 165.900 40.975 166.040 ;
        RECT 38.800 165.840 39.120 165.900 ;
        RECT 40.685 165.855 40.975 165.900 ;
        RECT 48.460 165.855 48.965 166.085 ;
        RECT 101.235 166.040 101.465 166.115 ;
        RECT 103.200 166.040 103.520 166.100 ;
        RECT 101.235 165.900 103.520 166.040 ;
        RECT 48.460 165.840 48.780 165.855 ;
        RECT 101.235 165.825 101.465 165.900 ;
        RECT 103.200 165.840 103.520 165.900 ;
        RECT 25.920 165.360 26.240 165.420 ;
        RECT 33.375 165.360 33.665 165.405 ;
        RECT 36.775 165.360 37.065 165.405 ;
        RECT 40.175 165.360 40.465 165.405 ;
        RECT 50.035 165.360 50.325 165.405 ;
        RECT 51.735 165.360 52.025 165.405 ;
        RECT 25.920 165.220 33.665 165.360 ;
        RECT 25.920 165.160 26.240 165.220 ;
        RECT 33.375 165.175 33.665 165.220 ;
        RECT 33.830 165.220 40.465 165.360 ;
        RECT 28.220 165.020 28.540 165.080 ;
        RECT 29.635 165.020 29.925 165.065 ;
        RECT 33.830 165.020 33.970 165.220 ;
        RECT 36.775 165.175 37.065 165.220 ;
        RECT 40.175 165.175 40.465 165.220 ;
        RECT 49.930 165.220 52.025 165.360 ;
        RECT 49.930 165.175 50.325 165.220 ;
        RECT 51.735 165.175 52.025 165.220 ;
        RECT 28.220 164.880 33.970 165.020 ;
        RECT 28.220 164.820 28.540 164.880 ;
        RECT 29.635 164.835 29.925 164.880 ;
        RECT 33.110 164.725 33.250 164.880 ;
        RECT 26.575 164.575 26.865 164.620 ;
        RECT 27.595 164.575 27.885 164.620 ;
        RECT 30.995 164.575 31.285 164.620 ;
        RECT 26.575 164.435 32.590 164.575 ;
        RECT 33.035 164.495 33.325 164.725 ;
        RECT 35.580 164.680 35.900 164.740 ;
        RECT 49.930 164.725 50.070 165.175 ;
        RECT 54.115 165.020 54.405 165.065 ;
        RECT 100.900 165.020 101.220 165.080 ;
        RECT 107.835 165.020 108.125 165.065 ;
        RECT 113.320 165.020 113.640 165.080 ;
        RECT 52.230 164.880 54.405 165.020 ;
        RECT 51.220 164.725 51.540 164.740 ;
        RECT 37.285 164.680 37.575 164.725 ;
        RECT 34.750 164.620 35.350 164.680 ;
        RECT 34.750 164.540 35.365 164.620 ;
        RECT 26.575 164.390 26.865 164.435 ;
        RECT 27.595 164.390 27.885 164.435 ;
        RECT 30.995 164.390 31.285 164.435 ;
        RECT 25.000 164.000 25.320 164.060 ;
        RECT 30.145 164.000 30.435 164.045 ;
        RECT 25.000 163.860 30.435 164.000 ;
        RECT 32.450 164.000 32.590 164.435 ;
        RECT 34.750 164.000 34.890 164.540 ;
        RECT 35.075 164.390 35.365 164.540 ;
        RECT 35.580 164.540 37.575 164.680 ;
        RECT 48.335 164.680 48.625 164.725 ;
        RECT 49.695 164.680 50.070 164.725 ;
        RECT 38.305 164.575 38.595 164.620 ;
        RECT 35.580 164.480 35.900 164.540 ;
        RECT 37.285 164.495 37.575 164.540 ;
        RECT 37.970 164.435 38.595 164.575 ;
        RECT 48.335 164.540 50.070 164.680 ;
        RECT 51.055 164.680 51.540 164.725 ;
        RECT 52.230 164.680 52.370 164.880 ;
        RECT 54.115 164.835 54.405 164.880 ;
        RECT 100.070 164.880 101.220 165.020 ;
        RECT 53.520 164.725 53.840 164.740 ;
        RECT 55.820 164.725 56.140 164.740 ;
        RECT 63.180 164.725 63.500 164.740 ;
        RECT 51.055 164.540 52.370 164.680 ;
        RECT 53.435 164.680 53.840 164.725 ;
        RECT 55.815 164.680 56.140 164.725 ;
        RECT 62.955 164.680 63.500 164.725 ;
        RECT 53.435 164.540 56.140 164.680 ;
        RECT 48.335 164.495 48.625 164.540 ;
        RECT 49.695 164.495 49.985 164.540 ;
        RECT 51.055 164.495 51.540 164.540 ;
        RECT 53.435 164.495 53.840 164.540 ;
        RECT 55.815 164.495 56.140 164.540 ;
        RECT 51.220 164.480 51.540 164.495 ;
        RECT 53.520 164.480 53.840 164.495 ;
        RECT 55.820 164.480 56.140 164.495 ;
        RECT 62.350 164.540 63.500 164.680 ;
        RECT 100.070 164.680 100.210 164.880 ;
        RECT 100.900 164.820 101.220 164.880 ;
        RECT 103.830 164.880 107.370 165.020 ;
        RECT 103.830 164.740 103.970 164.880 ;
        RECT 103.660 164.725 103.980 164.740 ;
        RECT 107.230 164.725 107.370 164.880 ;
        RECT 107.835 164.880 113.640 165.020 ;
        RECT 107.835 164.835 108.125 164.880 ;
        RECT 113.320 164.820 113.640 164.880 ;
        RECT 110.560 164.725 110.880 164.740 ;
        RECT 100.070 164.620 102.510 164.680 ;
        RECT 37.970 164.000 38.110 164.435 ;
        RECT 38.305 164.390 38.595 164.435 ;
        RECT 62.350 164.385 62.490 164.540 ;
        RECT 62.955 164.495 63.500 164.540 ;
        RECT 63.180 164.480 63.500 164.495 ;
        RECT 99.165 164.575 99.455 164.620 ;
        RECT 100.070 164.575 102.515 164.620 ;
        RECT 99.165 164.540 103.430 164.575 ;
        RECT 99.165 164.435 100.210 164.540 ;
        RECT 102.225 164.435 103.430 164.540 ;
        RECT 103.660 164.495 104.045 164.725 ;
        RECT 105.795 164.575 106.085 164.620 ;
        RECT 103.660 164.480 103.980 164.495 ;
        RECT 99.165 164.390 99.455 164.435 ;
        RECT 102.225 164.390 102.515 164.435 ;
        RECT 62.275 164.155 62.565 164.385 ;
        RECT 100.695 164.340 100.985 164.385 ;
        RECT 103.290 164.340 103.430 164.435 ;
        RECT 105.130 164.435 106.295 164.575 ;
        RECT 107.155 164.495 107.445 164.725 ;
        RECT 110.555 164.680 110.880 164.725 ;
        RECT 108.685 164.575 108.975 164.620 ;
        RECT 108.350 164.435 108.975 164.575 ;
        RECT 110.365 164.540 110.880 164.680 ;
        RECT 110.555 164.495 110.880 164.540 ;
        RECT 110.560 164.480 110.880 164.495 ;
        RECT 105.130 164.340 105.270 164.435 ;
        RECT 105.795 164.390 106.190 164.435 ;
        RECT 100.695 164.200 102.050 164.340 ;
        RECT 103.290 164.200 105.270 164.340 ;
        RECT 100.695 164.155 100.985 164.200 ;
        RECT 32.450 163.860 38.110 164.000 ;
        RECT 101.910 164.000 102.050 164.200 ;
        RECT 106.050 164.060 106.190 164.390 ;
        RECT 103.660 164.000 103.980 164.060 ;
        RECT 101.910 163.860 103.980 164.000 ;
        RECT 25.000 163.800 25.320 163.860 ;
        RECT 30.145 163.815 30.435 163.860 ;
        RECT 103.660 163.800 103.980 163.860 ;
        RECT 104.435 164.000 104.725 164.045 ;
        RECT 105.500 164.000 105.820 164.060 ;
        RECT 104.435 163.860 105.820 164.000 ;
        RECT 104.435 163.815 104.725 163.860 ;
        RECT 105.500 163.800 105.820 163.860 ;
        RECT 105.960 164.000 106.280 164.060 ;
        RECT 108.350 164.000 108.490 164.435 ;
        RECT 108.685 164.390 108.975 164.435 ;
        RECT 105.960 163.860 108.490 164.000 ;
        RECT 111.235 164.000 111.525 164.045 ;
        RECT 115.160 164.000 115.480 164.060 ;
        RECT 111.235 163.860 115.480 164.000 ;
        RECT 105.960 163.800 106.280 163.860 ;
        RECT 111.235 163.815 111.525 163.860 ;
        RECT 115.160 163.800 115.480 163.860 ;
        RECT 27.090 163.180 33.810 163.505 ;
        RECT 34.290 163.180 41.010 163.505 ;
        RECT 47.730 163.180 52.050 163.505 ;
        RECT 53.010 163.180 54.450 163.505 ;
        RECT 55.410 163.180 69.810 163.505 ;
        RECT 98.130 163.180 111.570 163.505 ;
        RECT 24.690 162.580 113.970 163.180 ;
        RECT 27.090 162.255 37.170 162.580 ;
        RECT 39.570 162.255 46.770 162.580 ;
        RECT 50.130 162.255 51.570 162.580 ;
        RECT 54.930 162.255 62.130 162.580 ;
        RECT 103.890 162.255 113.970 162.580 ;
        RECT 51.220 162.005 51.540 162.020 ;
        RECT 27.670 161.820 30.750 161.960 ;
        RECT 27.670 161.325 27.810 161.820 ;
        RECT 28.220 161.620 28.540 161.680 ;
        RECT 29.635 161.620 29.925 161.665 ;
        RECT 28.220 161.480 29.925 161.620 ;
        RECT 30.610 161.620 30.750 161.820 ;
        RECT 51.055 161.775 51.540 162.005 ;
        RECT 51.220 161.760 51.540 161.775 ;
        RECT 30.610 161.480 34.610 161.620 ;
        RECT 28.220 161.420 28.540 161.480 ;
        RECT 29.635 161.435 29.925 161.480 ;
        RECT 26.575 161.280 26.865 161.325 ;
        RECT 27.595 161.280 27.885 161.325 ;
        RECT 26.575 161.140 27.885 161.280 ;
        RECT 29.710 161.280 29.850 161.435 ;
        RECT 31.070 161.325 31.210 161.480 ;
        RECT 34.470 161.325 34.610 161.480 ;
        RECT 106.050 161.480 111.450 161.620 ;
        RECT 106.050 161.340 106.190 161.480 ;
        RECT 40.640 161.325 40.960 161.340 ;
        RECT 29.710 161.140 30.750 161.280 ;
        RECT 26.575 161.095 26.865 161.140 ;
        RECT 27.595 161.095 27.885 161.140 ;
        RECT 30.610 160.940 30.750 161.140 ;
        RECT 30.995 161.095 31.285 161.325 ;
        RECT 33.035 161.095 33.325 161.325 ;
        RECT 34.395 161.095 34.685 161.325 ;
        RECT 36.095 161.095 36.385 161.325 ;
        RECT 40.515 161.095 40.960 161.325 ;
        RECT 33.110 160.940 33.250 161.095 ;
        RECT 36.170 160.940 36.310 161.095 ;
        RECT 40.640 161.080 40.960 161.095 ;
        RECT 45.700 161.280 46.020 161.340 ;
        RECT 55.820 161.325 56.140 161.340 ;
        RECT 50.375 161.280 50.665 161.325 ;
        RECT 55.815 161.280 56.140 161.325 ;
        RECT 45.700 161.140 50.665 161.280 ;
        RECT 55.625 161.140 56.140 161.280 ;
        RECT 45.700 161.080 46.020 161.140 ;
        RECT 50.375 161.095 50.665 161.140 ;
        RECT 55.815 161.095 56.140 161.140 ;
        RECT 104.775 161.280 105.065 161.325 ;
        RECT 105.960 161.280 106.280 161.340 ;
        RECT 107.910 161.325 108.050 161.480 ;
        RECT 104.775 161.140 106.280 161.280 ;
        RECT 104.775 161.095 105.065 161.140 ;
        RECT 55.820 161.080 56.140 161.095 ;
        RECT 105.960 161.080 106.280 161.140 ;
        RECT 106.475 161.095 106.765 161.325 ;
        RECT 107.835 161.095 108.125 161.325 ;
        RECT 109.535 161.280 109.825 161.325 ;
        RECT 110.560 161.280 110.880 161.340 ;
        RECT 111.310 161.325 111.450 161.480 ;
        RECT 108.810 161.140 110.880 161.280 ;
        RECT 29.230 160.800 30.290 160.940 ;
        RECT 30.610 160.800 36.310 160.940 ;
        RECT 25.460 160.600 25.780 160.660 ;
        RECT 29.230 160.600 29.370 160.800 ;
        RECT 25.460 160.460 29.370 160.600 ;
        RECT 30.150 160.600 30.290 160.800 ;
        RECT 36.775 160.600 37.065 160.645 ;
        RECT 30.150 160.460 37.065 160.600 ;
        RECT 55.910 160.600 56.050 161.080 ;
        RECT 103.660 160.940 103.980 161.000 ;
        RECT 106.510 160.940 106.650 161.095 ;
        RECT 108.810 160.940 108.950 161.140 ;
        RECT 109.535 161.095 109.825 161.140 ;
        RECT 110.560 161.080 110.880 161.140 ;
        RECT 111.235 161.095 111.525 161.325 ;
        RECT 103.660 160.800 108.950 160.940 ;
        RECT 110.650 160.940 110.790 161.080 ;
        RECT 112.935 160.940 113.225 160.985 ;
        RECT 110.650 160.800 113.225 160.940 ;
        RECT 103.660 160.740 103.980 160.800 ;
        RECT 112.935 160.755 113.225 160.800 ;
        RECT 57.855 160.600 58.145 160.645 ;
        RECT 55.910 160.460 58.145 160.600 ;
        RECT 25.460 160.400 25.780 160.460 ;
        RECT 36.775 160.415 37.065 160.460 ;
        RECT 57.855 160.415 58.145 160.460 ;
        RECT 106.815 160.600 107.105 160.645 ;
        RECT 107.800 160.600 108.120 160.660 ;
        RECT 106.815 160.460 108.120 160.600 ;
        RECT 106.815 160.415 107.105 160.460 ;
        RECT 107.800 160.400 108.120 160.460 ;
        RECT 25.920 160.260 26.240 160.320 ;
        RECT 33.375 160.260 33.665 160.305 ;
        RECT 25.920 160.120 33.665 160.260 ;
        RECT 25.920 160.060 26.240 160.120 ;
        RECT 33.375 160.075 33.665 160.120 ;
        RECT 25.000 159.920 25.320 159.980 ;
        RECT 45.700 159.965 46.020 159.980 ;
        RECT 30.145 159.920 30.435 159.965 ;
        RECT 25.000 159.780 30.435 159.920 ;
        RECT 25.000 159.720 25.320 159.780 ;
        RECT 30.145 159.735 30.435 159.780 ;
        RECT 45.615 159.735 46.020 159.965 ;
        RECT 110.215 159.920 110.505 159.965 ;
        RECT 112.860 159.920 113.180 159.980 ;
        RECT 110.215 159.780 113.180 159.920 ;
        RECT 110.215 159.735 110.505 159.780 ;
        RECT 45.700 159.720 46.020 159.735 ;
        RECT 112.860 159.720 113.180 159.780 ;
        RECT 113.615 159.920 113.905 159.965 ;
        RECT 116.540 159.920 116.860 159.980 ;
        RECT 113.615 159.780 116.860 159.920 ;
        RECT 113.615 159.735 113.905 159.780 ;
        RECT 116.540 159.720 116.860 159.780 ;
        RECT 27.090 159.110 37.170 159.435 ;
        RECT 39.570 159.110 46.770 159.435 ;
        RECT 50.130 159.110 51.570 159.435 ;
        RECT 54.930 159.110 62.130 159.435 ;
        RECT 103.890 159.110 113.970 159.435 ;
        RECT 24.690 158.510 113.970 159.110 ;
        RECT 27.090 158.185 33.810 158.510 ;
        RECT 35.730 158.185 39.090 158.510 ;
        RECT 40.050 158.185 54.450 158.510 ;
        RECT 61.170 158.185 68.370 158.510 ;
        RECT 102.930 158.185 113.010 158.510 ;
        RECT 63.180 157.880 63.500 157.940 ;
        RECT 63.975 157.880 64.265 157.925 ;
        RECT 63.180 157.740 64.265 157.880 ;
        RECT 63.180 157.680 63.500 157.740 ;
        RECT 63.975 157.695 64.265 157.740 ;
        RECT 25.920 157.200 26.240 157.260 ;
        RECT 33.375 157.200 33.665 157.245 ;
        RECT 25.920 157.060 33.665 157.200 ;
        RECT 25.920 157.000 26.240 157.060 ;
        RECT 33.375 157.015 33.665 157.060 ;
        RECT 28.220 156.860 28.540 156.920 ;
        RECT 29.635 156.860 29.925 156.905 ;
        RECT 38.135 156.860 38.425 156.905 ;
        RECT 28.220 156.720 38.425 156.860 ;
        RECT 28.220 156.660 28.540 156.720 ;
        RECT 29.635 156.675 29.925 156.720 ;
        RECT 33.110 156.565 33.250 156.720 ;
        RECT 38.135 156.675 38.425 156.720 ;
        RECT 105.965 156.860 106.255 156.905 ;
        RECT 112.860 156.860 113.180 156.920 ;
        RECT 105.965 156.720 113.180 156.860 ;
        RECT 105.965 156.675 106.255 156.720 ;
        RECT 112.860 156.660 113.180 156.720 ;
        RECT 38.845 156.580 39.075 156.595 ;
        RECT 26.575 156.435 26.865 156.480 ;
        RECT 28.105 156.435 28.395 156.480 ;
        RECT 28.680 156.435 29.000 156.495 ;
        RECT 30.995 156.435 31.285 156.480 ;
        RECT 26.575 156.295 32.590 156.435 ;
        RECT 33.035 156.335 33.325 156.565 ;
        RECT 36.265 156.435 36.555 156.480 ;
        RECT 26.575 156.250 26.865 156.295 ;
        RECT 28.105 156.250 28.395 156.295 ;
        RECT 28.680 156.235 29.000 156.295 ;
        RECT 30.995 156.250 31.285 156.295 ;
        RECT 32.450 156.180 32.590 156.295 ;
        RECT 34.980 156.295 36.555 156.435 ;
        RECT 38.800 156.320 39.120 156.580 ;
        RECT 45.700 156.520 46.020 156.580 ;
        RECT 46.295 156.520 46.585 156.565 ;
        RECT 47.005 156.520 47.235 156.595 ;
        RECT 63.180 156.565 63.500 156.580 ;
        RECT 47.655 156.520 47.945 156.565 ;
        RECT 45.700 156.380 47.945 156.520 ;
        RECT 45.700 156.320 46.020 156.380 ;
        RECT 46.295 156.335 46.585 156.380 ;
        RECT 38.845 156.305 39.075 156.320 ;
        RECT 47.005 156.305 47.235 156.380 ;
        RECT 47.655 156.335 47.945 156.380 ;
        RECT 63.180 156.335 63.585 156.565 ;
        RECT 111.020 156.520 111.340 156.580 ;
        RECT 111.915 156.520 112.205 156.565 ;
        RECT 104.670 156.480 107.370 156.520 ;
        RECT 108.350 156.495 109.410 156.520 ;
        RECT 103.925 156.435 104.215 156.480 ;
        RECT 104.670 156.435 107.615 156.480 ;
        RECT 108.260 156.435 109.410 156.495 ;
        RECT 110.215 156.435 110.505 156.480 ;
        RECT 103.925 156.380 110.505 156.435 ;
        RECT 63.180 156.320 63.500 156.335 ;
        RECT 34.980 156.180 35.120 156.295 ;
        RECT 36.265 156.250 36.555 156.295 ;
        RECT 103.925 156.295 104.810 156.380 ;
        RECT 103.925 156.250 104.215 156.295 ;
        RECT 105.960 156.235 106.280 156.380 ;
        RECT 107.230 156.295 108.580 156.380 ;
        RECT 109.270 156.295 110.505 156.380 ;
        RECT 111.020 156.380 112.205 156.520 ;
        RECT 111.020 156.320 111.340 156.380 ;
        RECT 111.915 156.335 112.205 156.380 ;
        RECT 107.325 156.250 107.615 156.295 ;
        RECT 108.260 156.235 108.580 156.295 ;
        RECT 110.215 156.250 110.505 156.295 ;
        RECT 32.450 156.040 35.120 156.180 ;
        RECT 105.455 155.995 105.745 156.225 ;
        RECT 108.855 155.995 109.145 156.225 ;
        RECT 21.780 155.840 22.100 155.900 ;
        RECT 53.520 155.885 53.840 155.900 ;
        RECT 30.145 155.840 30.435 155.885 ;
        RECT 21.780 155.700 30.435 155.840 ;
        RECT 21.780 155.640 22.100 155.700 ;
        RECT 30.145 155.655 30.435 155.700 ;
        RECT 53.435 155.655 53.840 155.885 ;
        RECT 105.530 155.840 105.670 155.995 ;
        RECT 105.960 155.840 106.280 155.900 ;
        RECT 108.930 155.840 109.070 155.995 ;
        RECT 105.530 155.700 109.070 155.840 ;
        RECT 109.395 155.840 109.625 155.915 ;
        RECT 111.020 155.840 111.340 155.900 ;
        RECT 109.395 155.700 111.340 155.840 ;
        RECT 53.520 155.640 53.840 155.655 ;
        RECT 105.960 155.640 106.280 155.700 ;
        RECT 109.395 155.625 109.625 155.700 ;
        RECT 111.020 155.640 111.340 155.700 ;
        RECT 112.595 155.840 112.885 155.885 ;
        RECT 116.080 155.840 116.400 155.900 ;
        RECT 112.595 155.700 116.400 155.840 ;
        RECT 112.595 155.655 112.885 155.700 ;
        RECT 116.080 155.640 116.400 155.700 ;
        RECT 27.090 155.040 33.810 155.365 ;
        RECT 35.730 155.040 39.090 155.365 ;
        RECT 40.050 155.040 54.450 155.365 ;
        RECT 61.170 155.040 68.370 155.365 ;
        RECT 102.930 155.040 113.010 155.365 ;
        RECT 24.690 154.440 113.970 155.040 ;
        RECT 27.090 154.115 30.450 154.440 ;
        RECT 31.410 154.115 38.130 154.440 ;
        RECT 49.170 154.115 56.370 154.440 ;
        RECT 59.250 154.115 66.450 154.440 ;
        RECT 104.850 154.115 111.570 154.440 ;
        RECT 28.220 153.800 28.540 153.860 ;
        RECT 60.880 153.800 61.200 153.860 ;
        RECT 63.180 153.800 63.500 153.860 ;
        RECT 65.335 153.800 65.625 153.845 ;
        RECT 28.220 153.660 29.850 153.800 ;
        RECT 28.220 153.600 28.540 153.660 ;
        RECT 29.710 153.505 29.850 153.660 ;
        RECT 53.435 153.580 53.735 153.630 ;
        RECT 55.160 153.580 55.460 153.630 ;
        RECT 57.810 153.580 58.285 153.680 ;
        RECT 60.880 153.660 65.625 153.800 ;
        RECT 60.880 153.600 61.200 153.660 ;
        RECT 63.180 153.600 63.500 153.660 ;
        RECT 65.335 153.615 65.625 153.660 ;
        RECT 29.635 153.460 29.925 153.505 ;
        RECT 30.995 153.460 31.285 153.505 ;
        RECT 29.635 153.320 31.285 153.460 ;
        RECT 53.435 153.430 58.285 153.580 ;
        RECT 53.435 153.380 53.735 153.430 ;
        RECT 55.160 153.380 55.460 153.430 ;
        RECT 57.810 153.330 58.285 153.430 ;
        RECT 29.635 153.275 29.925 153.320 ;
        RECT 30.995 153.275 31.285 153.320 ;
        RECT 28.105 153.180 28.395 153.225 ;
        RECT 28.680 153.180 29.000 153.240 ;
        RECT 108.720 153.225 109.040 153.240 ;
        RECT 32.015 153.180 32.305 153.225 ;
        RECT 35.245 153.180 35.535 153.225 ;
        RECT 105.795 153.180 106.085 153.225 ;
        RECT 108.685 153.180 109.040 153.225 ;
        RECT 28.105 153.120 29.000 153.180 ;
        RECT 31.530 153.120 35.535 153.180 ;
        RECT 28.105 153.040 35.535 153.120 ;
        RECT 28.105 152.995 28.395 153.040 ;
        RECT 28.680 152.980 31.670 153.040 ;
        RECT 32.015 152.995 32.305 153.040 ;
        RECT 35.245 152.995 35.535 153.040 ;
        RECT 53.520 153.120 53.840 153.180 ;
        RECT 55.475 153.120 55.765 153.165 ;
        RECT 57.175 153.120 57.465 153.165 ;
        RECT 53.520 152.980 57.465 153.120 ;
        RECT 53.520 152.920 53.840 152.980 ;
        RECT 55.475 152.935 55.765 152.980 ;
        RECT 57.175 152.935 57.465 152.980 ;
        RECT 65.675 153.120 65.965 153.165 ;
        RECT 66.695 153.120 66.985 153.165 ;
        RECT 65.675 152.980 66.985 153.120 ;
        RECT 105.795 153.040 109.040 153.180 ;
        RECT 105.795 152.995 106.085 153.040 ;
        RECT 108.685 152.995 109.040 153.040 ;
        RECT 108.720 152.980 109.040 152.995 ;
        RECT 65.675 152.935 65.965 152.980 ;
        RECT 66.695 152.935 66.985 152.980 ;
        RECT 25.920 152.780 26.240 152.840 ;
        RECT 30.980 152.780 31.300 152.840 ;
        RECT 33.715 152.780 34.005 152.825 ;
        RECT 37.115 152.780 37.405 152.825 ;
        RECT 25.920 152.640 30.290 152.780 ;
        RECT 25.920 152.580 26.240 152.640 ;
        RECT 30.150 152.440 30.290 152.640 ;
        RECT 30.980 152.640 37.405 152.780 ;
        RECT 30.980 152.580 31.300 152.640 ;
        RECT 33.715 152.595 34.005 152.640 ;
        RECT 37.115 152.595 37.405 152.640 ;
        RECT 105.960 152.780 106.280 152.840 ;
        RECT 110.560 152.825 110.880 152.840 ;
        RECT 107.155 152.780 107.445 152.825 ;
        RECT 110.555 152.780 110.880 152.825 ;
        RECT 105.960 152.640 110.880 152.780 ;
        RECT 105.960 152.580 106.280 152.640 ;
        RECT 107.155 152.595 107.445 152.640 ;
        RECT 110.555 152.595 110.880 152.640 ;
        RECT 110.560 152.580 110.880 152.595 ;
        RECT 37.795 152.440 38.085 152.485 ;
        RECT 30.150 152.300 38.085 152.440 ;
        RECT 37.795 152.255 38.085 152.300 ;
        RECT 107.835 152.440 108.125 152.485 ;
        RECT 113.320 152.440 113.640 152.500 ;
        RECT 107.835 152.300 113.640 152.440 ;
        RECT 107.835 152.255 108.125 152.300 ;
        RECT 113.320 152.240 113.640 152.300 ;
        RECT 33.740 152.100 34.060 152.160 ;
        RECT 34.395 152.100 34.685 152.145 ;
        RECT 33.740 151.960 34.685 152.100 ;
        RECT 33.740 151.900 34.060 151.960 ;
        RECT 34.395 151.915 34.685 151.960 ;
        RECT 24.080 151.760 24.400 151.820 ;
        RECT 30.145 151.760 30.435 151.805 ;
        RECT 24.080 151.620 30.435 151.760 ;
        RECT 24.080 151.560 24.400 151.620 ;
        RECT 30.145 151.575 30.435 151.620 ;
        RECT 111.235 151.760 111.525 151.805 ;
        RECT 115.160 151.760 115.480 151.820 ;
        RECT 111.235 151.620 115.480 151.760 ;
        RECT 111.235 151.575 111.525 151.620 ;
        RECT 115.160 151.560 115.480 151.620 ;
        RECT 27.090 150.970 30.450 151.295 ;
        RECT 31.410 150.970 38.130 151.295 ;
        RECT 49.170 150.970 56.370 151.295 ;
        RECT 59.250 150.970 66.450 151.295 ;
        RECT 104.850 150.970 111.570 151.295 ;
        RECT 24.690 150.370 113.970 150.970 ;
        RECT 24.690 150.045 34.770 150.370 ;
        RECT 49.650 150.045 56.850 150.370 ;
        RECT 58.770 150.045 65.970 150.370 ;
        RECT 98.130 150.045 111.570 150.370 ;
        RECT 30.980 149.720 31.300 149.780 ;
        RECT 27.390 149.580 31.300 149.720 ;
        RECT 27.390 149.085 27.530 149.580 ;
        RECT 30.980 149.520 31.300 149.580 ;
        RECT 101.235 149.720 101.465 149.795 ;
        RECT 103.200 149.720 103.520 149.780 ;
        RECT 101.235 149.580 103.520 149.720 ;
        RECT 101.235 149.505 101.465 149.580 ;
        RECT 103.200 149.520 103.520 149.580 ;
        RECT 27.255 148.855 27.545 149.085 ;
        RECT 23.620 148.700 23.940 148.760 ;
        RECT 27.795 148.700 28.025 148.775 ;
        RECT 33.715 148.700 34.005 148.745 ;
        RECT 56.495 148.700 56.785 148.745 ;
        RECT 57.175 148.700 57.465 148.745 ;
        RECT 65.675 148.700 65.965 148.745 ;
        RECT 66.695 148.700 66.985 148.745 ;
        RECT 23.620 148.560 28.025 148.700 ;
        RECT 23.620 148.500 23.940 148.560 ;
        RECT 27.795 148.485 28.025 148.560 ;
        RECT 31.070 148.560 34.005 148.700 ;
        RECT 31.070 148.420 31.210 148.560 ;
        RECT 33.715 148.515 34.005 148.560 ;
        RECT 56.370 148.560 66.985 148.700 ;
        RECT 56.370 148.515 56.785 148.560 ;
        RECT 57.175 148.515 57.465 148.560 ;
        RECT 65.675 148.515 65.965 148.560 ;
        RECT 66.695 148.515 66.985 148.560 ;
        RECT 100.695 148.700 100.985 148.745 ;
        RECT 105.960 148.700 106.280 148.760 ;
        RECT 107.155 148.700 107.445 148.745 ;
        RECT 100.695 148.560 107.445 148.700 ;
        RECT 100.695 148.515 100.985 148.560 ;
        RECT 30.315 148.360 30.605 148.405 ;
        RECT 30.980 148.360 31.300 148.420 ;
        RECT 56.370 148.405 56.510 148.515 ;
        RECT 28.680 148.340 29.000 148.355 ;
        RECT 25.725 148.295 26.015 148.340 ;
        RECT 28.615 148.295 29.000 148.340 ;
        RECT 25.725 148.155 29.850 148.295 ;
        RECT 30.315 148.220 31.300 148.360 ;
        RECT 32.015 148.295 32.305 148.340 ;
        RECT 30.315 148.175 30.605 148.220 ;
        RECT 30.980 148.160 31.300 148.220 ;
        RECT 25.725 148.110 26.015 148.155 ;
        RECT 28.615 148.110 29.000 148.155 ;
        RECT 28.680 148.095 29.000 148.110 ;
        RECT 29.710 148.020 29.850 148.155 ;
        RECT 31.530 148.155 32.305 148.295 ;
        RECT 56.155 148.220 56.510 148.405 ;
        RECT 60.880 148.405 61.200 148.420 ;
        RECT 103.830 148.405 103.970 148.560 ;
        RECT 105.960 148.500 106.280 148.560 ;
        RECT 107.155 148.515 107.445 148.560 ;
        RECT 107.835 148.700 108.125 148.745 ;
        RECT 113.320 148.700 113.640 148.760 ;
        RECT 107.835 148.560 113.640 148.700 ;
        RECT 107.835 148.515 108.125 148.560 ;
        RECT 113.320 148.500 113.640 148.560 ;
        RECT 110.560 148.405 110.880 148.420 ;
        RECT 60.880 148.360 61.205 148.405 ;
        RECT 60.880 148.220 61.395 148.360 ;
        RECT 99.165 148.295 99.455 148.340 ;
        RECT 102.565 148.295 102.855 148.340 ;
        RECT 56.155 148.175 56.445 148.220 ;
        RECT 60.880 148.175 61.205 148.220 ;
        RECT 60.880 148.160 61.200 148.175 ;
        RECT 31.530 148.020 31.670 148.155 ;
        RECT 32.015 148.110 32.305 148.155 ;
        RECT 99.165 148.155 102.970 148.295 ;
        RECT 103.755 148.175 104.045 148.405 ;
        RECT 110.555 148.360 110.880 148.405 ;
        RECT 104.210 148.340 105.875 148.360 ;
        RECT 108.720 148.340 109.040 148.355 ;
        RECT 104.210 148.295 106.085 148.340 ;
        RECT 108.685 148.295 109.040 148.340 ;
        RECT 104.210 148.220 109.040 148.295 ;
        RECT 110.365 148.220 110.880 148.360 ;
        RECT 99.165 148.110 99.455 148.155 ;
        RECT 102.565 148.110 102.970 148.155 ;
        RECT 29.710 147.880 31.670 148.020 ;
        RECT 102.830 148.020 102.970 148.110 ;
        RECT 104.210 148.020 104.350 148.220 ;
        RECT 105.735 148.155 109.040 148.220 ;
        RECT 110.555 148.175 110.880 148.220 ;
        RECT 110.560 148.160 110.880 148.175 ;
        RECT 105.795 148.110 106.085 148.155 ;
        RECT 108.685 148.110 109.040 148.155 ;
        RECT 108.720 148.095 109.040 148.110 ;
        RECT 102.830 147.880 104.350 148.020 ;
        RECT 25.460 147.680 25.780 147.740 ;
        RECT 30.995 147.680 31.285 147.725 ;
        RECT 25.460 147.540 31.285 147.680 ;
        RECT 25.460 147.480 25.780 147.540 ;
        RECT 30.995 147.495 31.285 147.540 ;
        RECT 33.740 147.680 34.060 147.740 ;
        RECT 34.395 147.680 34.685 147.725 ;
        RECT 33.740 147.540 34.685 147.680 ;
        RECT 33.740 147.480 34.060 147.540 ;
        RECT 34.395 147.495 34.685 147.540 ;
        RECT 104.435 147.680 104.725 147.725 ;
        RECT 105.500 147.680 105.820 147.740 ;
        RECT 104.435 147.540 105.820 147.680 ;
        RECT 104.435 147.495 104.725 147.540 ;
        RECT 105.500 147.480 105.820 147.540 ;
        RECT 111.235 147.680 111.525 147.725 ;
        RECT 115.160 147.680 115.480 147.740 ;
        RECT 111.235 147.540 115.480 147.680 ;
        RECT 111.235 147.495 111.525 147.540 ;
        RECT 115.160 147.480 115.480 147.540 ;
        RECT 24.690 146.900 34.770 147.225 ;
        RECT 49.650 146.900 56.850 147.225 ;
        RECT 58.770 146.900 65.970 147.225 ;
        RECT 98.130 146.900 111.570 147.225 ;
        RECT 24.690 146.300 113.970 146.900 ;
        RECT 27.090 145.975 33.810 146.300 ;
        RECT 104.850 145.975 111.570 146.300 ;
        RECT 105.530 145.500 108.900 145.640 ;
        RECT 26.575 145.040 26.865 145.085 ;
        RECT 27.595 145.040 27.885 145.085 ;
        RECT 28.680 145.040 29.000 145.100 ;
        RECT 105.530 145.085 105.670 145.500 ;
        RECT 108.760 145.100 108.900 145.500 ;
        RECT 108.720 145.085 109.040 145.100 ;
        RECT 30.995 145.040 31.285 145.085 ;
        RECT 26.575 144.900 31.285 145.040 ;
        RECT 26.575 144.855 26.865 144.900 ;
        RECT 27.595 144.855 27.885 144.900 ;
        RECT 28.680 144.840 29.000 144.900 ;
        RECT 30.995 144.855 31.285 144.900 ;
        RECT 33.035 144.775 33.325 145.005 ;
        RECT 105.455 144.855 105.745 145.085 ;
        RECT 108.685 145.040 109.040 145.085 ;
        RECT 105.960 144.960 106.280 145.020 ;
        RECT 107.155 144.960 107.445 145.005 ;
        RECT 105.960 144.820 107.570 144.960 ;
        RECT 108.525 144.900 109.040 145.040 ;
        RECT 110.560 145.005 110.880 145.020 ;
        RECT 110.555 144.960 110.880 145.005 ;
        RECT 108.685 144.855 109.040 144.900 ;
        RECT 108.720 144.840 109.040 144.855 ;
        RECT 110.365 144.820 110.880 144.960 ;
        RECT 29.635 144.620 29.925 144.665 ;
        RECT 30.980 144.620 31.300 144.680 ;
        RECT 33.110 144.620 33.250 144.775 ;
        RECT 105.960 144.760 106.280 144.820 ;
        RECT 107.155 144.775 107.570 144.820 ;
        RECT 110.555 144.775 110.880 144.820 ;
        RECT 33.740 144.620 34.060 144.680 ;
        RECT 29.635 144.480 34.060 144.620 ;
        RECT 107.430 144.620 107.570 144.775 ;
        RECT 110.560 144.760 110.880 144.775 ;
        RECT 110.630 144.620 110.770 144.760 ;
        RECT 107.430 144.480 110.770 144.620 ;
        RECT 29.635 144.435 29.925 144.480 ;
        RECT 30.980 144.420 31.300 144.480 ;
        RECT 33.740 144.420 34.060 144.480 ;
        RECT 107.835 144.280 108.125 144.325 ;
        RECT 113.320 144.280 113.640 144.340 ;
        RECT 107.835 144.140 113.640 144.280 ;
        RECT 107.835 144.095 108.125 144.140 ;
        RECT 113.320 144.080 113.640 144.140 ;
        RECT 25.920 143.940 26.240 144.000 ;
        RECT 33.375 143.940 33.665 143.985 ;
        RECT 25.920 143.800 33.665 143.940 ;
        RECT 25.920 143.740 26.240 143.800 ;
        RECT 33.375 143.755 33.665 143.800 ;
        RECT 25.000 143.600 25.320 143.660 ;
        RECT 30.145 143.600 30.435 143.645 ;
        RECT 25.000 143.460 30.435 143.600 ;
        RECT 25.000 143.400 25.320 143.460 ;
        RECT 30.145 143.415 30.435 143.460 ;
        RECT 111.235 143.600 111.525 143.645 ;
        RECT 115.160 143.600 115.480 143.660 ;
        RECT 111.235 143.460 115.480 143.600 ;
        RECT 111.235 143.415 111.525 143.460 ;
        RECT 115.160 143.400 115.480 143.460 ;
        RECT 27.090 142.830 33.810 143.155 ;
        RECT 104.850 142.830 111.570 143.155 ;
        RECT 24.690 142.230 113.970 142.830 ;
        RECT 30.930 141.905 41.010 142.230 ;
        RECT 104.850 141.905 111.570 142.230 ;
        RECT 25.920 141.560 26.240 141.620 ;
        RECT 37.285 141.560 37.575 141.605 ;
        RECT 25.920 141.420 37.575 141.560 ;
        RECT 25.920 141.360 26.240 141.420 ;
        RECT 37.285 141.375 37.575 141.420 ;
        RECT 111.235 141.560 111.525 141.605 ;
        RECT 112.860 141.560 113.180 141.620 ;
        RECT 111.235 141.420 113.180 141.560 ;
        RECT 111.235 141.375 111.525 141.420 ;
        RECT 112.860 141.360 113.180 141.420 ;
        RECT 110.560 140.880 110.880 140.940 ;
        RECT 107.430 140.740 110.880 140.880 ;
        RECT 25.920 140.540 26.240 140.600 ;
        RECT 40.685 140.540 40.975 140.585 ;
        RECT 25.920 140.400 40.975 140.540 ;
        RECT 25.920 140.340 26.240 140.400 ;
        RECT 40.685 140.355 40.975 140.400 ;
        RECT 26.575 140.200 26.865 140.245 ;
        RECT 31.675 140.200 31.965 140.245 ;
        RECT 35.075 140.200 35.365 140.245 ;
        RECT 38.135 140.200 38.425 140.245 ;
        RECT 26.575 140.060 38.425 140.200 ;
        RECT 26.575 140.015 26.865 140.060 ;
        RECT 31.675 140.015 31.965 140.060 ;
        RECT 35.075 140.015 35.365 140.060 ;
        RECT 38.135 140.015 38.425 140.060 ;
        RECT 103.660 140.200 103.980 140.260 ;
        RECT 107.430 140.245 107.570 140.740 ;
        RECT 110.560 140.680 110.880 140.740 ;
        RECT 107.835 140.540 108.125 140.585 ;
        RECT 113.320 140.540 113.640 140.600 ;
        RECT 107.835 140.400 113.640 140.540 ;
        RECT 107.835 140.355 108.125 140.400 ;
        RECT 113.320 140.340 113.640 140.400 ;
        RECT 105.455 140.200 105.745 140.245 ;
        RECT 103.660 140.060 105.745 140.200 ;
        RECT 103.660 140.000 103.980 140.060 ;
        RECT 105.455 140.015 105.745 140.060 ;
        RECT 107.155 140.060 107.570 140.245 ;
        RECT 108.720 140.245 109.040 140.260 ;
        RECT 110.560 140.245 110.880 140.260 ;
        RECT 107.155 140.015 107.445 140.060 ;
        RECT 108.720 140.015 109.145 140.245 ;
        RECT 110.555 140.200 110.880 140.245 ;
        RECT 110.365 140.060 110.880 140.200 ;
        RECT 110.555 140.015 110.880 140.060 ;
        RECT 33.280 139.905 33.600 139.920 ;
        RECT 33.280 139.860 33.665 139.905 ;
        RECT 36.775 139.860 37.065 139.905 ;
        RECT 40.175 139.860 40.465 139.905 ;
        RECT 33.280 139.720 40.465 139.860 ;
        RECT 105.530 139.860 105.670 140.015 ;
        RECT 108.720 140.000 109.040 140.015 ;
        RECT 110.560 140.000 110.880 140.015 ;
        RECT 108.810 139.860 108.950 140.000 ;
        RECT 105.530 139.720 108.950 139.860 ;
        RECT 33.280 139.675 33.665 139.720 ;
        RECT 36.775 139.675 37.065 139.720 ;
        RECT 40.175 139.675 40.465 139.720 ;
        RECT 33.280 139.660 33.600 139.675 ;
        RECT 25.920 139.520 26.240 139.580 ;
        RECT 33.885 139.520 34.175 139.565 ;
        RECT 25.920 139.380 34.175 139.520 ;
        RECT 25.920 139.320 26.240 139.380 ;
        RECT 33.885 139.335 34.175 139.380 ;
        RECT 30.930 138.760 41.010 139.085 ;
        RECT 104.850 138.760 111.570 139.085 ;
        RECT 24.690 138.160 113.970 138.760 ;
        RECT 27.090 137.835 33.810 138.160 ;
        RECT 101.970 137.835 112.050 138.160 ;
        RECT 25.920 137.480 26.240 137.540 ;
        RECT 30.145 137.480 30.435 137.525 ;
        RECT 25.920 137.340 30.435 137.480 ;
        RECT 25.920 137.280 26.240 137.340 ;
        RECT 30.145 137.295 30.435 137.340 ;
        RECT 111.745 137.480 112.035 137.525 ;
        RECT 112.860 137.480 113.180 137.540 ;
        RECT 111.745 137.340 113.180 137.480 ;
        RECT 111.745 137.295 112.035 137.340 ;
        RECT 112.860 137.280 113.180 137.340 ;
        RECT 26.575 136.900 26.865 136.945 ;
        RECT 27.595 136.900 27.885 136.945 ;
        RECT 30.995 136.900 31.285 136.945 ;
        RECT 26.575 136.760 31.285 136.900 ;
        RECT 102.565 136.900 102.855 136.945 ;
        RECT 103.660 136.900 103.980 136.960 ;
        RECT 105.795 136.900 106.085 136.945 ;
        RECT 109.195 136.900 109.485 136.945 ;
        RECT 26.575 136.715 26.865 136.760 ;
        RECT 27.595 136.715 27.885 136.760 ;
        RECT 30.995 136.715 31.285 136.760 ;
        RECT 33.035 136.800 33.325 136.845 ;
        RECT 33.740 136.800 34.060 136.860 ;
        RECT 33.035 136.660 34.060 136.800 ;
        RECT 102.565 136.760 109.485 136.900 ;
        RECT 102.565 136.715 102.855 136.760 ;
        RECT 103.660 136.700 103.980 136.760 ;
        RECT 105.795 136.715 106.085 136.760 ;
        RECT 109.195 136.715 109.485 136.760 ;
        RECT 33.035 136.615 33.325 136.660 ;
        RECT 29.635 136.460 29.925 136.505 ;
        RECT 33.110 136.460 33.250 136.615 ;
        RECT 33.740 136.600 34.060 136.660 ;
        RECT 29.635 136.320 33.250 136.460 ;
        RECT 110.560 136.460 110.880 136.520 ;
        RECT 111.235 136.460 111.525 136.505 ;
        RECT 110.560 136.320 111.525 136.460 ;
        RECT 29.635 136.275 29.925 136.320 ;
        RECT 110.560 136.260 110.880 136.320 ;
        RECT 111.235 136.275 111.525 136.320 ;
        RECT 103.200 136.120 103.520 136.180 ;
        RECT 104.435 136.120 104.725 136.165 ;
        RECT 103.200 135.980 104.725 136.120 ;
        RECT 103.200 135.920 103.520 135.980 ;
        RECT 104.435 135.935 104.725 135.980 ;
        RECT 104.945 136.120 105.235 136.165 ;
        RECT 105.500 136.120 105.820 136.180 ;
        RECT 104.945 135.980 105.820 136.120 ;
        RECT 104.945 135.935 105.235 135.980 ;
        RECT 105.500 135.920 105.820 135.980 ;
        RECT 107.835 136.120 108.125 136.165 ;
        RECT 110.650 136.120 110.790 136.260 ;
        RECT 107.835 135.980 110.790 136.120 ;
        RECT 107.835 135.935 108.125 135.980 ;
        RECT 25.920 135.780 26.240 135.840 ;
        RECT 33.375 135.780 33.665 135.825 ;
        RECT 25.920 135.640 33.665 135.780 ;
        RECT 25.920 135.580 26.240 135.640 ;
        RECT 33.375 135.595 33.665 135.640 ;
        RECT 108.345 135.440 108.635 135.485 ;
        RECT 111.020 135.440 111.340 135.500 ;
        RECT 108.345 135.300 111.340 135.440 ;
        RECT 108.345 135.255 108.635 135.300 ;
        RECT 111.020 135.240 111.340 135.300 ;
        RECT 27.090 134.690 33.810 135.015 ;
        RECT 101.970 134.690 112.050 135.015 ;
        RECT 24.690 134.090 113.970 134.690 ;
        RECT 27.570 133.765 37.650 134.090 ;
        RECT 101.490 133.765 111.570 134.090 ;
        RECT 33.740 132.860 34.060 133.120 ;
        RECT 26.915 132.720 27.205 132.765 ;
        RECT 29.975 132.720 30.265 132.765 ;
        RECT 33.830 132.720 33.970 132.860 ;
        RECT 36.775 132.720 37.065 132.765 ;
        RECT 26.915 132.580 37.065 132.720 ;
        RECT 26.915 132.535 27.205 132.580 ;
        RECT 29.975 132.535 30.265 132.580 ;
        RECT 28.770 132.240 31.670 132.380 ;
        RECT 26.575 132.040 26.865 132.085 ;
        RECT 28.275 132.040 28.565 132.085 ;
        RECT 28.770 132.040 28.910 132.240 ;
        RECT 31.530 132.085 31.670 132.240 ;
        RECT 33.740 132.180 34.060 132.440 ;
        RECT 31.505 132.040 31.795 132.085 ;
        RECT 33.830 132.040 33.970 132.180 ;
        RECT 35.075 132.040 35.365 132.085 ;
        RECT 26.575 131.900 28.910 132.040 ;
        RECT 29.690 131.900 31.210 132.040 ;
        RECT 26.575 131.855 26.865 131.900 ;
        RECT 28.275 131.855 28.565 131.900 ;
        RECT 25.920 131.700 26.240 131.760 ;
        RECT 29.690 131.700 29.830 131.900 ;
        RECT 25.920 131.560 29.830 131.700 ;
        RECT 25.920 131.500 26.240 131.560 ;
        RECT 25.460 131.360 25.780 131.420 ;
        RECT 30.685 131.360 30.915 131.435 ;
        RECT 25.460 131.220 30.915 131.360 ;
        RECT 31.070 131.360 31.210 131.900 ;
        RECT 31.505 131.900 35.365 132.040 ;
        RECT 31.505 131.855 31.795 131.900 ;
        RECT 35.075 131.855 35.365 131.900 ;
        RECT 33.375 131.700 33.665 131.745 ;
        RECT 35.670 131.700 35.810 132.580 ;
        RECT 36.775 132.535 37.065 132.580 ;
        RECT 103.660 132.520 103.980 132.780 ;
        RECT 103.750 132.380 103.890 132.520 ;
        RECT 102.130 132.240 105.670 132.380 ;
        RECT 102.130 132.085 102.270 132.240 ;
        RECT 102.055 131.855 102.345 132.085 ;
        RECT 103.200 132.040 103.520 132.100 ;
        RECT 105.530 132.085 105.670 132.240 ;
        RECT 108.720 132.085 109.040 132.100 ;
        RECT 110.560 132.085 110.880 132.100 ;
        RECT 103.755 132.040 104.045 132.085 ;
        RECT 103.200 131.900 104.045 132.040 ;
        RECT 103.200 131.840 103.520 131.900 ;
        RECT 103.755 131.855 104.045 131.900 ;
        RECT 105.455 132.040 105.745 132.085 ;
        RECT 108.720 132.040 109.145 132.085 ;
        RECT 110.555 132.040 110.880 132.085 ;
        RECT 105.455 131.900 109.475 132.040 ;
        RECT 110.365 131.900 110.880 132.040 ;
        RECT 105.455 131.855 105.745 131.900 ;
        RECT 108.720 131.855 109.145 131.900 ;
        RECT 110.555 131.855 110.880 131.900 ;
        RECT 33.375 131.560 35.810 131.700 ;
        RECT 103.830 131.700 103.970 131.855 ;
        RECT 108.720 131.840 109.040 131.855 ;
        RECT 110.560 131.840 110.880 131.855 ;
        RECT 107.325 131.700 107.615 131.745 ;
        RECT 103.830 131.560 107.615 131.700 ;
        RECT 33.375 131.515 33.665 131.560 ;
        RECT 107.325 131.515 107.615 131.560 ;
        RECT 107.835 131.700 108.125 131.745 ;
        RECT 113.320 131.700 113.640 131.760 ;
        RECT 107.835 131.560 113.640 131.700 ;
        RECT 107.835 131.515 108.125 131.560 ;
        RECT 113.320 131.500 113.640 131.560 ;
        RECT 33.885 131.360 34.175 131.405 ;
        RECT 31.070 131.220 34.175 131.360 ;
        RECT 25.460 131.160 25.780 131.220 ;
        RECT 30.685 131.145 30.915 131.220 ;
        RECT 33.885 131.175 34.175 131.220 ;
        RECT 35.580 131.360 35.900 131.420 ;
        RECT 37.285 131.360 37.575 131.405 ;
        RECT 35.580 131.220 37.575 131.360 ;
        RECT 35.580 131.160 35.900 131.220 ;
        RECT 37.285 131.175 37.575 131.220 ;
        RECT 104.435 131.360 104.725 131.405 ;
        RECT 105.960 131.360 106.280 131.420 ;
        RECT 104.435 131.220 106.280 131.360 ;
        RECT 104.435 131.175 104.725 131.220 ;
        RECT 105.960 131.160 106.280 131.220 ;
        RECT 111.235 131.360 111.525 131.405 ;
        RECT 113.780 131.360 114.100 131.420 ;
        RECT 111.235 131.220 114.100 131.360 ;
        RECT 111.235 131.175 111.525 131.220 ;
        RECT 113.780 131.160 114.100 131.220 ;
        RECT 27.570 130.620 37.650 130.945 ;
        RECT 101.490 130.620 111.570 130.945 ;
        RECT 24.690 130.020 113.970 130.620 ;
        RECT 27.570 129.695 41.010 130.020 ;
        RECT 101.490 129.695 111.570 130.020 ;
        RECT 25.000 129.320 25.320 129.380 ;
        RECT 30.685 129.320 30.915 129.395 ;
        RECT 25.000 129.180 30.915 129.320 ;
        RECT 25.000 129.120 25.320 129.180 ;
        RECT 30.685 129.105 30.915 129.180 ;
        RECT 36.040 129.320 36.360 129.380 ;
        RECT 107.800 129.365 108.120 129.380 ;
        RECT 37.285 129.320 37.575 129.365 ;
        RECT 36.040 129.180 37.575 129.320 ;
        RECT 36.040 129.120 36.360 129.180 ;
        RECT 37.285 129.135 37.575 129.180 ;
        RECT 107.800 129.320 108.125 129.365 ;
        RECT 111.235 129.320 111.525 129.365 ;
        RECT 112.860 129.320 113.180 129.380 ;
        RECT 107.800 129.180 108.315 129.320 ;
        RECT 111.235 129.180 113.180 129.320 ;
        RECT 107.800 129.135 108.125 129.180 ;
        RECT 111.235 129.135 111.525 129.180 ;
        RECT 107.800 129.120 108.120 129.135 ;
        RECT 112.860 129.120 113.180 129.180 ;
        RECT 28.615 128.760 28.905 128.805 ;
        RECT 31.505 128.760 31.795 128.805 ;
        RECT 33.740 128.760 34.060 128.820 ;
        RECT 34.905 128.760 35.195 128.805 ;
        RECT 38.135 128.760 38.425 128.805 ;
        RECT 28.615 128.620 38.425 128.760 ;
        RECT 28.615 128.575 28.905 128.620 ;
        RECT 31.505 128.575 31.795 128.620 ;
        RECT 33.740 128.560 34.060 128.620 ;
        RECT 34.905 128.575 35.195 128.620 ;
        RECT 38.135 128.575 38.425 128.620 ;
        RECT 102.225 128.640 102.515 128.805 ;
        RECT 105.455 128.760 105.745 128.805 ;
        RECT 105.960 128.760 106.280 128.820 ;
        RECT 108.720 128.805 109.040 128.820 ;
        RECT 108.685 128.760 109.040 128.805 ;
        RECT 103.200 128.640 103.520 128.700 ;
        RECT 103.755 128.640 104.045 128.685 ;
        RECT 102.225 128.575 102.950 128.640 ;
        RECT 102.300 128.500 102.950 128.575 ;
        RECT 25.920 128.300 26.240 128.360 ;
        RECT 40.685 128.300 40.975 128.345 ;
        RECT 25.920 128.160 40.975 128.300 ;
        RECT 25.920 128.100 26.240 128.160 ;
        RECT 40.685 128.115 40.975 128.160 ;
        RECT 26.915 127.960 27.205 128.005 ;
        RECT 29.975 127.960 30.265 128.005 ;
        RECT 33.375 127.960 33.665 128.005 ;
        RECT 35.580 127.960 35.900 128.020 ;
        RECT 36.775 127.960 37.065 128.005 ;
        RECT 40.175 127.960 40.465 128.005 ;
        RECT 26.915 127.820 40.465 127.960 ;
        RECT 102.810 127.960 102.950 128.500 ;
        RECT 103.200 128.500 104.045 128.640 ;
        RECT 105.455 128.620 109.040 128.760 ;
        RECT 110.560 128.685 110.880 128.700 ;
        RECT 105.455 128.575 105.745 128.620 ;
        RECT 105.960 128.560 106.280 128.620 ;
        RECT 108.685 128.575 109.040 128.620 ;
        RECT 108.720 128.560 109.040 128.575 ;
        RECT 103.200 128.440 103.520 128.500 ;
        RECT 103.755 128.455 104.045 128.500 ;
        RECT 110.555 128.455 110.880 128.685 ;
        RECT 103.830 128.300 103.970 128.455 ;
        RECT 110.560 128.440 110.880 128.455 ;
        RECT 107.325 128.300 107.615 128.345 ;
        RECT 110.630 128.300 110.770 128.440 ;
        RECT 103.830 128.160 110.770 128.300 ;
        RECT 107.325 128.115 107.615 128.160 ;
        RECT 105.960 127.960 106.280 128.020 ;
        RECT 102.810 127.820 106.280 127.960 ;
        RECT 26.915 127.775 27.205 127.820 ;
        RECT 29.975 127.775 30.265 127.820 ;
        RECT 33.375 127.775 33.665 127.820 ;
        RECT 35.580 127.760 35.900 127.820 ;
        RECT 36.775 127.775 37.065 127.820 ;
        RECT 40.175 127.775 40.465 127.820 ;
        RECT 105.960 127.760 106.280 127.820 ;
        RECT 33.740 127.325 34.060 127.340 ;
        RECT 33.740 127.095 34.175 127.325 ;
        RECT 104.435 127.280 104.725 127.325 ;
        RECT 105.500 127.280 105.820 127.340 ;
        RECT 104.435 127.140 105.820 127.280 ;
        RECT 104.435 127.095 104.725 127.140 ;
        RECT 33.740 127.080 34.060 127.095 ;
        RECT 105.500 127.080 105.820 127.140 ;
        RECT 27.570 126.550 41.010 126.875 ;
        RECT 101.490 126.550 111.570 126.875 ;
        RECT 24.690 125.950 113.970 126.550 ;
        RECT 27.090 125.625 33.810 125.950 ;
        RECT 101.970 125.625 112.050 125.950 ;
        RECT 25.460 124.560 25.780 124.620 ;
        RECT 30.145 124.560 30.435 124.605 ;
        RECT 25.460 124.420 30.435 124.560 ;
        RECT 25.460 124.360 25.780 124.420 ;
        RECT 30.145 124.375 30.435 124.420 ;
        RECT 104.945 124.560 105.235 124.605 ;
        RECT 105.500 124.560 105.820 124.620 ;
        RECT 104.945 124.420 105.820 124.560 ;
        RECT 104.945 124.375 105.235 124.420 ;
        RECT 105.500 124.360 105.820 124.420 ;
        RECT 111.745 124.560 112.035 124.605 ;
        RECT 112.860 124.560 113.180 124.620 ;
        RECT 111.745 124.420 113.180 124.560 ;
        RECT 111.745 124.375 112.035 124.420 ;
        RECT 112.860 124.360 113.180 124.420 ;
        RECT 29.635 124.220 29.925 124.265 ;
        RECT 33.035 124.220 33.325 124.265 ;
        RECT 35.580 124.220 35.900 124.280 ;
        RECT 29.635 124.080 35.900 124.220 ;
        RECT 29.635 124.035 29.925 124.080 ;
        RECT 33.035 124.035 33.325 124.080 ;
        RECT 35.580 124.020 35.900 124.080 ;
        RECT 105.960 123.925 106.280 123.940 ;
        RECT 26.575 123.880 26.865 123.925 ;
        RECT 27.595 123.880 27.885 123.925 ;
        RECT 30.995 123.880 31.285 123.925 ;
        RECT 26.575 123.740 31.285 123.880 ;
        RECT 26.575 123.695 26.865 123.740 ;
        RECT 27.595 123.695 27.885 123.740 ;
        RECT 30.995 123.695 31.285 123.740 ;
        RECT 100.015 123.880 100.305 123.925 ;
        RECT 102.735 123.880 103.025 123.925 ;
        RECT 105.795 123.880 106.280 123.925 ;
        RECT 109.195 123.880 109.485 123.925 ;
        RECT 100.015 123.740 109.485 123.880 ;
        RECT 100.015 123.695 100.305 123.740 ;
        RECT 102.735 123.695 103.025 123.740 ;
        RECT 105.795 123.695 106.280 123.740 ;
        RECT 109.195 123.695 109.485 123.740 ;
        RECT 105.960 123.680 106.280 123.695 ;
        RECT 103.200 123.540 103.520 123.600 ;
        RECT 104.435 123.540 104.725 123.585 ;
        RECT 107.835 123.540 108.125 123.585 ;
        RECT 111.235 123.540 111.525 123.585 ;
        RECT 103.200 123.400 111.525 123.540 ;
        RECT 103.200 123.340 103.520 123.400 ;
        RECT 104.435 123.355 104.725 123.400 ;
        RECT 107.835 123.355 108.125 123.400 ;
        RECT 111.235 123.355 111.525 123.400 ;
        RECT 25.920 123.200 26.240 123.260 ;
        RECT 33.375 123.200 33.665 123.245 ;
        RECT 25.920 123.060 33.665 123.200 ;
        RECT 25.920 123.000 26.240 123.060 ;
        RECT 33.375 123.015 33.665 123.060 ;
        RECT 108.345 123.200 108.635 123.245 ;
        RECT 110.560 123.200 110.880 123.260 ;
        RECT 108.345 123.060 110.880 123.200 ;
        RECT 108.345 123.015 108.635 123.060 ;
        RECT 110.560 123.000 110.880 123.060 ;
        RECT 27.090 122.480 33.810 122.805 ;
        RECT 101.970 122.480 112.050 122.805 ;
        RECT 24.690 121.880 113.970 122.480 ;
        RECT 27.090 121.555 30.450 121.880 ;
        RECT 33.330 121.555 40.050 121.880 ;
        RECT 100.530 121.555 103.890 121.880 ;
        RECT 104.850 121.555 111.570 121.880 ;
        RECT 25.920 121.160 26.240 121.220 ;
        RECT 30.145 121.160 30.435 121.205 ;
        RECT 35.580 121.160 35.900 121.220 ;
        RECT 25.920 121.020 30.435 121.160 ;
        RECT 25.920 120.960 26.240 121.020 ;
        RECT 30.145 120.975 30.435 121.020 ;
        RECT 32.450 121.020 35.900 121.160 ;
        RECT 29.635 120.820 29.925 120.865 ;
        RECT 30.655 120.820 30.945 120.865 ;
        RECT 32.450 120.820 32.590 121.020 ;
        RECT 35.580 120.960 35.900 121.020 ;
        RECT 36.040 121.205 36.360 121.220 ;
        RECT 103.660 121.205 103.980 121.220 ;
        RECT 36.040 120.975 36.555 121.205 ;
        RECT 103.585 120.975 103.980 121.205 ;
        RECT 111.235 121.160 111.525 121.205 ;
        RECT 113.320 121.160 113.640 121.220 ;
        RECT 111.235 121.020 113.640 121.160 ;
        RECT 111.235 120.975 111.525 121.020 ;
        RECT 36.040 120.960 36.360 120.975 ;
        RECT 103.660 120.960 103.980 120.975 ;
        RECT 113.320 120.960 113.640 121.020 ;
        RECT 28.220 120.695 28.540 120.710 ;
        RECT 26.575 120.650 26.865 120.695 ;
        RECT 28.105 120.650 28.540 120.695 ;
        RECT 26.575 120.510 28.540 120.650 ;
        RECT 29.635 120.680 32.590 120.820 ;
        RECT 101.110 120.695 105.670 120.820 ;
        RECT 29.635 120.635 29.925 120.680 ;
        RECT 30.655 120.635 30.945 120.680 ;
        RECT 33.885 120.650 34.175 120.695 ;
        RECT 37.285 120.650 37.575 120.695 ;
        RECT 26.575 120.465 26.865 120.510 ;
        RECT 28.105 120.480 28.540 120.510 ;
        RECT 32.910 120.510 37.575 120.650 ;
        RECT 32.910 120.480 33.050 120.510 ;
        RECT 28.105 120.465 33.050 120.480 ;
        RECT 33.885 120.465 34.175 120.510 ;
        RECT 37.285 120.465 37.575 120.510 ;
        RECT 100.015 120.650 100.305 120.695 ;
        RECT 101.035 120.680 105.745 120.695 ;
        RECT 101.035 120.650 101.325 120.680 ;
        RECT 100.015 120.510 101.325 120.650 ;
        RECT 100.015 120.465 100.305 120.510 ;
        RECT 101.035 120.465 101.325 120.510 ;
        RECT 105.455 120.650 105.745 120.680 ;
        RECT 108.685 120.650 108.975 120.695 ;
        RECT 105.455 120.510 108.975 120.650 ;
        RECT 105.455 120.465 105.745 120.510 ;
        RECT 108.685 120.465 108.975 120.510 ;
        RECT 28.220 120.450 33.050 120.465 ;
        RECT 28.310 120.340 33.050 120.450 ;
        RECT 110.555 120.295 110.845 120.525 ;
        RECT 33.740 120.140 34.060 120.200 ;
        RECT 39.665 120.140 39.955 120.185 ;
        RECT 110.630 120.140 110.770 120.295 ;
        RECT 33.740 120.000 39.955 120.140 ;
        RECT 33.740 119.940 34.060 120.000 ;
        RECT 39.665 119.955 39.955 120.000 ;
        RECT 107.400 120.000 110.770 120.140 ;
        RECT 35.580 119.845 35.900 119.860 ;
        RECT 103.200 119.845 103.520 119.860 ;
        RECT 107.400 119.845 107.540 120.000 ;
        RECT 35.580 119.800 36.045 119.845 ;
        RECT 39.155 119.800 39.445 119.845 ;
        RECT 35.580 119.660 39.445 119.800 ;
        RECT 35.580 119.615 36.045 119.660 ;
        RECT 39.155 119.615 39.445 119.660 ;
        RECT 103.075 119.800 103.520 119.845 ;
        RECT 107.325 119.800 107.615 119.845 ;
        RECT 103.075 119.660 107.615 119.800 ;
        RECT 103.075 119.615 103.520 119.660 ;
        RECT 107.325 119.615 107.615 119.660 ;
        RECT 107.835 119.800 108.125 119.845 ;
        RECT 113.320 119.800 113.640 119.860 ;
        RECT 107.835 119.660 113.640 119.800 ;
        RECT 107.835 119.615 108.125 119.660 ;
        RECT 35.580 119.600 35.900 119.615 ;
        RECT 103.200 119.600 103.520 119.615 ;
        RECT 113.320 119.600 113.640 119.660 ;
        RECT 27.090 118.410 30.450 118.735 ;
        RECT 33.330 118.410 40.050 118.735 ;
        RECT 100.530 118.410 103.890 118.735 ;
        RECT 104.850 118.410 111.570 118.735 ;
        RECT 24.690 117.810 113.970 118.410 ;
        RECT 27.090 117.485 30.450 117.810 ;
        RECT 31.890 117.485 35.250 117.810 ;
        RECT 101.490 117.485 111.570 117.810 ;
        RECT 25.920 117.080 26.240 117.140 ;
        RECT 107.800 117.125 108.120 117.140 ;
        RECT 30.145 117.080 30.435 117.125 ;
        RECT 25.920 116.940 30.435 117.080 ;
        RECT 25.920 116.880 26.240 116.940 ;
        RECT 30.145 116.895 30.435 116.940 ;
        RECT 107.800 117.080 108.125 117.125 ;
        RECT 111.235 117.080 111.525 117.125 ;
        RECT 112.860 117.080 113.180 117.140 ;
        RECT 107.800 116.940 108.315 117.080 ;
        RECT 111.235 116.940 113.180 117.080 ;
        RECT 107.800 116.895 108.125 116.940 ;
        RECT 111.235 116.895 111.525 116.940 ;
        RECT 107.800 116.880 108.120 116.895 ;
        RECT 112.860 116.880 113.180 116.940 ;
        RECT 25.920 116.060 26.240 116.120 ;
        RECT 34.905 116.060 35.195 116.105 ;
        RECT 25.920 115.920 35.195 116.060 ;
        RECT 25.920 115.860 26.240 115.920 ;
        RECT 34.905 115.875 35.195 115.920 ;
        RECT 103.200 116.060 103.520 116.120 ;
        RECT 103.755 116.060 104.045 116.105 ;
        RECT 107.155 116.060 107.445 116.105 ;
        RECT 110.555 116.060 110.845 116.105 ;
        RECT 103.200 115.920 110.845 116.060 ;
        RECT 103.200 115.860 103.520 115.920 ;
        RECT 103.755 115.875 104.045 115.920 ;
        RECT 107.155 115.875 107.445 115.920 ;
        RECT 110.555 115.875 110.845 115.920 ;
        RECT 27.595 115.720 27.885 115.765 ;
        RECT 28.220 115.720 28.540 115.780 ;
        RECT 32.355 115.720 32.645 115.765 ;
        RECT 27.595 115.580 32.645 115.720 ;
        RECT 27.595 115.535 27.885 115.580 ;
        RECT 28.220 115.520 28.540 115.580 ;
        RECT 32.355 115.535 32.645 115.580 ;
        RECT 100.015 115.720 100.305 115.765 ;
        RECT 102.055 115.720 102.345 115.765 ;
        RECT 105.455 115.720 105.745 115.765 ;
        RECT 108.855 115.720 109.145 115.765 ;
        RECT 100.015 115.580 109.145 115.720 ;
        RECT 100.015 115.535 100.305 115.580 ;
        RECT 102.055 115.535 102.345 115.580 ;
        RECT 105.455 115.535 105.745 115.580 ;
        RECT 108.855 115.535 109.145 115.580 ;
        RECT 28.680 115.380 29.000 115.440 ;
        RECT 29.635 115.380 29.925 115.425 ;
        RECT 30.655 115.380 30.945 115.425 ;
        RECT 34.395 115.380 34.685 115.425 ;
        RECT 28.680 115.240 34.685 115.380 ;
        RECT 28.680 115.180 29.000 115.240 ;
        RECT 29.635 115.195 29.925 115.240 ;
        RECT 30.655 115.195 30.945 115.240 ;
        RECT 34.395 115.195 34.685 115.240 ;
        RECT 104.435 115.040 104.725 115.085 ;
        RECT 105.500 115.040 105.820 115.100 ;
        RECT 104.435 114.900 105.820 115.040 ;
        RECT 104.435 114.855 104.725 114.900 ;
        RECT 105.500 114.840 105.820 114.900 ;
        RECT 27.090 114.340 30.450 114.665 ;
        RECT 31.890 114.340 35.250 114.665 ;
        RECT 101.490 114.340 111.570 114.665 ;
        RECT 24.690 113.740 113.970 114.340 ;
        RECT 27.090 113.415 37.170 113.740 ;
        RECT 101.010 113.415 104.370 113.740 ;
        RECT 104.850 113.415 111.570 113.740 ;
        RECT 25.460 113.000 25.780 113.060 ;
        RECT 107.800 113.045 108.120 113.060 ;
        RECT 30.145 113.000 30.435 113.045 ;
        RECT 25.460 112.860 30.435 113.000 ;
        RECT 25.460 112.800 25.780 112.860 ;
        RECT 30.145 112.815 30.435 112.860 ;
        RECT 107.800 113.000 108.125 113.045 ;
        RECT 111.235 113.000 111.525 113.045 ;
        RECT 112.860 113.000 113.180 113.060 ;
        RECT 107.800 112.860 108.315 113.000 ;
        RECT 111.235 112.860 113.180 113.000 ;
        RECT 107.800 112.815 108.125 112.860 ;
        RECT 111.235 112.815 111.525 112.860 ;
        RECT 107.800 112.800 108.120 112.815 ;
        RECT 112.860 112.800 113.180 112.860 ;
        RECT 28.220 112.535 28.540 112.550 ;
        RECT 31.070 112.535 33.970 112.660 ;
        RECT 28.105 112.490 28.540 112.535 ;
        RECT 30.995 112.520 33.970 112.535 ;
        RECT 30.995 112.490 31.285 112.520 ;
        RECT 28.105 112.350 31.285 112.490 ;
        RECT 33.830 112.490 33.970 112.520 ;
        RECT 34.395 112.490 34.685 112.535 ;
        RECT 28.105 112.305 28.540 112.350 ;
        RECT 30.995 112.305 31.285 112.350 ;
        RECT 33.035 112.320 33.325 112.365 ;
        RECT 33.830 112.350 34.685 112.490 ;
        RECT 100.015 112.490 100.305 112.535 ;
        RECT 101.545 112.490 101.835 112.535 ;
        RECT 105.455 112.490 105.745 112.535 ;
        RECT 108.685 112.490 108.975 112.535 ;
        RECT 28.220 112.290 28.540 112.305 ;
        RECT 32.910 112.135 33.325 112.320 ;
        RECT 34.395 112.305 34.685 112.350 ;
        RECT 36.095 112.320 36.385 112.365 ;
        RECT 35.210 112.180 36.385 112.320 ;
        RECT 100.015 112.350 108.975 112.490 ;
        RECT 100.015 112.305 100.305 112.350 ;
        RECT 101.545 112.305 101.835 112.350 ;
        RECT 105.455 112.305 105.745 112.350 ;
        RECT 108.685 112.305 108.975 112.350 ;
        RECT 28.680 111.980 29.000 112.040 ;
        RECT 29.635 111.980 29.925 112.025 ;
        RECT 32.910 111.980 33.050 112.135 ;
        RECT 35.210 111.980 35.350 112.180 ;
        RECT 36.095 112.135 36.385 112.180 ;
        RECT 110.555 112.135 110.845 112.365 ;
        RECT 28.680 111.840 35.350 111.980 ;
        RECT 103.200 112.025 103.520 112.040 ;
        RECT 103.200 111.980 103.705 112.025 ;
        RECT 107.325 111.980 107.615 112.025 ;
        RECT 110.630 111.980 110.770 112.135 ;
        RECT 103.200 111.840 110.770 111.980 ;
        RECT 28.680 111.780 29.000 111.840 ;
        RECT 29.635 111.795 29.925 111.840 ;
        RECT 103.200 111.795 103.705 111.840 ;
        RECT 107.325 111.795 107.615 111.840 ;
        RECT 103.200 111.780 103.520 111.795 ;
        RECT 25.920 111.640 26.240 111.700 ;
        RECT 36.775 111.640 37.065 111.685 ;
        RECT 25.920 111.500 37.065 111.640 ;
        RECT 25.920 111.440 26.240 111.500 ;
        RECT 36.775 111.455 37.065 111.500 ;
        RECT 24.540 111.300 24.860 111.360 ;
        RECT 33.375 111.300 33.665 111.345 ;
        RECT 24.540 111.160 33.665 111.300 ;
        RECT 24.540 111.100 24.860 111.160 ;
        RECT 33.375 111.115 33.665 111.160 ;
        RECT 104.125 110.960 104.355 111.035 ;
        RECT 105.500 110.960 105.820 111.020 ;
        RECT 104.125 110.820 105.820 110.960 ;
        RECT 104.125 110.745 104.355 110.820 ;
        RECT 105.500 110.760 105.820 110.820 ;
        RECT 27.090 110.270 37.170 110.595 ;
        RECT 101.010 110.270 104.370 110.595 ;
        RECT 104.850 110.270 111.570 110.595 ;
        RECT 24.690 109.670 113.970 110.270 ;
        RECT 27.090 109.345 30.450 109.670 ;
        RECT 30.930 109.345 41.010 109.670 ;
        RECT 100.530 109.345 103.890 109.670 ;
        RECT 104.370 109.345 111.090 109.670 ;
        RECT 25.000 108.920 25.320 108.980 ;
        RECT 30.145 108.920 30.435 108.965 ;
        RECT 25.000 108.780 30.435 108.920 ;
        RECT 25.000 108.720 25.320 108.780 ;
        RECT 30.145 108.735 30.435 108.780 ;
        RECT 36.040 108.920 36.360 108.980 ;
        RECT 103.660 108.965 103.980 108.980 ;
        RECT 37.285 108.920 37.575 108.965 ;
        RECT 36.040 108.780 37.575 108.920 ;
        RECT 36.040 108.720 36.360 108.780 ;
        RECT 37.285 108.735 37.575 108.780 ;
        RECT 103.585 108.735 103.980 108.965 ;
        RECT 103.660 108.720 103.980 108.735 ;
        RECT 110.560 108.965 110.880 108.980 ;
        RECT 110.560 108.735 111.015 108.965 ;
        RECT 110.560 108.720 110.880 108.735 ;
        RECT 25.920 108.240 26.240 108.300 ;
        RECT 33.885 108.240 34.175 108.285 ;
        RECT 25.920 108.100 34.175 108.240 ;
        RECT 25.920 108.040 26.240 108.100 ;
        RECT 33.885 108.055 34.175 108.100 ;
        RECT 107.325 108.240 107.615 108.285 ;
        RECT 113.320 108.240 113.640 108.300 ;
        RECT 107.325 108.100 113.640 108.240 ;
        RECT 107.325 108.055 107.615 108.100 ;
        RECT 113.320 108.040 113.640 108.100 ;
        RECT 35.580 107.900 35.900 107.960 ;
        RECT 40.685 107.900 40.975 107.945 ;
        RECT 35.580 107.760 40.975 107.900 ;
        RECT 35.580 107.700 35.900 107.760 ;
        RECT 40.685 107.715 40.975 107.760 ;
        RECT 27.595 107.560 27.885 107.605 ;
        RECT 28.220 107.560 28.540 107.620 ;
        RECT 31.675 107.560 31.965 107.605 ;
        RECT 35.075 107.560 35.365 107.605 ;
        RECT 38.135 107.560 38.425 107.605 ;
        RECT 27.595 107.420 38.425 107.560 ;
        RECT 27.595 107.375 27.885 107.420 ;
        RECT 28.220 107.360 28.540 107.420 ;
        RECT 31.675 107.375 31.965 107.420 ;
        RECT 35.075 107.375 35.365 107.420 ;
        RECT 38.135 107.375 38.425 107.420 ;
        RECT 100.015 107.560 100.305 107.605 ;
        RECT 101.035 107.560 101.325 107.605 ;
        RECT 105.115 107.560 105.405 107.605 ;
        RECT 108.515 107.560 108.805 107.605 ;
        RECT 100.015 107.420 108.805 107.560 ;
        RECT 100.015 107.375 100.305 107.420 ;
        RECT 101.035 107.375 101.325 107.420 ;
        RECT 105.115 107.375 105.405 107.420 ;
        RECT 108.515 107.375 108.805 107.420 ;
        RECT 28.680 107.220 29.000 107.280 ;
        RECT 29.635 107.220 29.925 107.265 ;
        RECT 33.375 107.220 33.665 107.265 ;
        RECT 36.775 107.220 37.065 107.265 ;
        RECT 40.175 107.220 40.465 107.265 ;
        RECT 28.680 107.080 40.465 107.220 ;
        RECT 28.680 107.020 29.000 107.080 ;
        RECT 29.635 107.035 29.925 107.080 ;
        RECT 33.375 107.035 33.665 107.080 ;
        RECT 36.775 107.035 37.065 107.080 ;
        RECT 40.175 107.035 40.465 107.080 ;
        RECT 103.075 107.220 103.365 107.265 ;
        RECT 103.660 107.220 103.980 107.280 ;
        RECT 106.815 107.220 107.105 107.265 ;
        RECT 110.215 107.220 110.505 107.265 ;
        RECT 103.075 107.080 110.505 107.220 ;
        RECT 103.075 107.035 103.365 107.080 ;
        RECT 103.660 107.020 103.980 107.080 ;
        RECT 106.815 107.035 107.105 107.080 ;
        RECT 110.215 107.035 110.505 107.080 ;
        RECT 27.090 106.200 30.450 106.525 ;
        RECT 30.930 106.200 41.010 106.525 ;
        RECT 100.530 106.200 103.890 106.525 ;
        RECT 104.370 106.200 111.090 106.525 ;
        RECT 24.690 105.600 113.970 106.200 ;
        RECT 27.090 105.275 37.170 105.600 ;
        RECT 101.490 105.275 111.570 105.600 ;
        RECT 28.220 104.375 28.540 104.390 ;
        RECT 31.070 104.375 33.970 104.500 ;
        RECT 102.130 104.375 108.900 104.500 ;
        RECT 28.105 104.330 28.540 104.375 ;
        RECT 30.995 104.360 33.970 104.375 ;
        RECT 30.995 104.330 31.285 104.360 ;
        RECT 28.105 104.190 31.285 104.330 ;
        RECT 33.830 104.330 33.970 104.360 ;
        RECT 34.395 104.330 34.685 104.375 ;
        RECT 28.105 104.145 28.540 104.190 ;
        RECT 30.995 104.145 31.285 104.190 ;
        RECT 33.035 104.160 33.325 104.205 ;
        RECT 33.830 104.190 34.685 104.330 ;
        RECT 102.055 104.360 108.975 104.375 ;
        RECT 28.220 104.130 28.540 104.145 ;
        RECT 32.910 103.975 33.325 104.160 ;
        RECT 34.395 104.145 34.685 104.190 ;
        RECT 36.095 104.160 36.385 104.205 ;
        RECT 35.210 104.020 36.385 104.160 ;
        RECT 28.680 103.820 29.000 103.880 ;
        RECT 29.635 103.820 29.925 103.865 ;
        RECT 32.910 103.820 33.050 103.975 ;
        RECT 35.210 103.820 35.350 104.020 ;
        RECT 36.095 103.975 36.385 104.020 ;
        RECT 98.600 104.160 98.920 104.220 ;
        RECT 100.015 104.160 100.305 104.205 ;
        RECT 102.055 104.160 102.345 104.360 ;
        RECT 98.600 104.145 102.345 104.160 ;
        RECT 103.660 104.205 103.980 104.220 ;
        RECT 98.600 104.020 102.270 104.145 ;
        RECT 98.600 103.960 98.920 104.020 ;
        RECT 100.015 103.975 100.305 104.020 ;
        RECT 103.660 103.975 104.045 104.205 ;
        RECT 105.455 104.145 105.745 104.360 ;
        RECT 108.685 104.145 108.975 104.360 ;
        RECT 110.555 103.975 110.845 104.205 ;
        RECT 103.660 103.960 103.980 103.975 ;
        RECT 28.680 103.680 35.350 103.820 ;
        RECT 103.830 103.820 103.970 103.960 ;
        RECT 107.325 103.820 107.615 103.865 ;
        RECT 110.630 103.820 110.770 103.975 ;
        RECT 103.830 103.680 110.770 103.820 ;
        RECT 28.680 103.620 29.000 103.680 ;
        RECT 29.635 103.635 29.925 103.680 ;
        RECT 107.325 103.635 107.615 103.680 ;
        RECT 25.920 103.140 26.240 103.200 ;
        RECT 107.800 103.185 108.120 103.200 ;
        RECT 33.375 103.140 33.665 103.185 ;
        RECT 25.920 103.000 33.665 103.140 ;
        RECT 25.920 102.940 26.240 103.000 ;
        RECT 33.375 102.955 33.665 103.000 ;
        RECT 107.800 103.140 108.125 103.185 ;
        RECT 111.235 103.140 111.525 103.185 ;
        RECT 112.860 103.140 113.180 103.200 ;
        RECT 107.800 103.000 108.315 103.140 ;
        RECT 111.235 103.000 113.180 103.140 ;
        RECT 107.800 102.955 108.125 103.000 ;
        RECT 111.235 102.955 111.525 103.000 ;
        RECT 107.800 102.940 108.120 102.955 ;
        RECT 112.860 102.940 113.180 103.000 ;
        RECT 24.540 102.800 24.860 102.860 ;
        RECT 30.145 102.800 30.435 102.845 ;
        RECT 24.540 102.660 30.435 102.800 ;
        RECT 24.540 102.600 24.860 102.660 ;
        RECT 30.145 102.615 30.435 102.660 ;
        RECT 35.580 102.800 35.900 102.860 ;
        RECT 36.775 102.800 37.065 102.845 ;
        RECT 35.580 102.660 37.065 102.800 ;
        RECT 35.580 102.600 35.900 102.660 ;
        RECT 36.775 102.615 37.065 102.660 ;
        RECT 104.435 102.800 104.725 102.845 ;
        RECT 105.500 102.800 105.820 102.860 ;
        RECT 104.435 102.660 105.820 102.800 ;
        RECT 104.435 102.615 104.725 102.660 ;
        RECT 105.500 102.600 105.820 102.660 ;
        RECT 27.090 102.130 37.170 102.455 ;
        RECT 101.490 102.130 111.570 102.455 ;
        RECT 24.690 101.530 113.970 102.130 ;
        RECT 27.090 101.205 30.450 101.530 ;
        RECT 32.850 101.205 36.210 101.530 ;
        RECT 97.650 101.205 111.090 101.530 ;
        RECT 35.955 100.820 36.185 100.835 ;
        RECT 25.460 100.760 25.780 100.820 ;
        RECT 30.145 100.760 30.435 100.805 ;
        RECT 25.460 100.620 30.435 100.760 ;
        RECT 25.460 100.560 25.780 100.620 ;
        RECT 30.145 100.575 30.435 100.620 ;
        RECT 35.955 100.560 36.360 100.820 ;
        RECT 107.325 100.760 107.615 100.805 ;
        RECT 107.800 100.760 108.120 100.820 ;
        RECT 107.325 100.620 108.120 100.760 ;
        RECT 107.325 100.575 107.615 100.620 ;
        RECT 107.800 100.560 108.120 100.620 ;
        RECT 110.560 100.805 110.880 100.820 ;
        RECT 110.560 100.575 111.015 100.805 ;
        RECT 110.560 100.560 110.880 100.575 ;
        RECT 35.955 100.545 36.185 100.560 ;
        RECT 103.660 100.125 103.980 100.140 ;
        RECT 100.185 100.080 100.475 100.125 ;
        RECT 103.415 100.080 103.980 100.125 ;
        RECT 105.960 100.080 106.280 100.140 ;
        RECT 106.815 100.080 107.105 100.125 ;
        RECT 100.185 99.940 108.900 100.080 ;
        RECT 100.185 99.895 100.475 99.940 ;
        RECT 103.415 99.895 103.980 99.940 ;
        RECT 103.660 99.880 103.980 99.895 ;
        RECT 105.960 99.880 106.280 99.940 ;
        RECT 106.815 99.895 107.105 99.940 ;
        RECT 108.760 99.740 108.900 99.940 ;
        RECT 108.760 99.600 110.430 99.740 ;
        RECT 28.220 99.500 28.540 99.515 ;
        RECT 33.740 99.500 34.060 99.515 ;
        RECT 28.105 99.270 28.540 99.500 ;
        RECT 28.220 99.255 28.540 99.270 ;
        RECT 28.680 99.400 29.000 99.460 ;
        RECT 33.715 99.455 34.060 99.500 ;
        RECT 98.600 99.500 98.920 99.515 ;
        RECT 29.635 99.400 29.925 99.445 ;
        RECT 28.680 99.260 29.925 99.400 ;
        RECT 33.545 99.315 34.060 99.455 ;
        RECT 35.580 99.445 35.900 99.460 ;
        RECT 33.715 99.270 34.060 99.315 ;
        RECT 28.680 99.200 29.000 99.260 ;
        RECT 29.635 99.215 29.925 99.260 ;
        RECT 33.740 99.255 34.060 99.270 ;
        RECT 35.415 99.215 35.900 99.445 ;
        RECT 98.600 99.455 98.945 99.500 ;
        RECT 98.600 99.400 99.115 99.455 ;
        RECT 101.545 99.400 101.835 99.500 ;
        RECT 98.600 99.270 101.835 99.400 ;
        RECT 104.945 99.455 105.235 99.500 ;
        RECT 107.800 99.455 108.120 99.515 ;
        RECT 108.345 99.455 108.635 99.500 ;
        RECT 104.945 99.315 108.635 99.455 ;
        RECT 110.290 99.445 110.430 99.600 ;
        RECT 104.945 99.270 105.235 99.315 ;
        RECT 98.600 99.260 101.760 99.270 ;
        RECT 98.600 99.255 98.920 99.260 ;
        RECT 107.800 99.255 108.120 99.315 ;
        RECT 108.345 99.270 108.635 99.315 ;
        RECT 110.215 99.215 110.505 99.445 ;
        RECT 35.580 99.200 35.900 99.215 ;
        RECT 100.900 99.105 101.220 99.120 ;
        RECT 100.695 98.875 101.220 99.105 ;
        RECT 100.900 98.860 101.220 98.875 ;
        RECT 104.125 99.060 104.355 99.135 ;
        RECT 105.500 99.060 105.820 99.120 ;
        RECT 104.125 98.920 105.820 99.060 ;
        RECT 104.125 98.845 104.355 98.920 ;
        RECT 105.500 98.860 105.820 98.920 ;
        RECT 27.090 98.060 30.450 98.385 ;
        RECT 32.850 98.060 36.210 98.385 ;
        RECT 97.650 98.060 111.090 98.385 ;
        RECT 24.690 97.460 113.970 98.060 ;
        RECT 27.090 97.135 43.890 97.460 ;
        RECT 58.335 96.930 58.660 97.280 ;
        RECT 99.570 97.135 106.290 97.460 ;
        RECT 108.210 97.135 111.570 97.460 ;
        RECT 33.740 96.340 34.060 96.400 ;
        RECT 58.385 96.340 58.610 96.930 ;
        RECT 98.600 96.680 98.920 96.740 ;
        RECT 100.440 96.680 100.760 96.740 ;
        RECT 69.735 96.540 103.630 96.680 ;
        RECT 69.735 96.340 69.875 96.540 ;
        RECT 98.600 96.480 98.920 96.540 ;
        RECT 100.440 96.480 100.760 96.540 ;
        RECT 28.220 96.215 28.540 96.230 ;
        RECT 28.105 96.170 28.540 96.215 ;
        RECT 30.520 96.170 30.840 96.230 ;
        RECT 31.505 96.170 31.795 96.215 ;
        RECT 32.450 96.200 69.875 96.340 ;
        RECT 100.530 96.215 100.670 96.480 ;
        RECT 103.490 96.340 103.630 96.540 ;
        RECT 107.800 96.340 108.120 96.400 ;
        RECT 103.490 96.215 108.120 96.340 ;
        RECT 32.450 96.170 32.590 96.200 ;
        RECT 28.105 96.030 32.590 96.170 ;
        RECT 33.740 96.140 34.060 96.200 ;
        RECT 28.105 95.985 28.540 96.030 ;
        RECT 28.220 95.970 28.540 95.985 ;
        RECT 30.520 95.970 30.840 96.030 ;
        RECT 31.505 95.985 31.795 96.030 ;
        RECT 33.035 96.000 33.325 96.045 ;
        RECT 32.910 95.815 33.325 96.000 ;
        RECT 34.735 95.985 35.025 96.200 ;
        RECT 35.580 96.000 35.900 96.060 ;
        RECT 36.095 96.000 36.385 96.045 ;
        RECT 35.210 95.860 36.385 96.000 ;
        RECT 37.965 95.985 38.255 96.200 ;
        RECT 39.495 96.000 39.785 96.045 ;
        RECT 41.190 96.030 41.485 96.200 ;
        RECT 28.680 95.660 29.000 95.720 ;
        RECT 29.635 95.660 29.925 95.705 ;
        RECT 32.910 95.660 33.050 95.815 ;
        RECT 35.210 95.660 35.350 95.860 ;
        RECT 35.580 95.800 35.900 95.860 ;
        RECT 36.095 95.815 36.385 95.860 ;
        RECT 38.430 95.860 39.785 96.000 ;
        RECT 41.195 95.985 41.485 96.030 ;
        RECT 42.895 96.000 43.185 96.045 ;
        RECT 44.255 96.000 44.545 96.045 ;
        RECT 38.430 95.660 38.570 95.860 ;
        RECT 39.495 95.815 39.785 95.860 ;
        RECT 42.895 95.860 44.545 96.000 ;
        RECT 100.355 96.030 100.670 96.215 ;
        RECT 103.415 96.200 108.120 96.215 ;
        RECT 100.355 95.985 100.645 96.030 ;
        RECT 103.415 95.985 103.705 96.200 ;
        RECT 107.800 96.170 108.120 96.200 ;
        RECT 109.195 96.170 109.485 96.215 ;
        RECT 107.800 96.140 109.485 96.170 ;
        RECT 105.960 96.000 106.280 96.060 ;
        RECT 107.910 96.030 109.485 96.140 ;
        RECT 110.560 96.045 110.880 96.060 ;
        RECT 42.895 95.815 43.185 95.860 ;
        RECT 44.255 95.815 44.545 95.860 ;
        RECT 105.530 95.860 106.280 96.000 ;
        RECT 109.195 95.985 109.485 96.030 ;
        RECT 110.555 96.000 110.880 96.045 ;
        RECT 110.365 95.860 110.880 96.000 ;
        RECT 28.680 95.520 38.570 95.660 ;
        RECT 100.900 95.660 101.220 95.720 ;
        RECT 105.530 95.705 105.670 95.860 ;
        RECT 105.960 95.800 106.280 95.860 ;
        RECT 110.555 95.815 110.880 95.860 ;
        RECT 110.560 95.800 110.880 95.815 ;
        RECT 102.055 95.660 102.345 95.705 ;
        RECT 105.455 95.660 105.745 95.705 ;
        RECT 100.900 95.520 105.745 95.660 ;
        RECT 28.680 95.460 29.000 95.520 ;
        RECT 29.635 95.475 29.925 95.520 ;
        RECT 100.900 95.460 101.220 95.520 ;
        RECT 102.055 95.475 102.345 95.520 ;
        RECT 105.455 95.475 105.745 95.520 ;
        RECT 25.920 95.320 26.240 95.380 ;
        RECT 33.375 95.320 33.665 95.365 ;
        RECT 25.920 95.180 33.665 95.320 ;
        RECT 25.920 95.120 26.240 95.180 ;
        RECT 33.375 95.135 33.665 95.180 ;
        RECT 41.100 95.320 41.420 95.380 ;
        RECT 43.575 95.320 43.865 95.365 ;
        RECT 41.100 95.180 43.865 95.320 ;
        RECT 41.100 95.120 41.420 95.180 ;
        RECT 43.575 95.135 43.865 95.180 ;
        RECT 105.965 95.320 106.255 95.365 ;
        RECT 116.080 95.320 116.400 95.380 ;
        RECT 105.965 95.180 116.400 95.320 ;
        RECT 105.965 95.135 106.255 95.180 ;
        RECT 116.080 95.120 116.400 95.180 ;
        RECT 25.460 94.980 25.780 95.040 ;
        RECT 30.145 94.980 30.435 95.025 ;
        RECT 25.460 94.840 30.435 94.980 ;
        RECT 25.460 94.780 25.780 94.840 ;
        RECT 30.145 94.795 30.435 94.840 ;
        RECT 35.580 94.980 35.900 95.040 ;
        RECT 36.775 94.980 37.065 95.025 ;
        RECT 35.580 94.840 37.065 94.980 ;
        RECT 35.580 94.780 35.900 94.840 ;
        RECT 36.775 94.795 37.065 94.840 ;
        RECT 102.565 94.980 102.855 95.025 ;
        RECT 112.860 94.980 113.180 95.040 ;
        RECT 102.565 94.840 113.180 94.980 ;
        RECT 102.565 94.795 102.855 94.840 ;
        RECT 112.860 94.780 113.180 94.840 ;
        RECT 25.000 94.640 25.320 94.700 ;
        RECT 40.175 94.640 40.465 94.685 ;
        RECT 25.000 94.500 40.465 94.640 ;
        RECT 25.000 94.440 25.320 94.500 ;
        RECT 40.175 94.455 40.465 94.500 ;
        RECT 111.235 94.640 111.525 94.685 ;
        RECT 115.160 94.640 115.480 94.700 ;
        RECT 111.235 94.500 115.480 94.640 ;
        RECT 111.235 94.455 111.525 94.500 ;
        RECT 115.160 94.440 115.480 94.500 ;
        RECT 27.090 93.990 43.890 94.315 ;
        RECT 99.570 93.990 106.290 94.315 ;
        RECT 108.210 93.990 111.570 94.315 ;
        RECT 24.690 93.390 113.970 93.990 ;
        RECT 26.130 93.065 42.930 93.390 ;
        RECT 100.530 93.065 113.970 93.390 ;
        RECT 25.920 92.600 26.240 92.660 ;
        RECT 32.525 92.600 32.815 92.645 ;
        RECT 25.920 92.460 32.815 92.600 ;
        RECT 25.920 92.400 26.240 92.460 ;
        RECT 32.525 92.415 32.815 92.460 ;
        RECT 41.100 92.600 41.420 92.660 ;
        RECT 103.660 92.645 103.980 92.660 ;
        RECT 42.555 92.600 42.845 92.645 ;
        RECT 41.100 92.460 42.845 92.600 ;
        RECT 41.100 92.400 41.420 92.460 ;
        RECT 42.555 92.415 42.845 92.460 ;
        RECT 103.585 92.415 103.980 92.645 ;
        RECT 103.660 92.400 103.980 92.415 ;
        RECT 28.680 91.965 29.000 91.980 ;
        RECT 28.615 91.920 29.000 91.965 ;
        RECT 35.415 91.920 35.705 91.965 ;
        RECT 100.900 91.920 101.220 91.980 ;
        RECT 103.075 91.920 103.365 91.965 ;
        RECT 110.560 91.920 110.880 91.980 ;
        RECT 28.615 91.780 40.870 91.920 ;
        RECT 28.615 91.735 29.000 91.780 ;
        RECT 28.680 91.720 29.000 91.735 ;
        RECT 32.015 91.580 32.305 91.625 ;
        RECT 32.450 91.580 32.590 91.780 ;
        RECT 35.415 91.735 35.705 91.780 ;
        RECT 38.890 91.625 39.030 91.780 ;
        RECT 28.310 91.440 30.290 91.580 ;
        RECT 27.085 91.315 27.375 91.360 ;
        RECT 28.310 91.315 28.450 91.440 ;
        RECT 27.085 91.175 28.450 91.315 ;
        RECT 30.150 91.315 30.290 91.440 ;
        RECT 32.015 91.440 32.590 91.580 ;
        RECT 32.015 91.395 32.305 91.440 ;
        RECT 38.815 91.395 39.105 91.625 ;
        RECT 40.730 91.580 40.870 91.780 ;
        RECT 55.335 91.780 113.150 91.920 ;
        RECT 41.875 91.580 42.165 91.625 ;
        RECT 44.255 91.580 44.545 91.625 ;
        RECT 55.335 91.580 55.475 91.780 ;
        RECT 40.730 91.440 55.475 91.580 ;
        RECT 41.875 91.395 42.165 91.440 ;
        RECT 44.255 91.395 44.545 91.440 ;
        RECT 30.520 91.360 30.840 91.375 ;
        RECT 30.485 91.315 30.840 91.360 ;
        RECT 33.375 91.315 33.665 91.360 ;
        RECT 36.775 91.315 37.065 91.360 ;
        RECT 40.175 91.315 40.465 91.360 ;
        RECT 30.150 91.240 30.840 91.315 ;
        RECT 33.370 91.240 38.570 91.315 ;
        RECT 39.350 91.240 40.465 91.315 ;
        RECT 30.150 91.175 40.465 91.240 ;
        RECT 27.085 91.130 27.375 91.175 ;
        RECT 30.485 91.130 33.665 91.175 ;
        RECT 36.775 91.130 37.065 91.175 ;
        RECT 30.520 91.115 33.510 91.130 ;
        RECT 30.610 91.100 33.510 91.115 ;
        RECT 38.430 91.100 39.490 91.175 ;
        RECT 40.175 91.130 40.465 91.175 ;
        RECT 27.760 90.900 28.080 90.960 ;
        RECT 29.125 90.900 29.415 90.945 ;
        RECT 27.760 90.760 29.415 90.900 ;
        RECT 27.760 90.700 28.080 90.760 ;
        RECT 29.125 90.715 29.415 90.760 ;
        RECT 33.740 90.900 34.060 90.960 ;
        RECT 35.955 90.900 36.185 90.975 ;
        RECT 33.740 90.760 36.185 90.900 ;
        RECT 33.740 90.700 34.060 90.760 ;
        RECT 35.955 90.685 36.185 90.760 ;
        RECT 37.880 90.900 38.200 90.960 ;
        RECT 39.155 90.900 39.445 90.945 ;
        RECT 37.880 90.760 39.445 90.900 ;
        RECT 37.880 90.700 38.200 90.760 ;
        RECT 39.155 90.715 39.445 90.760 ;
        RECT 26.130 89.920 42.930 90.245 ;
        RECT 49.240 89.920 50.140 91.440 ;
        RECT 54.240 89.920 55.140 91.440 ;
        RECT 59.240 89.920 60.140 91.780 ;
        RECT 64.240 89.920 65.140 91.780 ;
        RECT 69.240 89.920 70.140 91.780 ;
        RECT 74.240 89.920 75.140 91.780 ;
        RECT 79.240 89.920 80.140 91.780 ;
        RECT 84.240 89.920 85.140 91.780 ;
        RECT 89.240 89.920 90.140 91.780 ;
        RECT 94.240 89.920 95.140 91.780 ;
        RECT 100.900 91.720 101.220 91.780 ;
        RECT 103.075 91.735 103.365 91.780 ;
        RECT 106.050 91.625 106.190 91.780 ;
        RECT 109.610 91.625 109.750 91.780 ;
        RECT 110.560 91.720 110.880 91.780 ;
        RECT 113.010 91.625 113.150 91.780 ;
        RECT 106.050 91.440 106.425 91.625 ;
        RECT 106.135 91.395 106.425 91.440 ;
        RECT 109.535 91.395 109.825 91.625 ;
        RECT 112.935 91.395 113.225 91.625 ;
        RECT 113.615 91.580 113.905 91.625 ;
        RECT 116.540 91.580 116.860 91.640 ;
        RECT 113.615 91.440 116.860 91.580 ;
        RECT 113.615 91.395 113.905 91.440 ;
        RECT 116.540 91.380 116.860 91.440 ;
        RECT 100.440 91.315 100.760 91.375 ;
        RECT 101.035 91.315 101.325 91.360 ;
        RECT 104.435 91.315 104.725 91.360 ;
        RECT 100.440 91.240 104.725 91.315 ;
        RECT 107.835 91.240 108.125 91.360 ;
        RECT 111.065 91.240 111.355 91.360 ;
        RECT 100.440 91.175 111.355 91.240 ;
        RECT 100.440 91.115 100.760 91.175 ;
        RECT 101.035 91.130 101.325 91.175 ;
        RECT 104.435 91.130 111.355 91.175 ;
        RECT 104.510 91.100 111.280 91.130 ;
        RECT 106.815 90.900 107.105 90.945 ;
        RECT 108.720 90.900 109.040 90.960 ;
        RECT 106.815 90.760 109.040 90.900 ;
        RECT 106.815 90.715 107.105 90.760 ;
        RECT 108.720 90.700 109.040 90.760 ;
        RECT 110.215 90.900 110.505 90.945 ;
        RECT 114.700 90.900 115.020 90.960 ;
        RECT 110.215 90.760 115.020 90.900 ;
        RECT 110.215 90.715 110.505 90.760 ;
        RECT 114.700 90.700 115.020 90.760 ;
        RECT 100.530 89.920 113.970 90.245 ;
        RECT 24.690 89.320 113.970 89.920 ;
      LAYER met2 ;
        RECT 21.800 180.915 22.080 181.285 ;
        RECT 21.870 172.930 22.010 180.915 ;
        RECT 25.480 179.555 25.760 179.925 ;
        RECT 25.550 174.290 25.690 179.555 ;
        RECT 25.490 173.970 25.750 174.290 ;
        RECT 25.030 173.290 25.290 173.610 ;
        RECT 24.570 173.125 24.830 173.270 ;
        RECT 21.810 172.610 22.070 172.930 ;
        RECT 24.560 172.755 24.840 173.125 ;
        RECT 25.090 170.405 25.230 173.290 ;
        RECT 25.020 170.035 25.300 170.405 ;
        RECT 25.550 169.870 25.690 173.970 ;
        RECT 25.940 171.395 26.220 171.765 ;
        RECT 26.010 170.210 26.150 171.395 ;
        RECT 25.950 169.890 26.210 170.210 ;
        RECT 25.490 169.550 25.750 169.870 ;
        RECT 25.940 168.675 26.220 169.045 ;
        RECT 26.010 168.510 26.150 168.675 ;
        RECT 25.950 168.190 26.210 168.510 ;
        RECT 23.190 167.850 23.450 168.170 ;
        RECT 23.250 167.685 23.390 167.850 ;
        RECT 23.180 167.315 23.460 167.685 ;
        RECT 25.950 165.130 26.210 165.450 ;
        RECT 25.030 163.770 25.290 164.090 ;
        RECT 25.090 160.885 25.230 163.770 ;
        RECT 26.010 163.605 26.150 165.130 ;
        RECT 25.940 163.235 26.220 163.605 ;
        RECT 25.480 161.875 25.760 162.245 ;
        RECT 25.020 160.515 25.300 160.885 ;
        RECT 25.550 160.690 25.690 161.875 ;
        RECT 25.490 160.370 25.750 160.690 ;
        RECT 25.950 160.030 26.210 160.350 ;
        RECT 25.030 159.690 25.290 160.010 ;
        RECT 25.090 158.165 25.230 159.690 ;
        RECT 26.010 159.525 26.150 160.030 ;
        RECT 25.940 159.155 26.220 159.525 ;
        RECT 25.020 157.795 25.300 158.165 ;
        RECT 25.950 156.970 26.210 157.290 ;
        RECT 21.810 155.610 22.070 155.930 ;
        RECT 21.870 151.365 22.010 155.610 ;
        RECT 26.010 155.445 26.150 156.970 ;
        RECT 25.940 155.075 26.220 155.445 ;
        RECT 25.940 153.715 26.220 154.085 ;
        RECT 26.010 152.870 26.150 153.715 ;
        RECT 25.950 152.550 26.210 152.870 ;
        RECT 24.110 151.530 24.370 151.850 ;
        RECT 21.800 150.995 22.080 151.365 ;
        RECT 24.170 150.005 24.310 151.530 ;
        RECT 24.100 149.635 24.380 150.005 ;
        RECT 23.650 148.645 23.910 148.790 ;
        RECT 23.640 148.275 23.920 148.645 ;
        RECT 25.490 147.450 25.750 147.770 ;
        RECT 25.550 145.925 25.690 147.450 ;
        RECT 25.480 145.555 25.760 145.925 ;
        RECT 25.940 144.195 26.220 144.565 ;
        RECT 26.010 144.030 26.150 144.195 ;
        RECT 25.950 143.710 26.210 144.030 ;
        RECT 25.030 143.370 25.290 143.690 ;
        RECT 25.090 143.205 25.230 143.370 ;
        RECT 25.020 142.835 25.300 143.205 ;
        RECT 25.940 141.475 26.220 141.845 ;
        RECT 25.950 141.330 26.210 141.475 ;
        RECT 25.950 140.485 26.210 140.630 ;
        RECT 25.940 140.115 26.220 140.485 ;
        RECT 25.950 139.290 26.210 139.610 ;
        RECT 26.010 139.125 26.150 139.290 ;
        RECT 25.940 138.755 26.220 139.125 ;
        RECT 25.940 137.395 26.220 137.765 ;
        RECT 25.950 137.250 26.210 137.395 ;
        RECT 25.940 136.035 26.220 136.405 ;
        RECT 26.010 135.870 26.150 136.035 ;
        RECT 25.950 135.550 26.210 135.870 ;
        RECT 25.480 134.675 25.760 135.045 ;
        RECT 25.020 131.955 25.300 132.325 ;
        RECT 25.090 129.410 25.230 131.955 ;
        RECT 25.550 131.450 25.690 134.675 ;
        RECT 25.940 133.315 26.220 133.685 ;
        RECT 26.010 131.790 26.150 133.315 ;
        RECT 25.950 131.470 26.210 131.790 ;
        RECT 25.490 131.130 25.750 131.450 ;
        RECT 25.030 129.090 25.290 129.410 ;
        RECT 25.950 128.245 26.210 128.390 ;
        RECT 25.940 127.875 26.220 128.245 ;
        RECT 25.480 125.155 25.760 125.525 ;
        RECT 25.550 124.650 25.690 125.155 ;
        RECT 25.490 124.330 25.750 124.650 ;
        RECT 25.940 123.795 26.220 124.165 ;
        RECT 26.010 123.290 26.150 123.795 ;
        RECT 25.950 122.970 26.210 123.290 ;
        RECT 25.940 122.435 26.220 122.805 ;
        RECT 26.010 121.250 26.150 122.435 ;
        RECT 25.950 120.930 26.210 121.250 ;
        RECT 25.940 118.355 26.220 118.725 ;
        RECT 25.480 116.995 25.760 117.365 ;
        RECT 26.010 117.170 26.150 118.355 ;
        RECT 24.560 115.635 24.840 116.005 ;
        RECT 24.630 111.390 24.770 115.635 ;
        RECT 25.020 112.915 25.300 113.285 ;
        RECT 25.550 113.090 25.690 116.995 ;
        RECT 25.950 116.850 26.210 117.170 ;
        RECT 25.950 115.830 26.210 116.150 ;
        RECT 26.010 114.645 26.150 115.830 ;
        RECT 25.940 114.275 26.220 114.645 ;
        RECT 24.570 111.070 24.830 111.390 ;
        RECT 24.560 110.195 24.840 110.565 ;
        RECT 24.630 102.890 24.770 110.195 ;
        RECT 25.090 109.010 25.230 112.915 ;
        RECT 25.490 112.770 25.750 113.090 ;
        RECT 25.940 111.555 26.220 111.925 ;
        RECT 25.950 111.410 26.210 111.555 ;
        RECT 25.030 108.690 25.290 109.010 ;
        RECT 25.950 108.010 26.210 108.330 ;
        RECT 26.010 106.485 26.150 108.010 ;
        RECT 25.940 106.115 26.220 106.485 ;
        RECT 25.940 104.755 26.220 105.125 ;
        RECT 25.480 103.395 25.760 103.765 ;
        RECT 24.570 102.570 24.830 102.890 ;
        RECT 25.550 100.850 25.690 103.395 ;
        RECT 26.010 103.230 26.150 104.755 ;
        RECT 25.950 102.910 26.210 103.230 ;
        RECT 25.490 100.530 25.750 100.850 ;
        RECT 25.480 99.315 25.760 99.685 ;
        RECT 25.020 96.595 25.300 96.965 ;
        RECT 25.090 94.730 25.230 96.595 ;
        RECT 25.550 95.070 25.690 99.315 ;
        RECT 25.940 97.955 26.220 98.325 ;
        RECT 26.010 95.410 26.150 97.955 ;
        RECT 25.950 95.090 26.210 95.410 ;
        RECT 25.490 94.750 25.750 95.070 ;
        RECT 25.030 94.410 25.290 94.730 ;
        RECT 25.950 92.370 26.210 92.690 ;
        RECT 26.010 91.525 26.150 92.370 ;
        RECT 25.940 91.155 26.220 91.525 ;
        RECT 26.740 81.020 27.640 183.690 ;
        RECT 28.710 172.485 28.970 172.805 ;
        RECT 28.250 171.930 28.510 172.250 ;
        RECT 28.310 168.850 28.450 171.930 ;
        RECT 28.770 169.530 28.910 172.485 ;
        RECT 28.710 169.210 28.970 169.530 ;
        RECT 28.250 168.530 28.510 168.850 ;
        RECT 28.310 165.110 28.450 168.530 ;
        RECT 28.250 164.790 28.510 165.110 ;
        RECT 28.310 161.710 28.450 164.790 ;
        RECT 28.250 161.390 28.510 161.710 ;
        RECT 28.310 156.950 28.450 161.390 ;
        RECT 28.250 156.630 28.510 156.950 ;
        RECT 28.310 153.890 28.450 156.630 ;
        RECT 28.710 156.205 28.970 156.525 ;
        RECT 28.250 153.570 28.510 153.890 ;
        RECT 28.770 153.270 28.910 156.205 ;
        RECT 28.710 152.950 28.970 153.270 ;
        RECT 28.770 148.385 28.910 152.950 ;
        RECT 28.710 148.065 28.970 148.385 ;
        RECT 28.770 145.130 28.910 148.065 ;
        RECT 28.710 144.810 28.970 145.130 ;
        RECT 28.250 120.420 28.510 120.740 ;
        RECT 28.310 115.810 28.450 120.420 ;
        RECT 28.250 115.490 28.510 115.810 ;
        RECT 28.310 112.580 28.450 115.490 ;
        RECT 28.710 115.150 28.970 115.470 ;
        RECT 28.250 112.260 28.510 112.580 ;
        RECT 28.310 107.650 28.450 112.260 ;
        RECT 28.770 112.070 28.910 115.150 ;
        RECT 28.710 111.750 28.970 112.070 ;
        RECT 28.250 107.330 28.510 107.650 ;
        RECT 28.310 104.420 28.450 107.330 ;
        RECT 28.770 107.310 28.910 111.750 ;
        RECT 28.710 106.990 28.970 107.310 ;
        RECT 28.250 104.100 28.510 104.420 ;
        RECT 28.310 99.545 28.450 104.100 ;
        RECT 28.770 103.910 28.910 106.990 ;
        RECT 28.710 103.590 28.970 103.910 ;
        RECT 28.250 99.225 28.510 99.545 ;
        RECT 28.770 99.490 28.910 103.590 ;
        RECT 28.310 96.260 28.450 99.225 ;
        RECT 28.710 99.170 28.970 99.490 ;
        RECT 28.250 95.940 28.510 96.260 ;
        RECT 28.770 95.750 28.910 99.170 ;
        RECT 28.710 95.430 28.970 95.750 ;
        RECT 28.770 92.010 28.910 95.430 ;
        RECT 28.710 91.690 28.970 92.010 ;
        RECT 27.790 90.670 28.050 90.990 ;
        RECT 27.850 88.805 27.990 90.670 ;
        RECT 27.780 88.435 28.060 88.805 ;
        RECT 29.240 77.820 30.140 186.890 ;
        RECT 31.010 152.550 31.270 152.870 ;
        RECT 31.070 149.810 31.210 152.550 ;
        RECT 31.010 149.490 31.270 149.810 ;
        RECT 31.070 148.450 31.210 149.490 ;
        RECT 31.010 148.130 31.270 148.450 ;
        RECT 31.070 144.710 31.210 148.130 ;
        RECT 31.010 144.390 31.270 144.710 ;
        RECT 30.550 95.940 30.810 96.260 ;
        RECT 30.610 91.405 30.750 95.940 ;
        RECT 30.550 91.085 30.810 91.405 ;
        RECT 31.740 81.020 32.640 183.690 ;
        RECT 33.760 152.355 34.040 152.725 ;
        RECT 33.830 152.190 33.970 152.355 ;
        RECT 33.770 151.870 34.030 152.190 ;
        RECT 33.770 147.450 34.030 147.770 ;
        RECT 33.830 147.285 33.970 147.450 ;
        RECT 33.760 146.915 34.040 147.285 ;
        RECT 33.770 144.390 34.030 144.710 ;
        RECT 33.310 139.690 33.570 139.950 ;
        RECT 33.830 139.690 33.970 144.390 ;
        RECT 33.310 139.630 33.970 139.690 ;
        RECT 33.370 139.550 33.970 139.630 ;
        RECT 33.830 136.890 33.970 139.550 ;
        RECT 33.770 136.570 34.030 136.890 ;
        RECT 33.830 133.150 33.970 136.570 ;
        RECT 33.770 132.830 34.030 133.150 ;
        RECT 33.770 132.150 34.030 132.470 ;
        RECT 33.830 128.850 33.970 132.150 ;
        RECT 33.770 128.530 34.030 128.850 ;
        RECT 33.770 127.050 34.030 127.370 ;
        RECT 33.830 126.885 33.970 127.050 ;
        RECT 33.760 126.515 34.040 126.885 ;
        RECT 33.770 120.085 34.030 120.230 ;
        RECT 33.760 119.715 34.040 120.085 ;
        RECT 33.770 99.225 34.030 99.545 ;
        RECT 33.830 96.430 33.970 99.225 ;
        RECT 33.770 96.110 34.030 96.430 ;
        RECT 33.770 90.670 34.030 90.990 ;
        RECT 33.830 90.165 33.970 90.670 ;
        RECT 33.760 89.795 34.040 90.165 ;
        RECT 34.240 77.820 35.140 186.890 ;
        RECT 35.600 175.475 35.880 175.845 ;
        RECT 35.670 172.930 35.810 175.475 ;
        RECT 35.610 172.610 35.870 172.930 ;
        RECT 35.600 164.595 35.880 164.965 ;
        RECT 35.610 164.450 35.870 164.595 ;
        RECT 35.610 131.130 35.870 131.450 ;
        RECT 35.670 130.965 35.810 131.130 ;
        RECT 35.600 130.595 35.880 130.965 ;
        RECT 36.060 129.235 36.340 129.605 ;
        RECT 36.070 129.090 36.330 129.235 ;
        RECT 35.610 127.730 35.870 128.050 ;
        RECT 35.670 124.310 35.810 127.730 ;
        RECT 35.610 123.990 35.870 124.310 ;
        RECT 35.670 121.250 35.810 123.990 ;
        RECT 35.610 120.930 35.870 121.250 ;
        RECT 36.060 121.075 36.340 121.445 ;
        RECT 36.070 120.930 36.330 121.075 ;
        RECT 35.670 119.890 35.810 120.930 ;
        RECT 35.610 119.570 35.870 119.890 ;
        RECT 36.060 108.835 36.340 109.205 ;
        RECT 36.070 108.690 36.330 108.835 ;
        RECT 35.610 107.845 35.870 107.990 ;
        RECT 35.600 107.475 35.880 107.845 ;
        RECT 35.610 102.570 35.870 102.890 ;
        RECT 35.670 102.405 35.810 102.570 ;
        RECT 35.600 102.035 35.880 102.405 ;
        RECT 36.060 100.675 36.340 101.045 ;
        RECT 36.070 100.530 36.330 100.675 ;
        RECT 35.610 99.170 35.870 99.490 ;
        RECT 35.670 96.090 35.810 99.170 ;
        RECT 35.610 95.770 35.870 96.090 ;
        RECT 35.610 94.750 35.870 95.070 ;
        RECT 35.670 94.245 35.810 94.750 ;
        RECT 35.600 93.875 35.880 94.245 ;
        RECT 36.740 81.020 37.640 183.690 ;
        RECT 38.830 172.950 39.090 173.270 ;
        RECT 38.890 169.870 39.030 172.950 ;
        RECT 38.830 169.550 39.090 169.870 ;
        RECT 38.820 165.955 39.100 166.325 ;
        RECT 38.830 165.810 39.090 165.955 ;
        RECT 38.820 156.435 39.100 156.805 ;
        RECT 38.830 156.290 39.090 156.435 ;
        RECT 37.910 90.670 38.170 90.990 ;
        RECT 37.970 87.445 38.110 90.670 ;
        RECT 37.900 87.075 38.180 87.445 ;
        RECT 39.240 77.820 40.140 186.890 ;
        RECT 41.120 174.115 41.400 174.485 ;
        RECT 41.190 172.930 41.330 174.115 ;
        RECT 41.130 172.610 41.390 172.930 ;
        RECT 40.670 169.550 40.930 169.870 ;
        RECT 40.730 161.370 40.870 169.550 ;
        RECT 40.670 161.050 40.930 161.370 ;
        RECT 41.120 95.235 41.400 95.605 ;
        RECT 41.130 95.090 41.390 95.235 ;
        RECT 41.120 92.515 41.400 92.885 ;
        RECT 41.130 92.370 41.390 92.515 ;
        RECT 41.740 81.020 42.640 183.690 ;
        RECT 44.240 77.820 45.140 186.890 ;
        RECT 45.730 161.050 45.990 161.370 ;
        RECT 45.790 160.010 45.930 161.050 ;
        RECT 45.730 159.690 45.990 160.010 ;
        RECT 45.790 156.610 45.930 159.690 ;
        RECT 45.730 156.290 45.990 156.610 ;
        RECT 46.740 81.020 47.640 183.690 ;
        RECT 48.490 169.210 48.750 169.530 ;
        RECT 48.550 166.130 48.690 169.210 ;
        RECT 48.490 165.810 48.750 166.130 ;
        RECT 49.240 77.820 50.140 186.890 ;
        RECT 50.790 171.930 51.050 172.250 ;
        RECT 50.850 169.870 50.990 171.930 ;
        RECT 50.790 169.550 51.050 169.870 ;
        RECT 51.250 164.450 51.510 164.770 ;
        RECT 51.310 162.050 51.450 164.450 ;
        RECT 51.250 161.730 51.510 162.050 ;
        RECT 51.740 81.020 52.640 183.690 ;
        RECT 53.550 167.850 53.810 168.170 ;
        RECT 53.610 164.770 53.750 167.850 ;
        RECT 53.550 164.450 53.810 164.770 ;
        RECT 53.550 155.610 53.810 155.930 ;
        RECT 53.610 153.210 53.750 155.610 ;
        RECT 53.550 152.890 53.810 153.210 ;
        RECT 54.240 77.820 55.140 186.890 ;
        RECT 55.850 164.450 56.110 164.770 ;
        RECT 55.910 161.370 56.050 164.450 ;
        RECT 55.850 161.050 56.110 161.370 ;
        RECT 56.740 81.020 57.640 183.690 ;
        RECT 57.935 153.300 58.630 153.730 ;
        RECT 58.360 97.230 58.630 153.300 ;
        RECT 58.260 96.905 58.735 97.230 ;
        RECT 59.240 77.820 60.140 186.890 ;
        RECT 60.910 153.570 61.170 153.890 ;
        RECT 60.970 148.450 61.110 153.570 ;
        RECT 60.910 148.130 61.170 148.450 ;
        RECT 61.740 81.020 62.640 183.690 ;
        RECT 63.210 164.450 63.470 164.770 ;
        RECT 63.270 157.970 63.410 164.450 ;
        RECT 63.210 157.650 63.470 157.970 ;
        RECT 63.270 156.610 63.410 157.650 ;
        RECT 63.210 156.290 63.470 156.610 ;
        RECT 63.270 153.890 63.410 156.290 ;
        RECT 63.210 153.570 63.470 153.890 ;
        RECT 64.240 77.820 65.140 186.890 ;
        RECT 66.740 81.020 67.640 183.690 ;
        RECT 69.240 77.820 70.140 186.890 ;
        RECT 71.740 81.020 72.640 183.690 ;
        RECT 74.240 77.820 75.140 186.890 ;
        RECT 76.740 81.020 77.640 183.690 ;
        RECT 79.240 77.820 80.140 186.890 ;
        RECT 81.740 81.020 82.640 183.690 ;
        RECT 84.240 77.820 85.140 186.890 ;
        RECT 86.740 81.020 87.640 183.690 ;
        RECT 89.240 77.820 90.140 186.890 ;
        RECT 91.740 81.020 92.640 183.690 ;
        RECT 94.240 77.820 95.140 186.890 ;
        RECT 96.740 81.020 97.640 183.690 ;
        RECT 98.630 103.930 98.890 104.250 ;
        RECT 98.690 99.545 98.830 103.930 ;
        RECT 98.630 99.225 98.890 99.545 ;
        RECT 98.690 96.770 98.830 99.225 ;
        RECT 98.630 96.450 98.890 96.770 ;
        RECT 99.240 77.820 100.140 186.890 ;
        RECT 100.930 169.210 101.190 169.530 ;
        RECT 100.990 165.110 101.130 169.210 ;
        RECT 100.930 164.790 101.190 165.110 ;
        RECT 100.930 98.830 101.190 99.150 ;
        RECT 100.990 98.325 101.130 98.830 ;
        RECT 100.920 97.955 101.200 98.325 ;
        RECT 100.470 96.450 100.730 96.770 ;
        RECT 100.530 91.405 100.670 96.450 ;
        RECT 100.930 95.430 101.190 95.750 ;
        RECT 100.990 92.010 101.130 95.430 ;
        RECT 100.930 91.690 101.190 92.010 ;
        RECT 100.470 91.085 100.730 91.405 ;
        RECT 101.740 81.020 102.640 183.690 ;
        RECT 103.690 172.950 103.950 173.270 ;
        RECT 103.230 171.930 103.490 172.250 ;
        RECT 103.290 169.870 103.430 171.930 ;
        RECT 103.230 169.550 103.490 169.870 ;
        RECT 103.750 169.530 103.890 172.950 ;
        RECT 103.690 169.210 103.950 169.530 ;
        RECT 103.220 165.955 103.500 166.325 ;
        RECT 103.230 165.810 103.490 165.955 ;
        RECT 103.750 164.770 103.890 169.210 ;
        RECT 103.690 164.450 103.950 164.770 ;
        RECT 103.750 164.090 103.890 164.450 ;
        RECT 103.690 163.770 103.950 164.090 ;
        RECT 103.750 161.030 103.890 163.770 ;
        RECT 103.690 160.710 103.950 161.030 ;
        RECT 103.220 149.635 103.500 150.005 ;
        RECT 103.230 149.490 103.490 149.635 ;
        RECT 103.690 139.970 103.950 140.290 ;
        RECT 103.750 136.990 103.890 139.970 ;
        RECT 103.690 136.670 103.950 136.990 ;
        RECT 103.230 135.890 103.490 136.210 ;
        RECT 103.290 132.130 103.430 135.890 ;
        RECT 103.750 132.810 103.890 136.670 ;
        RECT 103.690 132.490 103.950 132.810 ;
        RECT 103.230 131.810 103.490 132.130 ;
        RECT 103.290 128.730 103.430 131.810 ;
        RECT 103.230 128.410 103.490 128.730 ;
        RECT 103.290 123.630 103.430 128.410 ;
        RECT 103.230 123.310 103.490 123.630 ;
        RECT 103.290 119.890 103.430 123.310 ;
        RECT 103.680 121.075 103.960 121.445 ;
        RECT 103.690 120.930 103.950 121.075 ;
        RECT 103.230 119.570 103.490 119.890 ;
        RECT 103.290 116.150 103.430 119.570 ;
        RECT 103.230 115.830 103.490 116.150 ;
        RECT 103.290 112.070 103.430 115.830 ;
        RECT 103.230 111.750 103.490 112.070 ;
        RECT 103.290 107.220 103.430 111.750 ;
        RECT 103.680 108.835 103.960 109.205 ;
        RECT 103.690 108.690 103.950 108.835 ;
        RECT 103.690 107.220 103.950 107.310 ;
        RECT 103.290 107.080 103.950 107.220 ;
        RECT 103.690 106.990 103.950 107.080 ;
        RECT 103.750 104.250 103.890 106.990 ;
        RECT 103.690 103.930 103.950 104.250 ;
        RECT 103.750 100.170 103.890 103.930 ;
        RECT 103.690 99.850 103.950 100.170 ;
        RECT 103.680 92.515 103.960 92.885 ;
        RECT 103.690 92.370 103.950 92.515 ;
        RECT 104.240 77.820 105.140 186.890 ;
        RECT 105.530 171.930 105.790 172.250 ;
        RECT 105.590 171.765 105.730 171.930 ;
        RECT 105.520 171.395 105.800 171.765 ;
        RECT 105.520 170.035 105.800 170.405 ;
        RECT 105.530 169.890 105.790 170.035 ;
        RECT 105.530 163.770 105.790 164.090 ;
        RECT 105.990 163.770 106.250 164.090 ;
        RECT 105.590 163.605 105.730 163.770 ;
        RECT 105.520 163.235 105.800 163.605 ;
        RECT 106.050 161.370 106.190 163.770 ;
        RECT 105.990 161.050 106.250 161.370 ;
        RECT 106.050 156.525 106.190 161.050 ;
        RECT 105.990 156.205 106.250 156.525 ;
        RECT 105.990 155.610 106.250 155.930 ;
        RECT 106.050 152.870 106.190 155.610 ;
        RECT 105.990 152.550 106.250 152.870 ;
        RECT 106.050 148.790 106.190 152.550 ;
        RECT 105.990 148.470 106.250 148.790 ;
        RECT 105.530 147.450 105.790 147.770 ;
        RECT 105.590 147.285 105.730 147.450 ;
        RECT 105.520 146.915 105.800 147.285 ;
        RECT 106.050 145.050 106.190 148.470 ;
        RECT 105.990 144.730 106.250 145.050 ;
        RECT 105.520 136.035 105.800 136.405 ;
        RECT 105.530 135.890 105.790 136.035 ;
        RECT 105.980 133.315 106.260 133.685 ;
        RECT 106.050 131.450 106.190 133.315 ;
        RECT 105.990 131.130 106.250 131.450 ;
        RECT 105.990 128.530 106.250 128.850 ;
        RECT 106.050 128.050 106.190 128.530 ;
        RECT 105.990 127.730 106.250 128.050 ;
        RECT 105.530 127.050 105.790 127.370 ;
        RECT 105.590 126.885 105.730 127.050 ;
        RECT 105.520 126.515 105.800 126.885 ;
        RECT 105.530 124.330 105.790 124.650 ;
        RECT 105.590 124.165 105.730 124.330 ;
        RECT 105.520 123.795 105.800 124.165 ;
        RECT 106.050 123.970 106.190 127.730 ;
        RECT 105.990 123.650 106.250 123.970 ;
        RECT 105.530 114.810 105.790 115.130 ;
        RECT 105.590 114.645 105.730 114.810 ;
        RECT 105.520 114.275 105.800 114.645 ;
        RECT 105.530 110.730 105.790 111.050 ;
        RECT 105.590 110.565 105.730 110.730 ;
        RECT 105.520 110.195 105.800 110.565 ;
        RECT 105.530 102.570 105.790 102.890 ;
        RECT 105.590 102.405 105.730 102.570 ;
        RECT 105.520 102.035 105.800 102.405 ;
        RECT 105.990 99.850 106.250 100.170 ;
        RECT 105.520 99.315 105.800 99.685 ;
        RECT 105.590 99.150 105.730 99.315 ;
        RECT 105.530 98.830 105.790 99.150 ;
        RECT 106.050 96.090 106.190 99.850 ;
        RECT 105.990 95.770 106.250 96.090 ;
        RECT 106.740 81.020 107.640 183.690 ;
        RECT 107.820 161.875 108.100 162.245 ;
        RECT 107.890 160.690 108.030 161.875 ;
        RECT 107.830 160.370 108.090 160.690 ;
        RECT 108.290 156.205 108.550 156.525 ;
        RECT 108.350 156.010 108.490 156.205 ;
        RECT 108.350 155.870 108.950 156.010 ;
        RECT 108.810 153.270 108.950 155.870 ;
        RECT 108.750 152.950 109.010 153.270 ;
        RECT 108.810 148.385 108.950 152.950 ;
        RECT 108.750 148.065 109.010 148.385 ;
        RECT 108.810 145.130 108.950 148.065 ;
        RECT 108.750 144.810 109.010 145.130 ;
        RECT 108.810 140.290 108.950 144.810 ;
        RECT 108.750 139.970 109.010 140.290 ;
        RECT 108.750 131.810 109.010 132.130 ;
        RECT 107.820 129.235 108.100 129.605 ;
        RECT 107.830 129.090 108.090 129.235 ;
        RECT 108.810 128.850 108.950 131.810 ;
        RECT 108.750 128.530 109.010 128.850 ;
        RECT 107.820 116.995 108.100 117.365 ;
        RECT 107.830 116.850 108.090 116.995 ;
        RECT 107.820 112.915 108.100 113.285 ;
        RECT 107.830 112.770 108.090 112.915 ;
        RECT 107.820 104.755 108.100 105.125 ;
        RECT 107.890 103.230 108.030 104.755 ;
        RECT 107.830 102.910 108.090 103.230 ;
        RECT 107.820 100.675 108.100 101.045 ;
        RECT 107.830 100.530 108.090 100.675 ;
        RECT 107.830 99.225 108.090 99.545 ;
        RECT 107.890 96.430 108.030 99.225 ;
        RECT 107.830 96.110 108.090 96.430 ;
        RECT 108.750 90.670 109.010 90.990 ;
        RECT 108.810 90.165 108.950 90.670 ;
        RECT 108.740 89.795 109.020 90.165 ;
        RECT 109.240 77.820 110.140 186.890 ;
        RECT 110.580 174.115 110.860 174.485 ;
        RECT 110.590 173.970 110.850 174.115 ;
        RECT 110.590 164.450 110.850 164.770 ;
        RECT 110.650 161.370 110.790 164.450 ;
        RECT 110.590 161.050 110.850 161.370 ;
        RECT 110.650 156.690 110.790 161.050 ;
        RECT 110.650 156.610 111.250 156.690 ;
        RECT 110.650 156.550 111.310 156.610 ;
        RECT 110.650 152.870 110.790 156.550 ;
        RECT 111.050 156.290 111.310 156.550 ;
        RECT 111.050 155.610 111.310 155.930 ;
        RECT 111.110 155.445 111.250 155.610 ;
        RECT 111.040 155.075 111.320 155.445 ;
        RECT 110.590 152.550 110.850 152.870 ;
        RECT 110.590 148.130 110.850 148.450 ;
        RECT 110.650 145.050 110.790 148.130 ;
        RECT 110.590 144.730 110.850 145.050 ;
        RECT 110.650 140.970 110.790 144.730 ;
        RECT 110.590 140.650 110.850 140.970 ;
        RECT 110.650 140.290 110.790 140.650 ;
        RECT 110.590 139.970 110.850 140.290 ;
        RECT 110.650 136.550 110.790 139.970 ;
        RECT 110.590 136.230 110.850 136.550 ;
        RECT 110.650 132.130 110.790 136.230 ;
        RECT 111.050 135.210 111.310 135.530 ;
        RECT 111.110 135.045 111.250 135.210 ;
        RECT 111.040 134.675 111.320 135.045 ;
        RECT 110.590 131.810 110.850 132.130 ;
        RECT 110.650 128.730 110.790 131.810 ;
        RECT 110.590 128.410 110.850 128.730 ;
        RECT 110.590 122.970 110.850 123.290 ;
        RECT 110.650 122.805 110.790 122.970 ;
        RECT 110.580 122.435 110.860 122.805 ;
        RECT 110.580 111.555 110.860 111.925 ;
        RECT 110.650 109.010 110.790 111.555 ;
        RECT 110.590 108.690 110.850 109.010 ;
        RECT 110.580 103.395 110.860 103.765 ;
        RECT 110.650 100.850 110.790 103.395 ;
        RECT 110.590 100.530 110.850 100.850 ;
        RECT 110.590 95.770 110.850 96.090 ;
        RECT 110.650 92.010 110.790 95.770 ;
        RECT 110.590 91.690 110.850 92.010 ;
        RECT 111.740 81.020 112.640 183.690 ;
        RECT 115.640 172.755 115.920 173.125 ;
        RECT 115.650 172.610 115.910 172.755 ;
        RECT 113.340 168.675 113.620 169.045 ;
        RECT 113.350 168.530 113.610 168.675 ;
        RECT 115.190 167.850 115.450 168.170 ;
        RECT 115.250 167.685 115.390 167.850 ;
        RECT 115.180 167.315 115.460 167.685 ;
        RECT 113.350 164.965 113.610 165.110 ;
        RECT 113.340 164.595 113.620 164.965 ;
        RECT 115.190 163.770 115.450 164.090 ;
        RECT 115.250 160.885 115.390 163.770 ;
        RECT 115.180 160.515 115.460 160.885 ;
        RECT 112.890 159.690 113.150 160.010 ;
        RECT 116.570 159.690 116.830 160.010 ;
        RECT 112.950 158.165 113.090 159.690 ;
        RECT 116.630 159.525 116.770 159.690 ;
        RECT 116.560 159.155 116.840 159.525 ;
        RECT 112.880 157.795 113.160 158.165 ;
        RECT 112.890 156.805 113.150 156.950 ;
        RECT 112.880 156.435 113.160 156.805 ;
        RECT 116.110 155.610 116.370 155.930 ;
        RECT 116.170 154.085 116.310 155.610 ;
        RECT 116.100 153.715 116.380 154.085 ;
        RECT 113.340 152.355 113.620 152.725 ;
        RECT 113.350 152.210 113.610 152.355 ;
        RECT 115.190 151.530 115.450 151.850 ;
        RECT 115.250 151.365 115.390 151.530 ;
        RECT 115.180 150.995 115.460 151.365 ;
        RECT 113.350 148.645 113.610 148.790 ;
        RECT 113.340 148.275 113.620 148.645 ;
        RECT 115.190 147.450 115.450 147.770 ;
        RECT 115.250 145.925 115.390 147.450 ;
        RECT 115.180 145.555 115.460 145.925 ;
        RECT 113.340 144.195 113.620 144.565 ;
        RECT 113.350 144.050 113.610 144.195 ;
        RECT 115.190 143.370 115.450 143.690 ;
        RECT 115.250 143.205 115.390 143.370 ;
        RECT 115.180 142.835 115.460 143.205 ;
        RECT 112.880 141.475 113.160 141.845 ;
        RECT 112.890 141.330 113.150 141.475 ;
        RECT 113.350 140.485 113.610 140.630 ;
        RECT 113.340 140.115 113.620 140.485 ;
        RECT 112.880 138.755 113.160 139.125 ;
        RECT 112.950 137.570 113.090 138.755 ;
        RECT 112.890 137.250 113.150 137.570 ;
        RECT 113.800 137.395 114.080 137.765 ;
        RECT 113.340 131.955 113.620 132.325 ;
        RECT 113.410 131.790 113.550 131.955 ;
        RECT 113.350 131.470 113.610 131.790 ;
        RECT 113.870 131.450 114.010 137.395 ;
        RECT 113.810 131.130 114.070 131.450 ;
        RECT 112.880 130.595 113.160 130.965 ;
        RECT 112.950 129.410 113.090 130.595 ;
        RECT 112.890 129.090 113.150 129.410 ;
        RECT 112.880 127.875 113.160 128.245 ;
        RECT 112.950 124.650 113.090 127.875 ;
        RECT 113.340 125.155 113.620 125.525 ;
        RECT 112.890 124.330 113.150 124.650 ;
        RECT 113.410 121.250 113.550 125.155 ;
        RECT 113.350 120.930 113.610 121.250 ;
        RECT 113.340 119.715 113.620 120.085 ;
        RECT 113.350 119.570 113.610 119.715 ;
        RECT 112.880 118.355 113.160 118.725 ;
        RECT 112.950 117.170 113.090 118.355 ;
        RECT 112.890 116.850 113.150 117.170 ;
        RECT 112.880 115.635 113.160 116.005 ;
        RECT 112.950 113.090 113.090 115.635 ;
        RECT 112.890 112.770 113.150 113.090 ;
        RECT 113.350 108.010 113.610 108.330 ;
        RECT 113.410 107.845 113.550 108.010 ;
        RECT 113.340 107.475 113.620 107.845 ;
        RECT 112.880 106.115 113.160 106.485 ;
        RECT 112.950 103.230 113.090 106.115 ;
        RECT 112.890 102.910 113.150 103.230 ;
        RECT 112.880 96.595 113.160 96.965 ;
        RECT 112.950 95.070 113.090 96.595 ;
        RECT 116.100 95.235 116.380 95.605 ;
        RECT 116.110 95.090 116.370 95.235 ;
        RECT 112.890 94.750 113.150 95.070 ;
        RECT 115.190 94.410 115.450 94.730 ;
        RECT 115.250 94.245 115.390 94.410 ;
        RECT 115.180 93.875 115.460 94.245 ;
        RECT 116.570 91.525 116.830 91.670 ;
        RECT 116.560 91.155 116.840 91.525 ;
        RECT 114.730 90.670 114.990 90.990 ;
        RECT 114.790 88.805 114.930 90.670 ;
        RECT 114.720 88.435 115.000 88.805 ;
      LAYER met3 ;
        RECT 7.020 183.690 8.620 219.420 ;
        RECT 12.890 185.290 125.770 186.890 ;
        RECT 7.020 182.090 122.570 183.690 ;
        RECT 4.000 79.420 6.000 123.760 ;
        RECT 7.020 106.640 8.620 182.090 ;
        RECT 19.390 181.250 19.810 181.335 ;
        RECT 21.775 181.250 22.105 181.265 ;
        RECT 19.390 180.950 22.105 181.250 ;
        RECT 19.390 180.810 19.810 180.950 ;
        RECT 21.775 180.935 22.105 180.950 ;
        RECT 11.760 179.890 12.145 179.935 ;
        RECT 25.455 179.890 25.785 179.905 ;
        RECT 11.760 179.590 25.785 179.890 ;
        RECT 11.760 178.605 12.400 179.590 ;
        RECT 25.455 179.575 25.785 179.590 ;
        RECT 12.100 178.595 12.400 178.605 ;
        RECT 10.185 175.810 10.885 175.875 ;
        RECT 35.575 175.810 35.905 175.825 ;
        RECT 10.185 175.510 35.905 175.810 ;
        RECT 10.185 175.420 10.885 175.510 ;
        RECT 35.575 175.495 35.905 175.510 ;
        RECT 10.355 173.740 10.725 175.420 ;
        RECT 41.095 174.450 41.425 174.465 ;
        RECT 19.410 174.150 41.425 174.450 ;
        RECT 10.200 172.720 11.220 173.740 ;
        RECT 19.410 173.475 20.410 174.150 ;
        RECT 41.095 174.135 41.425 174.150 ;
        RECT 110.555 174.450 110.885 174.465 ;
        RECT 115.410 174.450 119.410 175.475 ;
        RECT 110.555 174.150 119.410 174.450 ;
        RECT 110.555 174.135 110.885 174.150 ;
        RECT 19.410 173.090 23.410 173.475 ;
        RECT 24.535 173.090 24.865 173.105 ;
        RECT 19.410 172.790 24.865 173.090 ;
        RECT 19.410 171.730 23.410 172.790 ;
        RECT 24.535 172.775 24.865 172.790 ;
        RECT 25.915 171.730 26.245 171.745 ;
        RECT 105.495 171.730 105.825 171.745 ;
        RECT 115.410 171.730 119.410 174.150 ;
        RECT 19.410 171.280 119.410 171.730 ;
        RECT 19.410 170.370 23.410 171.280 ;
        RECT 24.995 170.370 25.325 170.385 ;
        RECT 19.410 170.070 25.325 170.370 ;
        RECT 19.410 169.230 23.410 170.070 ;
        RECT 24.995 170.055 25.325 170.070 ;
        RECT 105.495 170.370 105.825 170.385 ;
        RECT 115.410 170.370 119.410 171.280 ;
        RECT 105.495 170.070 119.410 170.370 ;
        RECT 105.495 170.055 105.825 170.070 ;
        RECT 115.410 169.230 119.410 170.070 ;
        RECT 19.410 168.430 119.410 169.230 ;
        RECT 19.410 167.665 23.410 168.430 ;
        RECT 115.410 167.665 119.410 168.430 ;
        RECT 19.410 167.335 23.485 167.665 ;
        RECT 115.155 167.335 119.410 167.665 ;
        RECT 19.410 166.290 23.410 167.335 ;
        RECT 38.795 166.290 39.125 166.305 ;
        RECT 19.410 165.990 39.125 166.290 ;
        RECT 19.410 164.930 23.410 165.990 ;
        RECT 38.795 165.975 39.125 165.990 ;
        RECT 103.195 166.290 103.525 166.305 ;
        RECT 115.410 166.290 119.410 167.335 ;
        RECT 103.195 165.990 119.410 166.290 ;
        RECT 103.195 165.975 103.525 165.990 ;
        RECT 35.575 164.930 35.905 164.945 ;
        RECT 19.410 164.630 35.905 164.930 ;
        RECT 19.410 163.680 23.410 164.630 ;
        RECT 35.575 164.615 35.905 164.630 ;
        RECT 113.315 164.930 113.645 164.945 ;
        RECT 115.410 164.930 119.410 165.990 ;
        RECT 113.315 164.630 119.410 164.930 ;
        RECT 113.315 164.615 113.645 164.630 ;
        RECT 115.410 163.680 119.410 164.630 ;
        RECT 19.410 163.180 119.410 163.680 ;
        RECT 19.410 162.210 23.410 163.180 ;
        RECT 25.455 162.210 25.785 162.225 ;
        RECT 19.410 161.910 25.785 162.210 ;
        RECT 19.410 160.850 23.410 161.910 ;
        RECT 25.455 161.895 25.785 161.910 ;
        RECT 107.795 162.210 108.125 162.225 ;
        RECT 115.410 162.210 119.410 163.180 ;
        RECT 107.795 161.910 119.410 162.210 ;
        RECT 107.795 161.895 108.125 161.910 ;
        RECT 115.410 160.865 119.410 161.910 ;
        RECT 24.995 160.850 25.325 160.865 ;
        RECT 19.410 160.550 25.325 160.850 ;
        RECT 19.410 159.580 23.410 160.550 ;
        RECT 24.995 160.535 25.325 160.550 ;
        RECT 115.155 160.535 119.410 160.865 ;
        RECT 115.410 159.580 119.410 160.535 ;
        RECT 19.410 159.030 119.410 159.580 ;
        RECT 19.410 158.130 23.410 159.030 ;
        RECT 24.995 158.130 25.325 158.145 ;
        RECT 19.410 157.830 25.325 158.130 ;
        RECT 19.410 156.770 23.410 157.830 ;
        RECT 24.995 157.815 25.325 157.830 ;
        RECT 112.855 158.130 113.185 158.145 ;
        RECT 115.410 158.130 119.410 159.030 ;
        RECT 112.855 157.830 119.410 158.130 ;
        RECT 112.855 157.815 113.185 157.830 ;
        RECT 38.795 156.770 39.125 156.785 ;
        RECT 19.410 156.470 39.125 156.770 ;
        RECT 19.410 155.410 23.410 156.470 ;
        RECT 38.795 156.455 39.125 156.470 ;
        RECT 112.855 156.770 113.185 156.785 ;
        RECT 115.410 156.770 119.410 157.830 ;
        RECT 112.855 156.470 119.410 156.770 ;
        RECT 112.855 156.455 113.185 156.470 ;
        RECT 25.915 155.410 26.245 155.425 ;
        RECT 19.410 155.110 26.245 155.410 ;
        RECT 19.410 154.050 23.410 155.110 ;
        RECT 25.915 155.095 26.245 155.110 ;
        RECT 111.015 155.410 111.345 155.425 ;
        RECT 115.410 155.410 119.410 156.470 ;
        RECT 111.015 155.110 119.410 155.410 ;
        RECT 111.015 155.095 111.345 155.110 ;
        RECT 25.915 154.050 26.245 154.065 ;
        RECT 19.410 153.750 26.245 154.050 ;
        RECT 19.410 152.780 23.410 153.750 ;
        RECT 25.915 153.735 26.245 153.750 ;
        RECT 115.410 152.780 119.410 155.110 ;
        RECT 19.410 151.880 119.410 152.780 ;
        RECT 19.410 149.970 23.410 151.880 ;
        RECT 115.410 151.345 119.410 151.880 ;
        RECT 115.155 151.015 119.410 151.345 ;
        RECT 24.075 149.970 24.405 149.985 ;
        RECT 19.410 149.670 24.405 149.970 ;
        RECT 19.410 148.980 23.410 149.670 ;
        RECT 24.075 149.655 24.405 149.670 ;
        RECT 103.195 149.970 103.525 149.985 ;
        RECT 115.410 149.970 119.410 151.015 ;
        RECT 103.195 149.670 119.410 149.970 ;
        RECT 103.195 149.655 103.525 149.670 ;
        RECT 19.410 148.080 24.010 148.980 ;
        RECT 113.315 148.610 113.645 148.625 ;
        RECT 115.410 148.610 119.410 149.670 ;
        RECT 113.315 148.310 119.410 148.610 ;
        RECT 113.315 148.295 113.645 148.310 ;
        RECT 19.410 147.250 23.410 148.080 ;
        RECT 33.735 147.250 34.065 147.265 ;
        RECT 19.410 146.950 34.065 147.250 ;
        RECT 19.410 145.980 23.410 146.950 ;
        RECT 33.735 146.935 34.065 146.950 ;
        RECT 105.495 147.250 105.825 147.265 ;
        RECT 115.410 147.250 119.410 148.310 ;
        RECT 105.495 146.950 119.410 147.250 ;
        RECT 105.495 146.935 105.825 146.950 ;
        RECT 115.410 145.980 119.410 146.950 ;
        RECT 19.410 145.280 119.410 145.980 ;
        RECT 19.410 144.530 23.410 145.280 ;
        RECT 25.915 144.530 26.245 144.545 ;
        RECT 19.410 144.230 26.245 144.530 ;
        RECT 19.410 143.170 23.410 144.230 ;
        RECT 25.915 144.215 26.245 144.230 ;
        RECT 113.315 144.530 113.645 144.545 ;
        RECT 115.410 144.530 119.410 145.280 ;
        RECT 113.315 144.230 119.410 144.530 ;
        RECT 113.315 144.215 113.645 144.230 ;
        RECT 115.410 143.185 119.410 144.230 ;
        RECT 24.995 143.170 25.325 143.185 ;
        RECT 19.410 142.870 25.325 143.170 ;
        RECT 19.410 141.810 23.410 142.870 ;
        RECT 24.995 142.855 25.325 142.870 ;
        RECT 115.155 142.855 119.410 143.185 ;
        RECT 25.915 141.810 26.245 141.825 ;
        RECT 19.410 141.510 26.245 141.810 ;
        RECT 19.410 140.530 23.410 141.510 ;
        RECT 25.915 141.495 26.245 141.510 ;
        RECT 112.855 141.810 113.185 141.825 ;
        RECT 115.410 141.810 119.410 142.855 ;
        RECT 112.855 141.510 119.410 141.810 ;
        RECT 112.855 141.495 113.185 141.510 ;
        RECT 115.410 140.530 119.410 141.510 ;
        RECT 19.410 139.880 119.410 140.530 ;
        RECT 19.410 139.090 23.410 139.880 ;
        RECT 25.915 139.090 26.245 139.105 ;
        RECT 19.410 138.790 26.245 139.090 ;
        RECT 19.410 137.730 23.410 138.790 ;
        RECT 25.915 138.775 26.245 138.790 ;
        RECT 112.855 139.090 113.185 139.105 ;
        RECT 115.410 139.090 119.410 139.880 ;
        RECT 112.855 138.790 119.410 139.090 ;
        RECT 112.855 138.775 113.185 138.790 ;
        RECT 25.915 137.730 26.245 137.745 ;
        RECT 19.410 137.430 26.245 137.730 ;
        RECT 19.410 136.370 23.410 137.430 ;
        RECT 25.915 137.415 26.245 137.430 ;
        RECT 113.775 137.730 114.105 137.745 ;
        RECT 115.410 137.730 119.410 138.790 ;
        RECT 113.775 137.430 119.410 137.730 ;
        RECT 113.775 137.415 114.105 137.430 ;
        RECT 25.915 136.370 26.245 136.385 ;
        RECT 19.410 136.070 26.245 136.370 ;
        RECT 19.410 135.010 23.410 136.070 ;
        RECT 25.915 136.055 26.245 136.070 ;
        RECT 105.495 136.370 105.825 136.385 ;
        RECT 115.410 136.370 119.410 137.430 ;
        RECT 105.495 136.070 119.410 136.370 ;
        RECT 105.495 136.055 105.825 136.070 ;
        RECT 25.455 135.010 25.785 135.025 ;
        RECT 19.410 134.710 25.785 135.010 ;
        RECT 19.410 133.780 23.410 134.710 ;
        RECT 25.455 134.695 25.785 134.710 ;
        RECT 111.015 135.010 111.345 135.025 ;
        RECT 115.410 135.010 119.410 136.070 ;
        RECT 111.015 134.710 119.410 135.010 ;
        RECT 111.015 134.695 111.345 134.710 ;
        RECT 115.410 133.780 119.410 134.710 ;
        RECT 19.410 133.130 119.410 133.780 ;
        RECT 19.410 132.290 23.410 133.130 ;
        RECT 24.995 132.290 25.325 132.305 ;
        RECT 19.410 131.990 25.325 132.290 ;
        RECT 19.410 130.930 23.410 131.990 ;
        RECT 24.995 131.975 25.325 131.990 ;
        RECT 113.315 132.290 113.645 132.305 ;
        RECT 115.410 132.290 119.410 133.130 ;
        RECT 113.315 131.990 119.410 132.290 ;
        RECT 113.315 131.975 113.645 131.990 ;
        RECT 35.575 130.930 35.905 130.945 ;
        RECT 19.410 130.630 35.905 130.930 ;
        RECT 19.410 129.570 23.410 130.630 ;
        RECT 35.575 130.615 35.905 130.630 ;
        RECT 112.855 130.930 113.185 130.945 ;
        RECT 115.410 130.930 119.410 131.990 ;
        RECT 112.855 130.630 119.410 130.930 ;
        RECT 112.855 130.615 113.185 130.630 ;
        RECT 36.035 129.570 36.365 129.585 ;
        RECT 19.410 129.270 36.365 129.570 ;
        RECT 19.410 128.280 23.410 129.270 ;
        RECT 36.035 129.255 36.365 129.270 ;
        RECT 107.795 129.570 108.125 129.585 ;
        RECT 115.410 129.570 119.410 130.630 ;
        RECT 107.795 129.270 119.410 129.570 ;
        RECT 107.795 129.255 108.125 129.270 ;
        RECT 115.410 128.280 119.410 129.270 ;
        RECT 19.410 127.735 119.410 128.280 ;
        RECT 19.410 126.850 23.410 127.735 ;
        RECT 33.735 126.850 34.065 126.865 ;
        RECT 19.410 126.550 34.065 126.850 ;
        RECT 19.410 125.490 23.410 126.550 ;
        RECT 33.735 126.535 34.065 126.550 ;
        RECT 105.495 126.850 105.825 126.865 ;
        RECT 115.410 126.850 119.410 127.735 ;
        RECT 105.495 126.550 119.410 126.850 ;
        RECT 105.495 126.535 105.825 126.550 ;
        RECT 25.455 125.490 25.785 125.505 ;
        RECT 19.410 125.190 25.785 125.490 ;
        RECT 19.410 124.130 23.410 125.190 ;
        RECT 25.455 125.175 25.785 125.190 ;
        RECT 113.315 125.490 113.645 125.505 ;
        RECT 115.410 125.490 119.410 126.550 ;
        RECT 113.315 125.190 119.410 125.490 ;
        RECT 113.315 125.175 113.645 125.190 ;
        RECT 25.915 124.130 26.245 124.145 ;
        RECT 19.410 123.830 26.245 124.130 ;
        RECT 19.410 122.770 23.410 123.830 ;
        RECT 25.915 123.815 26.245 123.830 ;
        RECT 105.495 124.130 105.825 124.145 ;
        RECT 115.410 124.130 119.410 125.190 ;
        RECT 105.495 123.830 119.410 124.130 ;
        RECT 105.495 123.815 105.825 123.830 ;
        RECT 25.915 122.770 26.245 122.785 ;
        RECT 19.410 122.470 26.245 122.770 ;
        RECT 19.410 121.480 23.410 122.470 ;
        RECT 25.915 122.455 26.245 122.470 ;
        RECT 110.555 122.770 110.885 122.785 ;
        RECT 115.410 122.770 119.410 123.830 ;
        RECT 110.555 122.470 119.410 122.770 ;
        RECT 110.555 122.455 110.885 122.470 ;
        RECT 115.410 121.480 119.410 122.470 ;
        RECT 19.410 120.880 119.410 121.480 ;
        RECT 19.410 120.050 23.410 120.880 ;
        RECT 33.735 120.050 34.065 120.065 ;
        RECT 19.410 119.750 34.065 120.050 ;
        RECT 19.410 118.690 23.410 119.750 ;
        RECT 33.735 119.735 34.065 119.750 ;
        RECT 113.315 120.050 113.645 120.065 ;
        RECT 115.410 120.050 119.410 120.880 ;
        RECT 113.315 119.750 119.410 120.050 ;
        RECT 113.315 119.735 113.645 119.750 ;
        RECT 25.915 118.690 26.245 118.705 ;
        RECT 19.410 118.390 26.245 118.690 ;
        RECT 19.410 117.330 23.410 118.390 ;
        RECT 25.915 118.375 26.245 118.390 ;
        RECT 112.855 118.690 113.185 118.705 ;
        RECT 115.410 118.690 119.410 119.750 ;
        RECT 112.855 118.390 119.410 118.690 ;
        RECT 112.855 118.375 113.185 118.390 ;
        RECT 25.455 117.330 25.785 117.345 ;
        RECT 19.410 117.030 25.785 117.330 ;
        RECT 19.410 116.080 23.410 117.030 ;
        RECT 25.455 117.015 25.785 117.030 ;
        RECT 107.795 117.330 108.125 117.345 ;
        RECT 115.410 117.330 119.410 118.390 ;
        RECT 107.795 117.030 119.410 117.330 ;
        RECT 107.795 117.015 108.125 117.030 ;
        RECT 115.410 116.080 119.410 117.030 ;
        RECT 19.410 115.330 119.410 116.080 ;
        RECT 19.410 114.610 23.410 115.330 ;
        RECT 25.915 114.610 26.245 114.625 ;
        RECT 19.410 114.310 26.245 114.610 ;
        RECT 19.410 113.250 23.410 114.310 ;
        RECT 25.915 114.295 26.245 114.310 ;
        RECT 105.495 114.610 105.825 114.625 ;
        RECT 115.410 114.610 119.410 115.330 ;
        RECT 105.495 114.310 119.410 114.610 ;
        RECT 105.495 114.295 105.825 114.310 ;
        RECT 24.995 113.250 25.325 113.265 ;
        RECT 19.410 112.950 25.325 113.250 ;
        RECT 19.410 111.890 23.410 112.950 ;
        RECT 24.995 112.935 25.325 112.950 ;
        RECT 107.795 113.250 108.125 113.265 ;
        RECT 115.410 113.250 119.410 114.310 ;
        RECT 107.795 112.950 119.410 113.250 ;
        RECT 107.795 112.935 108.125 112.950 ;
        RECT 25.915 111.890 26.245 111.905 ;
        RECT 19.410 111.590 26.245 111.890 ;
        RECT 19.410 110.530 23.410 111.590 ;
        RECT 25.915 111.575 26.245 111.590 ;
        RECT 110.555 111.890 110.885 111.905 ;
        RECT 115.410 111.890 119.410 112.950 ;
        RECT 110.555 111.590 119.410 111.890 ;
        RECT 110.555 111.575 110.885 111.590 ;
        RECT 24.535 110.530 24.865 110.545 ;
        RECT 19.410 110.230 24.865 110.530 ;
        RECT 19.410 109.280 23.410 110.230 ;
        RECT 24.535 110.215 24.865 110.230 ;
        RECT 105.495 110.530 105.825 110.545 ;
        RECT 115.410 110.530 119.410 111.590 ;
        RECT 105.495 110.230 119.410 110.530 ;
        RECT 105.495 110.215 105.825 110.230 ;
        RECT 115.410 109.280 119.410 110.230 ;
        RECT 19.410 108.730 119.410 109.280 ;
        RECT 19.410 107.810 23.410 108.730 ;
        RECT 35.575 107.810 35.905 107.825 ;
        RECT 19.410 107.510 35.905 107.810 ;
        RECT 19.410 106.450 23.410 107.510 ;
        RECT 35.575 107.495 35.905 107.510 ;
        RECT 113.315 107.810 113.645 107.825 ;
        RECT 115.410 107.810 119.410 108.730 ;
        RECT 113.315 107.510 119.410 107.810 ;
        RECT 113.315 107.495 113.645 107.510 ;
        RECT 25.915 106.450 26.245 106.465 ;
        RECT 19.410 106.150 26.245 106.450 ;
        RECT 19.410 105.090 23.410 106.150 ;
        RECT 25.915 106.135 26.245 106.150 ;
        RECT 112.855 106.450 113.185 106.465 ;
        RECT 115.410 106.450 119.410 107.510 ;
        RECT 112.855 106.150 119.410 106.450 ;
        RECT 112.855 106.135 113.185 106.150 ;
        RECT 25.915 105.090 26.245 105.105 ;
        RECT 19.410 104.790 26.245 105.090 ;
        RECT 19.410 103.880 23.410 104.790 ;
        RECT 25.915 104.775 26.245 104.790 ;
        RECT 107.795 105.090 108.125 105.105 ;
        RECT 115.410 105.090 119.410 106.150 ;
        RECT 107.795 104.790 119.410 105.090 ;
        RECT 107.795 104.775 108.125 104.790 ;
        RECT 115.410 103.880 119.410 104.790 ;
        RECT 19.410 103.180 119.410 103.880 ;
        RECT 19.410 102.370 23.410 103.180 ;
        RECT 35.575 102.370 35.905 102.385 ;
        RECT 19.410 102.070 35.905 102.370 ;
        RECT 19.410 101.010 23.410 102.070 ;
        RECT 35.575 102.055 35.905 102.070 ;
        RECT 105.495 102.370 105.825 102.385 ;
        RECT 115.410 102.370 119.410 103.180 ;
        RECT 105.495 102.070 119.410 102.370 ;
        RECT 105.495 102.055 105.825 102.070 ;
        RECT 36.035 101.010 36.365 101.025 ;
        RECT 19.410 100.710 36.365 101.010 ;
        RECT 19.410 99.650 23.410 100.710 ;
        RECT 36.035 100.695 36.365 100.710 ;
        RECT 107.795 101.010 108.125 101.025 ;
        RECT 115.410 101.010 119.410 102.070 ;
        RECT 107.795 100.710 119.410 101.010 ;
        RECT 107.795 100.695 108.125 100.710 ;
        RECT 25.455 99.650 25.785 99.665 ;
        RECT 19.410 99.350 25.785 99.650 ;
        RECT 19.410 98.480 23.410 99.350 ;
        RECT 25.455 99.335 25.785 99.350 ;
        RECT 105.495 99.650 105.825 99.665 ;
        RECT 115.410 99.650 119.410 100.710 ;
        RECT 105.495 99.350 119.410 99.650 ;
        RECT 105.495 99.335 105.825 99.350 ;
        RECT 115.410 98.480 119.410 99.350 ;
        RECT 19.410 97.780 119.410 98.480 ;
        RECT 19.410 96.930 23.410 97.780 ;
        RECT 24.995 96.930 25.325 96.945 ;
        RECT 19.410 96.630 25.325 96.930 ;
        RECT 19.410 95.570 23.410 96.630 ;
        RECT 24.995 96.615 25.325 96.630 ;
        RECT 112.855 96.930 113.185 96.945 ;
        RECT 115.410 96.930 119.410 97.780 ;
        RECT 112.855 96.630 119.410 96.930 ;
        RECT 112.855 96.615 113.185 96.630 ;
        RECT 41.095 95.570 41.425 95.585 ;
        RECT 19.410 95.270 41.425 95.570 ;
        RECT 19.410 94.210 23.410 95.270 ;
        RECT 41.095 95.255 41.425 95.270 ;
        RECT 115.410 94.225 119.410 96.630 ;
        RECT 35.575 94.210 35.905 94.225 ;
        RECT 19.410 93.910 35.905 94.210 ;
        RECT 19.410 92.955 23.410 93.910 ;
        RECT 35.575 93.895 35.905 93.910 ;
        RECT 115.155 93.895 119.410 94.225 ;
        RECT 115.410 92.955 119.410 93.895 ;
        RECT 19.410 91.980 119.410 92.955 ;
        RECT 19.410 91.490 23.410 91.980 ;
        RECT 25.915 91.490 26.245 91.505 ;
        RECT 19.410 91.190 26.245 91.490 ;
        RECT 19.410 90.130 23.410 91.190 ;
        RECT 25.915 91.175 26.245 91.190 ;
        RECT 33.735 90.130 34.065 90.145 ;
        RECT 19.410 89.830 34.065 90.130 ;
        RECT 19.410 88.770 23.410 89.830 ;
        RECT 33.735 89.815 34.065 89.830 ;
        RECT 108.715 90.130 109.045 90.145 ;
        RECT 115.410 90.130 119.410 91.980 ;
        RECT 108.715 89.830 119.410 90.130 ;
        RECT 108.715 89.815 109.045 89.830 ;
        RECT 115.410 88.980 119.410 89.830 ;
        RECT 27.755 88.770 28.085 88.785 ;
        RECT 19.410 88.470 28.085 88.770 ;
        RECT 19.410 87.455 23.410 88.470 ;
        RECT 27.755 88.455 28.085 88.470 ;
        RECT 114.605 88.180 119.410 88.980 ;
        RECT 115.410 87.455 119.410 88.180 ;
        RECT 19.410 86.480 119.410 87.455 ;
        RECT 19.410 85.480 23.410 86.480 ;
        RECT 115.410 85.480 119.410 86.480 ;
        RECT 16.090 81.020 122.570 82.620 ;
        RECT 4.000 77.820 125.770 79.420 ;
        RECT 4.000 29.240 6.000 77.820 ;
        RECT 19.190 74.960 23.450 77.400 ;
        RECT 19.730 47.620 23.100 74.960 ;
        RECT 116.970 57.925 117.565 58.380 ;
        RECT 18.620 43.780 24.230 47.620 ;
        RECT 117.110 41.335 117.460 57.925 ;
        RECT 126.910 45.395 127.400 58.555 ;
        RECT 126.805 44.765 127.505 45.395 ;
        RECT 117.005 40.705 117.565 41.335 ;
      LAYER met4 ;
        RECT 19.425 189.315 127.330 189.665 ;
        RECT 11.690 178.885 12.460 179.480 ;
        RECT 10.200 172.720 11.220 173.740 ;
        RECT 10.540 51.450 10.880 172.720 ;
        RECT 11.900 73.105 12.215 178.885 ;
        RECT 12.890 77.820 14.490 186.890 ;
        RECT 16.090 81.020 17.690 183.690 ;
        RECT 19.425 181.405 19.775 189.315 ;
        RECT 19.285 180.740 19.880 181.405 ;
        RECT 20.055 86.030 22.715 97.930 ;
        RECT 20.440 77.660 22.365 86.030 ;
        RECT 26.390 81.020 27.990 183.690 ;
        RECT 28.890 77.820 30.490 186.890 ;
        RECT 31.390 81.020 32.990 183.690 ;
        RECT 33.890 77.820 35.490 186.890 ;
        RECT 36.390 81.020 37.990 183.690 ;
        RECT 38.890 77.820 40.490 186.890 ;
        RECT 41.390 81.020 42.990 183.690 ;
        RECT 43.890 77.820 45.490 186.890 ;
        RECT 46.390 81.020 47.990 183.690 ;
        RECT 48.890 77.820 50.490 186.890 ;
        RECT 51.390 81.020 52.990 183.690 ;
        RECT 53.890 77.820 55.490 186.890 ;
        RECT 56.390 81.020 57.990 183.690 ;
        RECT 58.890 77.820 60.490 186.890 ;
        RECT 61.390 81.020 62.990 183.690 ;
        RECT 63.890 77.820 65.490 186.890 ;
        RECT 66.390 81.020 67.990 183.690 ;
        RECT 68.890 77.820 70.490 186.890 ;
        RECT 71.390 81.020 72.990 183.690 ;
        RECT 73.890 77.820 75.490 186.890 ;
        RECT 76.390 81.020 77.990 183.690 ;
        RECT 78.890 77.820 80.490 186.890 ;
        RECT 81.390 81.020 82.990 183.690 ;
        RECT 83.890 77.820 85.490 186.890 ;
        RECT 86.390 81.020 87.990 183.690 ;
        RECT 88.890 77.820 90.490 186.890 ;
        RECT 91.390 81.020 92.990 183.690 ;
        RECT 93.890 77.820 95.490 186.890 ;
        RECT 96.390 81.020 97.990 183.690 ;
        RECT 98.890 77.820 100.490 186.890 ;
        RECT 101.390 81.020 102.990 183.690 ;
        RECT 103.890 77.820 105.490 186.890 ;
        RECT 106.390 81.020 107.990 183.690 ;
        RECT 108.890 77.820 110.490 186.890 ;
        RECT 111.390 81.020 112.990 183.690 ;
        RECT 120.970 81.020 122.570 183.690 ;
        RECT 124.170 77.820 125.770 186.890 ;
        RECT 18.500 74.530 24.070 77.660 ;
        RECT 11.900 72.790 117.475 73.105 ;
        RECT 11.900 72.750 12.215 72.790 ;
        RECT 117.160 58.380 117.475 72.790 ;
        RECT 126.980 58.380 127.330 189.315 ;
        RECT 116.935 57.890 117.635 58.380 ;
        RECT 126.840 57.890 127.470 58.380 ;
        RECT 10.540 51.170 137.070 51.450 ;
        RECT 10.540 50.830 137.360 51.170 ;
        RECT 10.540 50.550 137.070 50.830 ;
        RECT 18.120 45.250 24.610 48.110 ;
        RECT 18.120 44.350 79.110 45.250 ;
        RECT 18.120 43.320 24.610 44.350 ;
        RECT 78.210 1.000 79.110 44.350 ;
        RECT 97.530 44.665 127.780 45.565 ;
        RECT 97.530 1.000 98.430 44.665 ;
        RECT 116.850 1.000 117.750 41.575 ;
        RECT 136.170 1.000 137.070 50.550 ;
  END
END tt_um_STDCELL_LDO
END LIBRARY

